VERSION 5.8 ;
BUSBITCHARS "[]" ;
DIVIDERCHAR "/" ;
UNITS
    DATABASE MICRONS 1000 ;
END UNITS

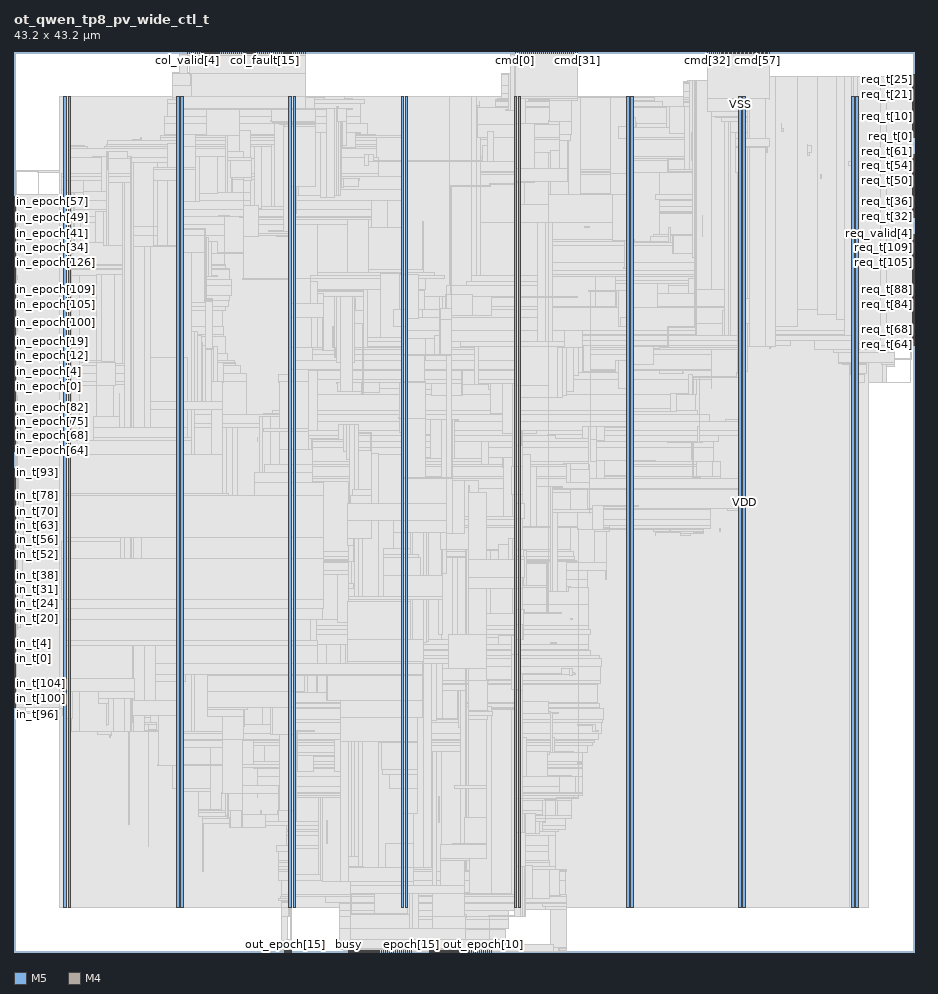
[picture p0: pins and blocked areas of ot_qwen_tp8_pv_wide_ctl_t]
MACRO ot_qwen_tp8_pv_wide_ctl_t
  FOREIGN ot_qwen_tp8_pv_wide_ctl_t 0 0 ;
  CLASS BLOCK ;
  SIZE 43.2 BY 43.2 ;
  PIN busy
    DIRECTION OUTPUT ;
    USE SIGNAL ;
    PORT
      LAYER M5 ;
        RECT  16.08 0 16.104 0.084 ;
    END
  END busy
  PIN clk
    DIRECTION INPUT ;
    USE SIGNAL ;
    PORT
      LAYER M5 ;
        RECT  16.176 0 16.2 0.084 ;
    END
  END clk
  PIN cmd[0]
    DIRECTION OUTPUT ;
    USE SIGNAL ;
    PORT
      LAYER M5 ;
        RECT  24.048 43.116 24.072 43.2 ;
    END
  END cmd[0]
  PIN cmd[10]
    DIRECTION OUTPUT ;
    USE SIGNAL ;
    PORT
      LAYER M5 ;
        RECT  25.008 43.116 25.032 43.2 ;
    END
  END cmd[10]
  PIN cmd[11]
    DIRECTION OUTPUT ;
    USE SIGNAL ;
    PORT
      LAYER M5 ;
        RECT  25.104 43.116 25.128 43.2 ;
    END
  END cmd[11]
  PIN cmd[12]
    DIRECTION OUTPUT ;
    USE SIGNAL ;
    PORT
      LAYER M5 ;
        RECT  25.2 43.116 25.224 43.2 ;
    END
  END cmd[12]
  PIN cmd[13]
    DIRECTION OUTPUT ;
    USE SIGNAL ;
    PORT
      LAYER M5 ;
        RECT  25.296 43.116 25.32 43.2 ;
    END
  END cmd[13]
  PIN cmd[14]
    DIRECTION OUTPUT ;
    USE SIGNAL ;
    PORT
      LAYER M5 ;
        RECT  25.392 43.116 25.416 43.2 ;
    END
  END cmd[14]
  PIN cmd[15]
    DIRECTION OUTPUT ;
    USE SIGNAL ;
    PORT
      LAYER M5 ;
        RECT  25.488 43.116 25.512 43.2 ;
    END
  END cmd[15]
  PIN cmd[16]
    DIRECTION OUTPUT ;
    USE SIGNAL ;
    PORT
      LAYER M5 ;
        RECT  25.584 43.116 25.608 43.2 ;
    END
  END cmd[16]
  PIN cmd[17]
    DIRECTION OUTPUT ;
    USE SIGNAL ;
    PORT
      LAYER M5 ;
        RECT  25.68 43.116 25.704 43.2 ;
    END
  END cmd[17]
  PIN cmd[18]
    DIRECTION OUTPUT ;
    USE SIGNAL ;
    PORT
      LAYER M5 ;
        RECT  25.776 43.116 25.8 43.2 ;
    END
  END cmd[18]
  PIN cmd[19]
    DIRECTION OUTPUT ;
    USE SIGNAL ;
    PORT
      LAYER M5 ;
        RECT  25.872 43.116 25.896 43.2 ;
    END
  END cmd[19]
  PIN cmd[1]
    DIRECTION OUTPUT ;
    USE SIGNAL ;
    PORT
      LAYER M5 ;
        RECT  24.144 43.116 24.168 43.2 ;
    END
  END cmd[1]
  PIN cmd[20]
    DIRECTION OUTPUT ;
    USE SIGNAL ;
    PORT
      LAYER M5 ;
        RECT  25.968 43.116 25.992 43.2 ;
    END
  END cmd[20]
  PIN cmd[21]
    DIRECTION OUTPUT ;
    USE SIGNAL ;
    PORT
      LAYER M5 ;
        RECT  26.064 43.116 26.088 43.2 ;
    END
  END cmd[21]
  PIN cmd[22]
    DIRECTION OUTPUT ;
    USE SIGNAL ;
    PORT
      LAYER M5 ;
        RECT  26.16 43.116 26.184 43.2 ;
    END
  END cmd[22]
  PIN cmd[23]
    DIRECTION OUTPUT ;
    USE SIGNAL ;
    PORT
      LAYER M5 ;
        RECT  26.256 43.116 26.28 43.2 ;
    END
  END cmd[23]
  PIN cmd[24]
    DIRECTION OUTPUT ;
    USE SIGNAL ;
    PORT
      LAYER M5 ;
        RECT  26.352 43.116 26.376 43.2 ;
    END
  END cmd[24]
  PIN cmd[25]
    DIRECTION OUTPUT ;
    USE SIGNAL ;
    PORT
      LAYER M5 ;
        RECT  26.448 43.116 26.472 43.2 ;
    END
  END cmd[25]
  PIN cmd[26]
    DIRECTION OUTPUT ;
    USE SIGNAL ;
    PORT
      LAYER M5 ;
        RECT  26.544 43.116 26.568 43.2 ;
    END
  END cmd[26]
  PIN cmd[27]
    DIRECTION OUTPUT ;
    USE SIGNAL ;
    PORT
      LAYER M5 ;
        RECT  26.64 43.116 26.664 43.2 ;
    END
  END cmd[27]
  PIN cmd[28]
    DIRECTION OUTPUT ;
    USE SIGNAL ;
    PORT
      LAYER M5 ;
        RECT  26.736 43.116 26.76 43.2 ;
    END
  END cmd[28]
  PIN cmd[29]
    DIRECTION OUTPUT ;
    USE SIGNAL ;
    PORT
      LAYER M5 ;
        RECT  26.832 43.116 26.856 43.2 ;
    END
  END cmd[29]
  PIN cmd[2]
    DIRECTION OUTPUT ;
    USE SIGNAL ;
    PORT
      LAYER M5 ;
        RECT  24.24 43.116 24.264 43.2 ;
    END
  END cmd[2]
  PIN cmd[30]
    DIRECTION OUTPUT ;
    USE SIGNAL ;
    PORT
      LAYER M5 ;
        RECT  26.928 43.116 26.952 43.2 ;
    END
  END cmd[30]
  PIN cmd[31]
    DIRECTION OUTPUT ;
    USE SIGNAL ;
    PORT
      LAYER M5 ;
        RECT  27.024 43.116 27.048 43.2 ;
    END
  END cmd[31]
  PIN cmd[32]
    DIRECTION OUTPUT ;
    USE SIGNAL ;
    PORT
      LAYER M5 ;
        RECT  33.264 43.116 33.288 43.2 ;
    END
  END cmd[32]
  PIN cmd[33]
    DIRECTION OUTPUT ;
    USE SIGNAL ;
    PORT
      LAYER M5 ;
        RECT  33.36 43.116 33.384 43.2 ;
    END
  END cmd[33]
  PIN cmd[34]
    DIRECTION OUTPUT ;
    USE SIGNAL ;
    PORT
      LAYER M5 ;
        RECT  33.456 43.116 33.48 43.2 ;
    END
  END cmd[34]
  PIN cmd[35]
    DIRECTION OUTPUT ;
    USE SIGNAL ;
    PORT
      LAYER M5 ;
        RECT  33.552 43.116 33.576 43.2 ;
    END
  END cmd[35]
  PIN cmd[36]
    DIRECTION OUTPUT ;
    USE SIGNAL ;
    PORT
      LAYER M5 ;
        RECT  33.648 43.116 33.672 43.2 ;
    END
  END cmd[36]
  PIN cmd[37]
    DIRECTION OUTPUT ;
    USE SIGNAL ;
    PORT
      LAYER M5 ;
        RECT  33.744 43.116 33.768 43.2 ;
    END
  END cmd[37]
  PIN cmd[38]
    DIRECTION OUTPUT ;
    USE SIGNAL ;
    PORT
      LAYER M5 ;
        RECT  33.84 43.116 33.864 43.2 ;
    END
  END cmd[38]
  PIN cmd[39]
    DIRECTION OUTPUT ;
    USE SIGNAL ;
    PORT
      LAYER M5 ;
        RECT  33.936 43.116 33.96 43.2 ;
    END
  END cmd[39]
  PIN cmd[3]
    DIRECTION OUTPUT ;
    USE SIGNAL ;
    PORT
      LAYER M5 ;
        RECT  24.336 43.116 24.36 43.2 ;
    END
  END cmd[3]
  PIN cmd[40]
    DIRECTION OUTPUT ;
    USE SIGNAL ;
    PORT
      LAYER M5 ;
        RECT  34.032 43.116 34.056 43.2 ;
    END
  END cmd[40]
  PIN cmd[41]
    DIRECTION OUTPUT ;
    USE SIGNAL ;
    PORT
      LAYER M5 ;
        RECT  34.128 43.116 34.152 43.2 ;
    END
  END cmd[41]
  PIN cmd[42]
    DIRECTION OUTPUT ;
    USE SIGNAL ;
    PORT
      LAYER M5 ;
        RECT  34.224 43.116 34.248 43.2 ;
    END
  END cmd[42]
  PIN cmd[43]
    DIRECTION OUTPUT ;
    USE SIGNAL ;
    PORT
      LAYER M5 ;
        RECT  34.32 43.116 34.344 43.2 ;
    END
  END cmd[43]
  PIN cmd[44]
    DIRECTION OUTPUT ;
    USE SIGNAL ;
    PORT
      LAYER M5 ;
        RECT  34.416 43.116 34.44 43.2 ;
    END
  END cmd[44]
  PIN cmd[45]
    DIRECTION OUTPUT ;
    USE SIGNAL ;
    PORT
      LAYER M5 ;
        RECT  34.512 43.116 34.536 43.2 ;
    END
  END cmd[45]
  PIN cmd[46]
    DIRECTION OUTPUT ;
    USE SIGNAL ;
    PORT
      LAYER M5 ;
        RECT  34.608 43.116 34.632 43.2 ;
    END
  END cmd[46]
  PIN cmd[47]
    DIRECTION OUTPUT ;
    USE SIGNAL ;
    PORT
      LAYER M5 ;
        RECT  34.704 43.116 34.728 43.2 ;
    END
  END cmd[47]
  PIN cmd[48]
    DIRECTION OUTPUT ;
    USE SIGNAL ;
    PORT
      LAYER M5 ;
        RECT  34.8 43.116 34.824 43.2 ;
    END
  END cmd[48]
  PIN cmd[49]
    DIRECTION OUTPUT ;
    USE SIGNAL ;
    PORT
      LAYER M5 ;
        RECT  34.896 43.116 34.92 43.2 ;
    END
  END cmd[49]
  PIN cmd[4]
    DIRECTION OUTPUT ;
    USE SIGNAL ;
    PORT
      LAYER M5 ;
        RECT  24.432 43.116 24.456 43.2 ;
    END
  END cmd[4]
  PIN cmd[50]
    DIRECTION OUTPUT ;
    USE SIGNAL ;
    PORT
      LAYER M5 ;
        RECT  34.992 43.116 35.016 43.2 ;
    END
  END cmd[50]
  PIN cmd[51]
    DIRECTION OUTPUT ;
    USE SIGNAL ;
    PORT
      LAYER M5 ;
        RECT  35.088 43.116 35.112 43.2 ;
    END
  END cmd[51]
  PIN cmd[52]
    DIRECTION OUTPUT ;
    USE SIGNAL ;
    PORT
      LAYER M5 ;
        RECT  35.184 43.116 35.208 43.2 ;
    END
  END cmd[52]
  PIN cmd[53]
    DIRECTION OUTPUT ;
    USE SIGNAL ;
    PORT
      LAYER M5 ;
        RECT  35.28 43.116 35.304 43.2 ;
    END
  END cmd[53]
  PIN cmd[54]
    DIRECTION OUTPUT ;
    USE SIGNAL ;
    PORT
      LAYER M5 ;
        RECT  35.376 43.116 35.4 43.2 ;
    END
  END cmd[54]
  PIN cmd[55]
    DIRECTION OUTPUT ;
    USE SIGNAL ;
    PORT
      LAYER M5 ;
        RECT  35.472 43.116 35.496 43.2 ;
    END
  END cmd[55]
  PIN cmd[56]
    DIRECTION OUTPUT ;
    USE SIGNAL ;
    PORT
      LAYER M5 ;
        RECT  35.568 43.116 35.592 43.2 ;
    END
  END cmd[56]
  PIN cmd[57]
    DIRECTION OUTPUT ;
    USE SIGNAL ;
    PORT
      LAYER M5 ;
        RECT  35.664 43.116 35.688 43.2 ;
    END
  END cmd[57]
  PIN cmd[58]
    DIRECTION OUTPUT ;
    USE SIGNAL ;
    PORT
      LAYER M5 ;
        RECT  35.76 43.116 35.784 43.2 ;
    END
  END cmd[58]
  PIN cmd[59]
    DIRECTION OUTPUT ;
    USE SIGNAL ;
    PORT
      LAYER M5 ;
        RECT  35.856 43.116 35.88 43.2 ;
    END
  END cmd[59]
  PIN cmd[5]
    DIRECTION OUTPUT ;
    USE SIGNAL ;
    PORT
      LAYER M5 ;
        RECT  24.528 43.116 24.552 43.2 ;
    END
  END cmd[5]
  PIN cmd[6]
    DIRECTION OUTPUT ;
    USE SIGNAL ;
    PORT
      LAYER M5 ;
        RECT  24.624 43.116 24.648 43.2 ;
    END
  END cmd[6]
  PIN cmd[7]
    DIRECTION OUTPUT ;
    USE SIGNAL ;
    PORT
      LAYER M5 ;
        RECT  24.72 43.116 24.744 43.2 ;
    END
  END cmd[7]
  PIN cmd[8]
    DIRECTION OUTPUT ;
    USE SIGNAL ;
    PORT
      LAYER M5 ;
        RECT  24.816 43.116 24.84 43.2 ;
    END
  END cmd[8]
  PIN cmd[9]
    DIRECTION OUTPUT ;
    USE SIGNAL ;
    PORT
      LAYER M5 ;
        RECT  24.912 43.116 24.936 43.2 ;
    END
  END cmd[9]
  PIN col_fault[0]
    DIRECTION INPUT ;
    USE SIGNAL ;
    PORT
      LAYER M5 ;
        RECT  35.952 43.116 35.976 43.2 ;
    END
  END col_fault[0]
  PIN col_fault[10]
    DIRECTION INPUT ;
    USE SIGNAL ;
    PORT
      LAYER M5 ;
        RECT  11.568 43.116 11.592 43.2 ;
    END
  END col_fault[10]
  PIN col_fault[11]
    DIRECTION INPUT ;
    USE SIGNAL ;
    PORT
      LAYER M5 ;
        RECT  11.664 43.116 11.688 43.2 ;
    END
  END col_fault[11]
  PIN col_fault[12]
    DIRECTION INPUT ;
    USE SIGNAL ;
    PORT
      LAYER M5 ;
        RECT  11.76 43.116 11.784 43.2 ;
    END
  END col_fault[12]
  PIN col_fault[13]
    DIRECTION INPUT ;
    USE SIGNAL ;
    PORT
      LAYER M5 ;
        RECT  11.856 43.116 11.88 43.2 ;
    END
  END col_fault[13]
  PIN col_fault[14]
    DIRECTION INPUT ;
    USE SIGNAL ;
    PORT
      LAYER M5 ;
        RECT  11.952 43.116 11.976 43.2 ;
    END
  END col_fault[14]
  PIN col_fault[15]
    DIRECTION INPUT ;
    USE SIGNAL ;
    PORT
      LAYER M5 ;
        RECT  12.048 43.116 12.072 43.2 ;
    END
  END col_fault[15]
  PIN col_fault[16]
    DIRECTION INPUT ;
    USE SIGNAL ;
    PORT
      LAYER M5 ;
        RECT  12.144 43.116 12.168 43.2 ;
    END
  END col_fault[16]
  PIN col_fault[17]
    DIRECTION INPUT ;
    USE SIGNAL ;
    PORT
      LAYER M5 ;
        RECT  12.24 43.116 12.264 43.2 ;
    END
  END col_fault[17]
  PIN col_fault[18]
    DIRECTION INPUT ;
    USE SIGNAL ;
    PORT
      LAYER M5 ;
        RECT  12.336 43.116 12.36 43.2 ;
    END
  END col_fault[18]
  PIN col_fault[19]
    DIRECTION INPUT ;
    USE SIGNAL ;
    PORT
      LAYER M5 ;
        RECT  12.432 43.116 12.456 43.2 ;
    END
  END col_fault[19]
  PIN col_fault[1]
    DIRECTION INPUT ;
    USE SIGNAL ;
    PORT
      LAYER M5 ;
        RECT  36.048 43.116 36.072 43.2 ;
    END
  END col_fault[1]
  PIN col_fault[20]
    DIRECTION INPUT ;
    USE SIGNAL ;
    PORT
      LAYER M5 ;
        RECT  12.528 43.116 12.552 43.2 ;
    END
  END col_fault[20]
  PIN col_fault[21]
    DIRECTION INPUT ;
    USE SIGNAL ;
    PORT
      LAYER M5 ;
        RECT  12.624 43.116 12.648 43.2 ;
    END
  END col_fault[21]
  PIN col_fault[22]
    DIRECTION INPUT ;
    USE SIGNAL ;
    PORT
      LAYER M5 ;
        RECT  12.72 43.116 12.744 43.2 ;
    END
  END col_fault[22]
  PIN col_fault[23]
    DIRECTION INPUT ;
    USE SIGNAL ;
    PORT
      LAYER M5 ;
        RECT  12.816 43.116 12.84 43.2 ;
    END
  END col_fault[23]
  PIN col_fault[24]
    DIRECTION INPUT ;
    USE SIGNAL ;
    PORT
      LAYER M5 ;
        RECT  12.912 43.116 12.936 43.2 ;
    END
  END col_fault[24]
  PIN col_fault[25]
    DIRECTION INPUT ;
    USE SIGNAL ;
    PORT
      LAYER M5 ;
        RECT  13.008 43.116 13.032 43.2 ;
    END
  END col_fault[25]
  PIN col_fault[26]
    DIRECTION INPUT ;
    USE SIGNAL ;
    PORT
      LAYER M5 ;
        RECT  13.104 43.116 13.128 43.2 ;
    END
  END col_fault[26]
  PIN col_fault[27]
    DIRECTION INPUT ;
    USE SIGNAL ;
    PORT
      LAYER M5 ;
        RECT  13.2 43.116 13.224 43.2 ;
    END
  END col_fault[27]
  PIN col_fault[28]
    DIRECTION INPUT ;
    USE SIGNAL ;
    PORT
      LAYER M5 ;
        RECT  13.296 43.116 13.32 43.2 ;
    END
  END col_fault[28]
  PIN col_fault[29]
    DIRECTION INPUT ;
    USE SIGNAL ;
    PORT
      LAYER M5 ;
        RECT  13.392 43.116 13.416 43.2 ;
    END
  END col_fault[29]
  PIN col_fault[2]
    DIRECTION INPUT ;
    USE SIGNAL ;
    PORT
      LAYER M5 ;
        RECT  36.144 43.116 36.168 43.2 ;
    END
  END col_fault[2]
  PIN col_fault[30]
    DIRECTION INPUT ;
    USE SIGNAL ;
    PORT
      LAYER M5 ;
        RECT  13.488 43.116 13.512 43.2 ;
    END
  END col_fault[30]
  PIN col_fault[31]
    DIRECTION INPUT ;
    USE SIGNAL ;
    PORT
      LAYER M5 ;
        RECT  13.584 43.116 13.608 43.2 ;
    END
  END col_fault[31]
  PIN col_fault[3]
    DIRECTION INPUT ;
    USE SIGNAL ;
    PORT
      LAYER M5 ;
        RECT  36.24 43.116 36.264 43.2 ;
    END
  END col_fault[3]
  PIN col_fault[4]
    DIRECTION INPUT ;
    USE SIGNAL ;
    PORT
      LAYER M5 ;
        RECT  10.992 43.116 11.016 43.2 ;
    END
  END col_fault[4]
  PIN col_fault[5]
    DIRECTION INPUT ;
    USE SIGNAL ;
    PORT
      LAYER M5 ;
        RECT  11.088 43.116 11.112 43.2 ;
    END
  END col_fault[5]
  PIN col_fault[6]
    DIRECTION INPUT ;
    USE SIGNAL ;
    PORT
      LAYER M5 ;
        RECT  11.184 43.116 11.208 43.2 ;
    END
  END col_fault[6]
  PIN col_fault[7]
    DIRECTION INPUT ;
    USE SIGNAL ;
    PORT
      LAYER M5 ;
        RECT  11.28 43.116 11.304 43.2 ;
    END
  END col_fault[7]
  PIN col_fault[8]
    DIRECTION INPUT ;
    USE SIGNAL ;
    PORT
      LAYER M5 ;
        RECT  11.376 43.116 11.4 43.2 ;
    END
  END col_fault[8]
  PIN col_fault[9]
    DIRECTION INPUT ;
    USE SIGNAL ;
    PORT
      LAYER M5 ;
        RECT  11.472 43.116 11.496 43.2 ;
    END
  END col_fault[9]
  PIN col_valid[0]
    DIRECTION INPUT ;
    USE SIGNAL ;
    PORT
      LAYER M5 ;
        RECT  13.68 43.116 13.704 43.2 ;
    END
  END col_valid[0]
  PIN col_valid[10]
    DIRECTION INPUT ;
    USE SIGNAL ;
    PORT
      LAYER M5 ;
        RECT  8.88 43.116 8.904 43.2 ;
    END
  END col_valid[10]
  PIN col_valid[11]
    DIRECTION INPUT ;
    USE SIGNAL ;
    PORT
      LAYER M5 ;
        RECT  8.976 43.116 9 43.2 ;
    END
  END col_valid[11]
  PIN col_valid[12]
    DIRECTION INPUT ;
    USE SIGNAL ;
    PORT
      LAYER M5 ;
        RECT  9.072 43.116 9.096 43.2 ;
    END
  END col_valid[12]
  PIN col_valid[13]
    DIRECTION INPUT ;
    USE SIGNAL ;
    PORT
      LAYER M5 ;
        RECT  9.168 43.116 9.192 43.2 ;
    END
  END col_valid[13]
  PIN col_valid[14]
    DIRECTION INPUT ;
    USE SIGNAL ;
    PORT
      LAYER M5 ;
        RECT  9.264 43.116 9.288 43.2 ;
    END
  END col_valid[14]
  PIN col_valid[15]
    DIRECTION INPUT ;
    USE SIGNAL ;
    PORT
      LAYER M5 ;
        RECT  9.36 43.116 9.384 43.2 ;
    END
  END col_valid[15]
  PIN col_valid[16]
    DIRECTION INPUT ;
    USE SIGNAL ;
    PORT
      LAYER M5 ;
        RECT  9.456 43.116 9.48 43.2 ;
    END
  END col_valid[16]
  PIN col_valid[17]
    DIRECTION INPUT ;
    USE SIGNAL ;
    PORT
      LAYER M5 ;
        RECT  9.552 43.116 9.576 43.2 ;
    END
  END col_valid[17]
  PIN col_valid[18]
    DIRECTION INPUT ;
    USE SIGNAL ;
    PORT
      LAYER M5 ;
        RECT  9.648 43.116 9.672 43.2 ;
    END
  END col_valid[18]
  PIN col_valid[19]
    DIRECTION INPUT ;
    USE SIGNAL ;
    PORT
      LAYER M5 ;
        RECT  9.744 43.116 9.768 43.2 ;
    END
  END col_valid[19]
  PIN col_valid[1]
    DIRECTION INPUT ;
    USE SIGNAL ;
    PORT
      LAYER M5 ;
        RECT  13.776 43.116 13.8 43.2 ;
    END
  END col_valid[1]
  PIN col_valid[20]
    DIRECTION INPUT ;
    USE SIGNAL ;
    PORT
      LAYER M5 ;
        RECT  9.84 43.116 9.864 43.2 ;
    END
  END col_valid[20]
  PIN col_valid[21]
    DIRECTION INPUT ;
    USE SIGNAL ;
    PORT
      LAYER M5 ;
        RECT  9.936 43.116 9.96 43.2 ;
    END
  END col_valid[21]
  PIN col_valid[22]
    DIRECTION INPUT ;
    USE SIGNAL ;
    PORT
      LAYER M5 ;
        RECT  10.032 43.116 10.056 43.2 ;
    END
  END col_valid[22]
  PIN col_valid[23]
    DIRECTION INPUT ;
    USE SIGNAL ;
    PORT
      LAYER M5 ;
        RECT  10.128 43.116 10.152 43.2 ;
    END
  END col_valid[23]
  PIN col_valid[24]
    DIRECTION INPUT ;
    USE SIGNAL ;
    PORT
      LAYER M5 ;
        RECT  10.224 43.116 10.248 43.2 ;
    END
  END col_valid[24]
  PIN col_valid[25]
    DIRECTION INPUT ;
    USE SIGNAL ;
    PORT
      LAYER M5 ;
        RECT  10.32 43.116 10.344 43.2 ;
    END
  END col_valid[25]
  PIN col_valid[26]
    DIRECTION INPUT ;
    USE SIGNAL ;
    PORT
      LAYER M5 ;
        RECT  10.416 43.116 10.44 43.2 ;
    END
  END col_valid[26]
  PIN col_valid[27]
    DIRECTION INPUT ;
    USE SIGNAL ;
    PORT
      LAYER M5 ;
        RECT  10.512 43.116 10.536 43.2 ;
    END
  END col_valid[27]
  PIN col_valid[28]
    DIRECTION INPUT ;
    USE SIGNAL ;
    PORT
      LAYER M5 ;
        RECT  10.608 43.116 10.632 43.2 ;
    END
  END col_valid[28]
  PIN col_valid[29]
    DIRECTION INPUT ;
    USE SIGNAL ;
    PORT
      LAYER M5 ;
        RECT  10.704 43.116 10.728 43.2 ;
    END
  END col_valid[29]
  PIN col_valid[2]
    DIRECTION INPUT ;
    USE SIGNAL ;
    PORT
      LAYER M5 ;
        RECT  13.872 43.116 13.896 43.2 ;
    END
  END col_valid[2]
  PIN col_valid[30]
    DIRECTION INPUT ;
    USE SIGNAL ;
    PORT
      LAYER M5 ;
        RECT  10.8 43.116 10.824 43.2 ;
    END
  END col_valid[30]
  PIN col_valid[31]
    DIRECTION INPUT ;
    USE SIGNAL ;
    PORT
      LAYER M5 ;
        RECT  10.896 43.116 10.92 43.2 ;
    END
  END col_valid[31]
  PIN col_valid[3]
    DIRECTION INPUT ;
    USE SIGNAL ;
    PORT
      LAYER M5 ;
        RECT  13.968 43.116 13.992 43.2 ;
    END
  END col_valid[3]
  PIN col_valid[4]
    DIRECTION INPUT ;
    USE SIGNAL ;
    PORT
      LAYER M5 ;
        RECT  8.304 43.116 8.328 43.2 ;
    END
  END col_valid[4]
  PIN col_valid[5]
    DIRECTION INPUT ;
    USE SIGNAL ;
    PORT
      LAYER M5 ;
        RECT  8.4 43.116 8.424 43.2 ;
    END
  END col_valid[5]
  PIN col_valid[6]
    DIRECTION INPUT ;
    USE SIGNAL ;
    PORT
      LAYER M5 ;
        RECT  8.496 43.116 8.52 43.2 ;
    END
  END col_valid[6]
  PIN col_valid[7]
    DIRECTION INPUT ;
    USE SIGNAL ;
    PORT
      LAYER M5 ;
        RECT  8.592 43.116 8.616 43.2 ;
    END
  END col_valid[7]
  PIN col_valid[8]
    DIRECTION INPUT ;
    USE SIGNAL ;
    PORT
      LAYER M5 ;
        RECT  8.688 43.116 8.712 43.2 ;
    END
  END col_valid[8]
  PIN col_valid[9]
    DIRECTION INPUT ;
    USE SIGNAL ;
    PORT
      LAYER M5 ;
        RECT  8.784 43.116 8.808 43.2 ;
    END
  END col_valid[9]
  PIN context_len[0]
    DIRECTION INPUT ;
    USE SIGNAL ;
    PORT
      LAYER M5 ;
        RECT  16.272 0 16.296 0.084 ;
    END
  END context_len[0]
  PIN context_len[10]
    DIRECTION INPUT ;
    USE SIGNAL ;
    PORT
      LAYER M5 ;
        RECT  17.232 0 17.256 0.084 ;
    END
  END context_len[10]
  PIN context_len[11]
    DIRECTION INPUT ;
    USE SIGNAL ;
    PORT
      LAYER M5 ;
        RECT  17.328 0 17.352 0.084 ;
    END
  END context_len[11]
  PIN context_len[12]
    DIRECTION INPUT ;
    USE SIGNAL ;
    PORT
      LAYER M5 ;
        RECT  17.424 0 17.448 0.084 ;
    END
  END context_len[12]
  PIN context_len[13]
    DIRECTION INPUT ;
    USE SIGNAL ;
    PORT
      LAYER M5 ;
        RECT  17.52 0 17.544 0.084 ;
    END
  END context_len[13]
  PIN context_len[1]
    DIRECTION INPUT ;
    USE SIGNAL ;
    PORT
      LAYER M5 ;
        RECT  16.368 0 16.392 0.084 ;
    END
  END context_len[1]
  PIN context_len[2]
    DIRECTION INPUT ;
    USE SIGNAL ;
    PORT
      LAYER M5 ;
        RECT  16.464 0 16.488 0.084 ;
    END
  END context_len[2]
  PIN context_len[3]
    DIRECTION INPUT ;
    USE SIGNAL ;
    PORT
      LAYER M5 ;
        RECT  16.56 0 16.584 0.084 ;
    END
  END context_len[3]
  PIN context_len[4]
    DIRECTION INPUT ;
    USE SIGNAL ;
    PORT
      LAYER M5 ;
        RECT  16.656 0 16.68 0.084 ;
    END
  END context_len[4]
  PIN context_len[5]
    DIRECTION INPUT ;
    USE SIGNAL ;
    PORT
      LAYER M5 ;
        RECT  16.752 0 16.776 0.084 ;
    END
  END context_len[5]
  PIN context_len[6]
    DIRECTION INPUT ;
    USE SIGNAL ;
    PORT
      LAYER M5 ;
        RECT  16.848 0 16.872 0.084 ;
    END
  END context_len[6]
  PIN context_len[7]
    DIRECTION INPUT ;
    USE SIGNAL ;
    PORT
      LAYER M5 ;
        RECT  16.944 0 16.968 0.084 ;
    END
  END context_len[7]
  PIN context_len[8]
    DIRECTION INPUT ;
    USE SIGNAL ;
    PORT
      LAYER M5 ;
        RECT  17.04 0 17.064 0.084 ;
    END
  END context_len[8]
  PIN context_len[9]
    DIRECTION INPUT ;
    USE SIGNAL ;
    PORT
      LAYER M5 ;
        RECT  17.136 0 17.16 0.084 ;
    END
  END context_len[9]
  PIN epoch[0]
    DIRECTION INPUT ;
    USE SIGNAL ;
    PORT
      LAYER M5 ;
        RECT  17.616 0 17.64 0.084 ;
    END
  END epoch[0]
  PIN epoch[10]
    DIRECTION INPUT ;
    USE SIGNAL ;
    PORT
      LAYER M5 ;
        RECT  18.576 0 18.6 0.084 ;
    END
  END epoch[10]
  PIN epoch[11]
    DIRECTION INPUT ;
    USE SIGNAL ;
    PORT
      LAYER M5 ;
        RECT  18.672 0 18.696 0.084 ;
    END
  END epoch[11]
  PIN epoch[12]
    DIRECTION INPUT ;
    USE SIGNAL ;
    PORT
      LAYER M5 ;
        RECT  18.768 0 18.792 0.084 ;
    END
  END epoch[12]
  PIN epoch[13]
    DIRECTION INPUT ;
    USE SIGNAL ;
    PORT
      LAYER M5 ;
        RECT  18.864 0 18.888 0.084 ;
    END
  END epoch[13]
  PIN epoch[14]
    DIRECTION INPUT ;
    USE SIGNAL ;
    PORT
      LAYER M5 ;
        RECT  18.96 0 18.984 0.084 ;
    END
  END epoch[14]
  PIN epoch[15]
    DIRECTION INPUT ;
    USE SIGNAL ;
    PORT
      LAYER M5 ;
        RECT  19.056 0 19.08 0.084 ;
    END
  END epoch[15]
  PIN epoch[1]
    DIRECTION INPUT ;
    USE SIGNAL ;
    PORT
      LAYER M5 ;
        RECT  17.712 0 17.736 0.084 ;
    END
  END epoch[1]
  PIN epoch[2]
    DIRECTION INPUT ;
    USE SIGNAL ;
    PORT
      LAYER M5 ;
        RECT  17.808 0 17.832 0.084 ;
    END
  END epoch[2]
  PIN epoch[3]
    DIRECTION INPUT ;
    USE SIGNAL ;
    PORT
      LAYER M5 ;
        RECT  17.904 0 17.928 0.084 ;
    END
  END epoch[3]
  PIN epoch[4]
    DIRECTION INPUT ;
    USE SIGNAL ;
    PORT
      LAYER M5 ;
        RECT  18 0 18.024 0.084 ;
    END
  END epoch[4]
  PIN epoch[5]
    DIRECTION INPUT ;
    USE SIGNAL ;
    PORT
      LAYER M5 ;
        RECT  18.096 0 18.12 0.084 ;
    END
  END epoch[5]
  PIN epoch[6]
    DIRECTION INPUT ;
    USE SIGNAL ;
    PORT
      LAYER M5 ;
        RECT  18.192 0 18.216 0.084 ;
    END
  END epoch[6]
  PIN epoch[7]
    DIRECTION INPUT ;
    USE SIGNAL ;
    PORT
      LAYER M5 ;
        RECT  18.288 0 18.312 0.084 ;
    END
  END epoch[7]
  PIN epoch[8]
    DIRECTION INPUT ;
    USE SIGNAL ;
    PORT
      LAYER M5 ;
        RECT  18.384 0 18.408 0.084 ;
    END
  END epoch[8]
  PIN epoch[9]
    DIRECTION INPUT ;
    USE SIGNAL ;
    PORT
      LAYER M5 ;
        RECT  18.48 0 18.504 0.084 ;
    END
  END epoch[9]
  PIN fault
    DIRECTION OUTPUT ;
    USE SIGNAL ;
    PORT
      LAYER M5 ;
        RECT  19.92 0 19.944 0.084 ;
    END
  END fault
  PIN in_epoch[0]
    DIRECTION INPUT ;
    USE SIGNAL ;
    PORT
      LAYER M4 ;
        RECT  0 27.12 0.084 27.144 ;
    END
  END in_epoch[0]
  PIN in_epoch[100]
    DIRECTION INPUT ;
    USE SIGNAL ;
    PORT
      LAYER M4 ;
        RECT  0 30.576 0.084 30.6 ;
    END
  END in_epoch[100]
  PIN in_epoch[101]
    DIRECTION INPUT ;
    USE SIGNAL ;
    PORT
      LAYER M4 ;
        RECT  0 30.672 0.084 30.696 ;
    END
  END in_epoch[101]
  PIN in_epoch[102]
    DIRECTION INPUT ;
    USE SIGNAL ;
    PORT
      LAYER M4 ;
        RECT  0 30.768 0.084 30.792 ;
    END
  END in_epoch[102]
  PIN in_epoch[103]
    DIRECTION INPUT ;
    USE SIGNAL ;
    PORT
      LAYER M4 ;
        RECT  0 30.864 0.084 30.888 ;
    END
  END in_epoch[103]
  PIN in_epoch[104]
    DIRECTION INPUT ;
    USE SIGNAL ;
    PORT
      LAYER M4 ;
        RECT  0 30.96 0.084 30.984 ;
    END
  END in_epoch[104]
  PIN in_epoch[105]
    DIRECTION INPUT ;
    USE SIGNAL ;
    PORT
      LAYER M4 ;
        RECT  0 31.056 0.084 31.08 ;
    END
  END in_epoch[105]
  PIN in_epoch[106]
    DIRECTION INPUT ;
    USE SIGNAL ;
    PORT
      LAYER M4 ;
        RECT  0 31.152 0.084 31.176 ;
    END
  END in_epoch[106]
  PIN in_epoch[107]
    DIRECTION INPUT ;
    USE SIGNAL ;
    PORT
      LAYER M4 ;
        RECT  0 31.248 0.084 31.272 ;
    END
  END in_epoch[107]
  PIN in_epoch[108]
    DIRECTION INPUT ;
    USE SIGNAL ;
    PORT
      LAYER M4 ;
        RECT  0 31.344 0.084 31.368 ;
    END
  END in_epoch[108]
  PIN in_epoch[109]
    DIRECTION INPUT ;
    USE SIGNAL ;
    PORT
      LAYER M4 ;
        RECT  0 31.44 0.084 31.464 ;
    END
  END in_epoch[109]
  PIN in_epoch[10]
    DIRECTION INPUT ;
    USE SIGNAL ;
    PORT
      LAYER M4 ;
        RECT  0 28.08 0.084 28.104 ;
    END
  END in_epoch[10]
  PIN in_epoch[110]
    DIRECTION INPUT ;
    USE SIGNAL ;
    PORT
      LAYER M4 ;
        RECT  0 31.536 0.084 31.56 ;
    END
  END in_epoch[110]
  PIN in_epoch[111]
    DIRECTION INPUT ;
    USE SIGNAL ;
    PORT
      LAYER M4 ;
        RECT  0 31.632 0.084 31.656 ;
    END
  END in_epoch[111]
  PIN in_epoch[112]
    DIRECTION INPUT ;
    USE SIGNAL ;
    PORT
      LAYER M4 ;
        RECT  0 31.728 0.084 31.752 ;
    END
  END in_epoch[112]
  PIN in_epoch[113]
    DIRECTION INPUT ;
    USE SIGNAL ;
    PORT
      LAYER M4 ;
        RECT  0 31.824 0.084 31.848 ;
    END
  END in_epoch[113]
  PIN in_epoch[114]
    DIRECTION INPUT ;
    USE SIGNAL ;
    PORT
      LAYER M4 ;
        RECT  0 31.92 0.084 31.944 ;
    END
  END in_epoch[114]
  PIN in_epoch[115]
    DIRECTION INPUT ;
    USE SIGNAL ;
    PORT
      LAYER M4 ;
        RECT  0 32.016 0.084 32.04 ;
    END
  END in_epoch[115]
  PIN in_epoch[116]
    DIRECTION INPUT ;
    USE SIGNAL ;
    PORT
      LAYER M4 ;
        RECT  0 32.112 0.084 32.136 ;
    END
  END in_epoch[116]
  PIN in_epoch[117]
    DIRECTION INPUT ;
    USE SIGNAL ;
    PORT
      LAYER M4 ;
        RECT  0 32.208 0.084 32.232 ;
    END
  END in_epoch[117]
  PIN in_epoch[118]
    DIRECTION INPUT ;
    USE SIGNAL ;
    PORT
      LAYER M4 ;
        RECT  0 32.304 0.084 32.328 ;
    END
  END in_epoch[118]
  PIN in_epoch[119]
    DIRECTION INPUT ;
    USE SIGNAL ;
    PORT
      LAYER M4 ;
        RECT  0 32.4 0.084 32.424 ;
    END
  END in_epoch[119]
  PIN in_epoch[11]
    DIRECTION INPUT ;
    USE SIGNAL ;
    PORT
      LAYER M4 ;
        RECT  0 28.176 0.084 28.2 ;
    END
  END in_epoch[11]
  PIN in_epoch[120]
    DIRECTION INPUT ;
    USE SIGNAL ;
    PORT
      LAYER M4 ;
        RECT  0 32.496 0.084 32.52 ;
    END
  END in_epoch[120]
  PIN in_epoch[121]
    DIRECTION INPUT ;
    USE SIGNAL ;
    PORT
      LAYER M4 ;
        RECT  0 32.592 0.084 32.616 ;
    END
  END in_epoch[121]
  PIN in_epoch[122]
    DIRECTION INPUT ;
    USE SIGNAL ;
    PORT
      LAYER M4 ;
        RECT  0 32.688 0.084 32.712 ;
    END
  END in_epoch[122]
  PIN in_epoch[123]
    DIRECTION INPUT ;
    USE SIGNAL ;
    PORT
      LAYER M4 ;
        RECT  0 32.784 0.084 32.808 ;
    END
  END in_epoch[123]
  PIN in_epoch[124]
    DIRECTION INPUT ;
    USE SIGNAL ;
    PORT
      LAYER M4 ;
        RECT  0 32.88 0.084 32.904 ;
    END
  END in_epoch[124]
  PIN in_epoch[125]
    DIRECTION INPUT ;
    USE SIGNAL ;
    PORT
      LAYER M4 ;
        RECT  0 32.976 0.084 33 ;
    END
  END in_epoch[125]
  PIN in_epoch[126]
    DIRECTION INPUT ;
    USE SIGNAL ;
    PORT
      LAYER M4 ;
        RECT  0 33.072 0.084 33.096 ;
    END
  END in_epoch[126]
  PIN in_epoch[127]
    DIRECTION INPUT ;
    USE SIGNAL ;
    PORT
      LAYER M4 ;
        RECT  0 33.168 0.084 33.192 ;
    END
  END in_epoch[127]
  PIN in_epoch[12]
    DIRECTION INPUT ;
    USE SIGNAL ;
    PORT
      LAYER M4 ;
        RECT  0 28.272 0.084 28.296 ;
    END
  END in_epoch[12]
  PIN in_epoch[13]
    DIRECTION INPUT ;
    USE SIGNAL ;
    PORT
      LAYER M4 ;
        RECT  0 28.368 0.084 28.392 ;
    END
  END in_epoch[13]
  PIN in_epoch[14]
    DIRECTION INPUT ;
    USE SIGNAL ;
    PORT
      LAYER M4 ;
        RECT  0 28.464 0.084 28.488 ;
    END
  END in_epoch[14]
  PIN in_epoch[15]
    DIRECTION INPUT ;
    USE SIGNAL ;
    PORT
      LAYER M4 ;
        RECT  0 28.56 0.084 28.584 ;
    END
  END in_epoch[15]
  PIN in_epoch[16]
    DIRECTION INPUT ;
    USE SIGNAL ;
    PORT
      LAYER M4 ;
        RECT  0 28.656 0.084 28.68 ;
    END
  END in_epoch[16]
  PIN in_epoch[17]
    DIRECTION INPUT ;
    USE SIGNAL ;
    PORT
      LAYER M4 ;
        RECT  0 28.752 0.084 28.776 ;
    END
  END in_epoch[17]
  PIN in_epoch[18]
    DIRECTION INPUT ;
    USE SIGNAL ;
    PORT
      LAYER M4 ;
        RECT  0 28.848 0.084 28.872 ;
    END
  END in_epoch[18]
  PIN in_epoch[19]
    DIRECTION INPUT ;
    USE SIGNAL ;
    PORT
      LAYER M4 ;
        RECT  0 28.944 0.084 28.968 ;
    END
  END in_epoch[19]
  PIN in_epoch[1]
    DIRECTION INPUT ;
    USE SIGNAL ;
    PORT
      LAYER M4 ;
        RECT  0 27.216 0.084 27.24 ;
    END
  END in_epoch[1]
  PIN in_epoch[20]
    DIRECTION INPUT ;
    USE SIGNAL ;
    PORT
      LAYER M4 ;
        RECT  0 29.04 0.084 29.064 ;
    END
  END in_epoch[20]
  PIN in_epoch[21]
    DIRECTION INPUT ;
    USE SIGNAL ;
    PORT
      LAYER M4 ;
        RECT  0 29.136 0.084 29.16 ;
    END
  END in_epoch[21]
  PIN in_epoch[22]
    DIRECTION INPUT ;
    USE SIGNAL ;
    PORT
      LAYER M4 ;
        RECT  0 29.232 0.084 29.256 ;
    END
  END in_epoch[22]
  PIN in_epoch[23]
    DIRECTION INPUT ;
    USE SIGNAL ;
    PORT
      LAYER M4 ;
        RECT  0 29.328 0.084 29.352 ;
    END
  END in_epoch[23]
  PIN in_epoch[24]
    DIRECTION INPUT ;
    USE SIGNAL ;
    PORT
      LAYER M4 ;
        RECT  0 29.424 0.084 29.448 ;
    END
  END in_epoch[24]
  PIN in_epoch[25]
    DIRECTION INPUT ;
    USE SIGNAL ;
    PORT
      LAYER M4 ;
        RECT  0 29.52 0.084 29.544 ;
    END
  END in_epoch[25]
  PIN in_epoch[26]
    DIRECTION INPUT ;
    USE SIGNAL ;
    PORT
      LAYER M4 ;
        RECT  0 29.616 0.084 29.64 ;
    END
  END in_epoch[26]
  PIN in_epoch[27]
    DIRECTION INPUT ;
    USE SIGNAL ;
    PORT
      LAYER M4 ;
        RECT  0 29.712 0.084 29.736 ;
    END
  END in_epoch[27]
  PIN in_epoch[28]
    DIRECTION INPUT ;
    USE SIGNAL ;
    PORT
      LAYER M4 ;
        RECT  0 29.808 0.084 29.832 ;
    END
  END in_epoch[28]
  PIN in_epoch[29]
    DIRECTION INPUT ;
    USE SIGNAL ;
    PORT
      LAYER M4 ;
        RECT  0 29.904 0.084 29.928 ;
    END
  END in_epoch[29]
  PIN in_epoch[2]
    DIRECTION INPUT ;
    USE SIGNAL ;
    PORT
      LAYER M4 ;
        RECT  0 27.312 0.084 27.336 ;
    END
  END in_epoch[2]
  PIN in_epoch[30]
    DIRECTION INPUT ;
    USE SIGNAL ;
    PORT
      LAYER M4 ;
        RECT  0 30 0.084 30.024 ;
    END
  END in_epoch[30]
  PIN in_epoch[31]
    DIRECTION INPUT ;
    USE SIGNAL ;
    PORT
      LAYER M4 ;
        RECT  0 30.096 0.084 30.12 ;
    END
  END in_epoch[31]
  PIN in_epoch[32]
    DIRECTION INPUT ;
    USE SIGNAL ;
    PORT
      LAYER M4 ;
        RECT  0 33.264 0.084 33.288 ;
    END
  END in_epoch[32]
  PIN in_epoch[33]
    DIRECTION INPUT ;
    USE SIGNAL ;
    PORT
      LAYER M4 ;
        RECT  0 33.36 0.084 33.384 ;
    END
  END in_epoch[33]
  PIN in_epoch[34]
    DIRECTION INPUT ;
    USE SIGNAL ;
    PORT
      LAYER M4 ;
        RECT  0 33.456 0.084 33.48 ;
    END
  END in_epoch[34]
  PIN in_epoch[35]
    DIRECTION INPUT ;
    USE SIGNAL ;
    PORT
      LAYER M4 ;
        RECT  0 33.552 0.084 33.576 ;
    END
  END in_epoch[35]
  PIN in_epoch[36]
    DIRECTION INPUT ;
    USE SIGNAL ;
    PORT
      LAYER M4 ;
        RECT  0 33.648 0.084 33.672 ;
    END
  END in_epoch[36]
  PIN in_epoch[37]
    DIRECTION INPUT ;
    USE SIGNAL ;
    PORT
      LAYER M4 ;
        RECT  0 33.744 0.084 33.768 ;
    END
  END in_epoch[37]
  PIN in_epoch[38]
    DIRECTION INPUT ;
    USE SIGNAL ;
    PORT
      LAYER M4 ;
        RECT  0 33.84 0.084 33.864 ;
    END
  END in_epoch[38]
  PIN in_epoch[39]
    DIRECTION INPUT ;
    USE SIGNAL ;
    PORT
      LAYER M4 ;
        RECT  0 33.936 0.084 33.96 ;
    END
  END in_epoch[39]
  PIN in_epoch[3]
    DIRECTION INPUT ;
    USE SIGNAL ;
    PORT
      LAYER M4 ;
        RECT  0 27.408 0.084 27.432 ;
    END
  END in_epoch[3]
  PIN in_epoch[40]
    DIRECTION INPUT ;
    USE SIGNAL ;
    PORT
      LAYER M4 ;
        RECT  0 34.032 0.084 34.056 ;
    END
  END in_epoch[40]
  PIN in_epoch[41]
    DIRECTION INPUT ;
    USE SIGNAL ;
    PORT
      LAYER M4 ;
        RECT  0 34.128 0.084 34.152 ;
    END
  END in_epoch[41]
  PIN in_epoch[42]
    DIRECTION INPUT ;
    USE SIGNAL ;
    PORT
      LAYER M4 ;
        RECT  0 34.224 0.084 34.248 ;
    END
  END in_epoch[42]
  PIN in_epoch[43]
    DIRECTION INPUT ;
    USE SIGNAL ;
    PORT
      LAYER M4 ;
        RECT  0 34.32 0.084 34.344 ;
    END
  END in_epoch[43]
  PIN in_epoch[44]
    DIRECTION INPUT ;
    USE SIGNAL ;
    PORT
      LAYER M4 ;
        RECT  0 34.416 0.084 34.44 ;
    END
  END in_epoch[44]
  PIN in_epoch[45]
    DIRECTION INPUT ;
    USE SIGNAL ;
    PORT
      LAYER M4 ;
        RECT  0 34.512 0.084 34.536 ;
    END
  END in_epoch[45]
  PIN in_epoch[46]
    DIRECTION INPUT ;
    USE SIGNAL ;
    PORT
      LAYER M4 ;
        RECT  0 34.608 0.084 34.632 ;
    END
  END in_epoch[46]
  PIN in_epoch[47]
    DIRECTION INPUT ;
    USE SIGNAL ;
    PORT
      LAYER M4 ;
        RECT  0 34.704 0.084 34.728 ;
    END
  END in_epoch[47]
  PIN in_epoch[48]
    DIRECTION INPUT ;
    USE SIGNAL ;
    PORT
      LAYER M4 ;
        RECT  0 34.8 0.084 34.824 ;
    END
  END in_epoch[48]
  PIN in_epoch[49]
    DIRECTION INPUT ;
    USE SIGNAL ;
    PORT
      LAYER M4 ;
        RECT  0 34.896 0.084 34.92 ;
    END
  END in_epoch[49]
  PIN in_epoch[4]
    DIRECTION INPUT ;
    USE SIGNAL ;
    PORT
      LAYER M4 ;
        RECT  0 27.504 0.084 27.528 ;
    END
  END in_epoch[4]
  PIN in_epoch[50]
    DIRECTION INPUT ;
    USE SIGNAL ;
    PORT
      LAYER M4 ;
        RECT  0 34.992 0.084 35.016 ;
    END
  END in_epoch[50]
  PIN in_epoch[51]
    DIRECTION INPUT ;
    USE SIGNAL ;
    PORT
      LAYER M4 ;
        RECT  0 35.088 0.084 35.112 ;
    END
  END in_epoch[51]
  PIN in_epoch[52]
    DIRECTION INPUT ;
    USE SIGNAL ;
    PORT
      LAYER M4 ;
        RECT  0 35.184 0.084 35.208 ;
    END
  END in_epoch[52]
  PIN in_epoch[53]
    DIRECTION INPUT ;
    USE SIGNAL ;
    PORT
      LAYER M4 ;
        RECT  0 35.28 0.084 35.304 ;
    END
  END in_epoch[53]
  PIN in_epoch[54]
    DIRECTION INPUT ;
    USE SIGNAL ;
    PORT
      LAYER M4 ;
        RECT  0 35.376 0.084 35.4 ;
    END
  END in_epoch[54]
  PIN in_epoch[55]
    DIRECTION INPUT ;
    USE SIGNAL ;
    PORT
      LAYER M4 ;
        RECT  0 35.472 0.084 35.496 ;
    END
  END in_epoch[55]
  PIN in_epoch[56]
    DIRECTION INPUT ;
    USE SIGNAL ;
    PORT
      LAYER M4 ;
        RECT  0 35.568 0.084 35.592 ;
    END
  END in_epoch[56]
  PIN in_epoch[57]
    DIRECTION INPUT ;
    USE SIGNAL ;
    PORT
      LAYER M4 ;
        RECT  0 35.664 0.084 35.688 ;
    END
  END in_epoch[57]
  PIN in_epoch[58]
    DIRECTION INPUT ;
    USE SIGNAL ;
    PORT
      LAYER M4 ;
        RECT  0 35.76 0.084 35.784 ;
    END
  END in_epoch[58]
  PIN in_epoch[59]
    DIRECTION INPUT ;
    USE SIGNAL ;
    PORT
      LAYER M4 ;
        RECT  0 35.856 0.084 35.88 ;
    END
  END in_epoch[59]
  PIN in_epoch[5]
    DIRECTION INPUT ;
    USE SIGNAL ;
    PORT
      LAYER M4 ;
        RECT  0 27.6 0.084 27.624 ;
    END
  END in_epoch[5]
  PIN in_epoch[60]
    DIRECTION INPUT ;
    USE SIGNAL ;
    PORT
      LAYER M4 ;
        RECT  0 35.952 0.084 35.976 ;
    END
  END in_epoch[60]
  PIN in_epoch[61]
    DIRECTION INPUT ;
    USE SIGNAL ;
    PORT
      LAYER M4 ;
        RECT  0 36.048 0.084 36.072 ;
    END
  END in_epoch[61]
  PIN in_epoch[62]
    DIRECTION INPUT ;
    USE SIGNAL ;
    PORT
      LAYER M4 ;
        RECT  0 36.144 0.084 36.168 ;
    END
  END in_epoch[62]
  PIN in_epoch[63]
    DIRECTION INPUT ;
    USE SIGNAL ;
    PORT
      LAYER M4 ;
        RECT  0 36.24 0.084 36.264 ;
    END
  END in_epoch[63]
  PIN in_epoch[64]
    DIRECTION INPUT ;
    USE SIGNAL ;
    PORT
      LAYER M4 ;
        RECT  0 24.048 0.084 24.072 ;
    END
  END in_epoch[64]
  PIN in_epoch[65]
    DIRECTION INPUT ;
    USE SIGNAL ;
    PORT
      LAYER M4 ;
        RECT  0 24.144 0.084 24.168 ;
    END
  END in_epoch[65]
  PIN in_epoch[66]
    DIRECTION INPUT ;
    USE SIGNAL ;
    PORT
      LAYER M4 ;
        RECT  0 24.24 0.084 24.264 ;
    END
  END in_epoch[66]
  PIN in_epoch[67]
    DIRECTION INPUT ;
    USE SIGNAL ;
    PORT
      LAYER M4 ;
        RECT  0 24.336 0.084 24.36 ;
    END
  END in_epoch[67]
  PIN in_epoch[68]
    DIRECTION INPUT ;
    USE SIGNAL ;
    PORT
      LAYER M4 ;
        RECT  0 24.432 0.084 24.456 ;
    END
  END in_epoch[68]
  PIN in_epoch[69]
    DIRECTION INPUT ;
    USE SIGNAL ;
    PORT
      LAYER M4 ;
        RECT  0 24.528 0.084 24.552 ;
    END
  END in_epoch[69]
  PIN in_epoch[6]
    DIRECTION INPUT ;
    USE SIGNAL ;
    PORT
      LAYER M4 ;
        RECT  0 27.696 0.084 27.72 ;
    END
  END in_epoch[6]
  PIN in_epoch[70]
    DIRECTION INPUT ;
    USE SIGNAL ;
    PORT
      LAYER M4 ;
        RECT  0 24.624 0.084 24.648 ;
    END
  END in_epoch[70]
  PIN in_epoch[71]
    DIRECTION INPUT ;
    USE SIGNAL ;
    PORT
      LAYER M4 ;
        RECT  0 24.72 0.084 24.744 ;
    END
  END in_epoch[71]
  PIN in_epoch[72]
    DIRECTION INPUT ;
    USE SIGNAL ;
    PORT
      LAYER M4 ;
        RECT  0 24.816 0.084 24.84 ;
    END
  END in_epoch[72]
  PIN in_epoch[73]
    DIRECTION INPUT ;
    USE SIGNAL ;
    PORT
      LAYER M4 ;
        RECT  0 24.912 0.084 24.936 ;
    END
  END in_epoch[73]
  PIN in_epoch[74]
    DIRECTION INPUT ;
    USE SIGNAL ;
    PORT
      LAYER M4 ;
        RECT  0 25.008 0.084 25.032 ;
    END
  END in_epoch[74]
  PIN in_epoch[75]
    DIRECTION INPUT ;
    USE SIGNAL ;
    PORT
      LAYER M4 ;
        RECT  0 25.104 0.084 25.128 ;
    END
  END in_epoch[75]
  PIN in_epoch[76]
    DIRECTION INPUT ;
    USE SIGNAL ;
    PORT
      LAYER M4 ;
        RECT  0 25.2 0.084 25.224 ;
    END
  END in_epoch[76]
  PIN in_epoch[77]
    DIRECTION INPUT ;
    USE SIGNAL ;
    PORT
      LAYER M4 ;
        RECT  0 25.296 0.084 25.32 ;
    END
  END in_epoch[77]
  PIN in_epoch[78]
    DIRECTION INPUT ;
    USE SIGNAL ;
    PORT
      LAYER M4 ;
        RECT  0 25.392 0.084 25.416 ;
    END
  END in_epoch[78]
  PIN in_epoch[79]
    DIRECTION INPUT ;
    USE SIGNAL ;
    PORT
      LAYER M4 ;
        RECT  0 25.488 0.084 25.512 ;
    END
  END in_epoch[79]
  PIN in_epoch[7]
    DIRECTION INPUT ;
    USE SIGNAL ;
    PORT
      LAYER M4 ;
        RECT  0 27.792 0.084 27.816 ;
    END
  END in_epoch[7]
  PIN in_epoch[80]
    DIRECTION INPUT ;
    USE SIGNAL ;
    PORT
      LAYER M4 ;
        RECT  0 25.584 0.084 25.608 ;
    END
  END in_epoch[80]
  PIN in_epoch[81]
    DIRECTION INPUT ;
    USE SIGNAL ;
    PORT
      LAYER M4 ;
        RECT  0 25.68 0.084 25.704 ;
    END
  END in_epoch[81]
  PIN in_epoch[82]
    DIRECTION INPUT ;
    USE SIGNAL ;
    PORT
      LAYER M4 ;
        RECT  0 25.776 0.084 25.8 ;
    END
  END in_epoch[82]
  PIN in_epoch[83]
    DIRECTION INPUT ;
    USE SIGNAL ;
    PORT
      LAYER M4 ;
        RECT  0 25.872 0.084 25.896 ;
    END
  END in_epoch[83]
  PIN in_epoch[84]
    DIRECTION INPUT ;
    USE SIGNAL ;
    PORT
      LAYER M4 ;
        RECT  0 25.968 0.084 25.992 ;
    END
  END in_epoch[84]
  PIN in_epoch[85]
    DIRECTION INPUT ;
    USE SIGNAL ;
    PORT
      LAYER M4 ;
        RECT  0 26.064 0.084 26.088 ;
    END
  END in_epoch[85]
  PIN in_epoch[86]
    DIRECTION INPUT ;
    USE SIGNAL ;
    PORT
      LAYER M4 ;
        RECT  0 26.16 0.084 26.184 ;
    END
  END in_epoch[86]
  PIN in_epoch[87]
    DIRECTION INPUT ;
    USE SIGNAL ;
    PORT
      LAYER M4 ;
        RECT  0 26.256 0.084 26.28 ;
    END
  END in_epoch[87]
  PIN in_epoch[88]
    DIRECTION INPUT ;
    USE SIGNAL ;
    PORT
      LAYER M4 ;
        RECT  0 26.352 0.084 26.376 ;
    END
  END in_epoch[88]
  PIN in_epoch[89]
    DIRECTION INPUT ;
    USE SIGNAL ;
    PORT
      LAYER M4 ;
        RECT  0 26.448 0.084 26.472 ;
    END
  END in_epoch[89]
  PIN in_epoch[8]
    DIRECTION INPUT ;
    USE SIGNAL ;
    PORT
      LAYER M4 ;
        RECT  0 27.888 0.084 27.912 ;
    END
  END in_epoch[8]
  PIN in_epoch[90]
    DIRECTION INPUT ;
    USE SIGNAL ;
    PORT
      LAYER M4 ;
        RECT  0 26.544 0.084 26.568 ;
    END
  END in_epoch[90]
  PIN in_epoch[91]
    DIRECTION INPUT ;
    USE SIGNAL ;
    PORT
      LAYER M4 ;
        RECT  0 26.64 0.084 26.664 ;
    END
  END in_epoch[91]
  PIN in_epoch[92]
    DIRECTION INPUT ;
    USE SIGNAL ;
    PORT
      LAYER M4 ;
        RECT  0 26.736 0.084 26.76 ;
    END
  END in_epoch[92]
  PIN in_epoch[93]
    DIRECTION INPUT ;
    USE SIGNAL ;
    PORT
      LAYER M4 ;
        RECT  0 26.832 0.084 26.856 ;
    END
  END in_epoch[93]
  PIN in_epoch[94]
    DIRECTION INPUT ;
    USE SIGNAL ;
    PORT
      LAYER M4 ;
        RECT  0 26.928 0.084 26.952 ;
    END
  END in_epoch[94]
  PIN in_epoch[95]
    DIRECTION INPUT ;
    USE SIGNAL ;
    PORT
      LAYER M4 ;
        RECT  0 27.024 0.084 27.048 ;
    END
  END in_epoch[95]
  PIN in_epoch[96]
    DIRECTION INPUT ;
    USE SIGNAL ;
    PORT
      LAYER M4 ;
        RECT  0 30.192 0.084 30.216 ;
    END
  END in_epoch[96]
  PIN in_epoch[97]
    DIRECTION INPUT ;
    USE SIGNAL ;
    PORT
      LAYER M4 ;
        RECT  0 30.288 0.084 30.312 ;
    END
  END in_epoch[97]
  PIN in_epoch[98]
    DIRECTION INPUT ;
    USE SIGNAL ;
    PORT
      LAYER M4 ;
        RECT  0 30.384 0.084 30.408 ;
    END
  END in_epoch[98]
  PIN in_epoch[99]
    DIRECTION INPUT ;
    USE SIGNAL ;
    PORT
      LAYER M4 ;
        RECT  0 30.48 0.084 30.504 ;
    END
  END in_epoch[99]
  PIN in_epoch[9]
    DIRECTION INPUT ;
    USE SIGNAL ;
    PORT
      LAYER M4 ;
        RECT  0 27.984 0.084 28.008 ;
    END
  END in_epoch[9]
  PIN in_t[0]
    DIRECTION INPUT ;
    USE SIGNAL ;
    PORT
      LAYER M4 ;
        RECT  0 14.064 0.084 14.088 ;
    END
  END in_t[0]
  PIN in_t[100]
    DIRECTION INPUT ;
    USE SIGNAL ;
    PORT
      LAYER M4 ;
        RECT  0 12.144 0.084 12.168 ;
    END
  END in_t[100]
  PIN in_t[101]
    DIRECTION INPUT ;
    USE SIGNAL ;
    PORT
      LAYER M4 ;
        RECT  0 12.24 0.084 12.264 ;
    END
  END in_t[101]
  PIN in_t[102]
    DIRECTION INPUT ;
    USE SIGNAL ;
    PORT
      LAYER M4 ;
        RECT  0 12.336 0.084 12.36 ;
    END
  END in_t[102]
  PIN in_t[103]
    DIRECTION INPUT ;
    USE SIGNAL ;
    PORT
      LAYER M4 ;
        RECT  0 12.432 0.084 12.456 ;
    END
  END in_t[103]
  PIN in_t[104]
    DIRECTION INPUT ;
    USE SIGNAL ;
    PORT
      LAYER M4 ;
        RECT  0 12.528 0.084 12.552 ;
    END
  END in_t[104]
  PIN in_t[105]
    DIRECTION INPUT ;
    USE SIGNAL ;
    PORT
      LAYER M4 ;
        RECT  0 12.624 0.084 12.648 ;
    END
  END in_t[105]
  PIN in_t[106]
    DIRECTION INPUT ;
    USE SIGNAL ;
    PORT
      LAYER M4 ;
        RECT  0 12.72 0.084 12.744 ;
    END
  END in_t[106]
  PIN in_t[107]
    DIRECTION INPUT ;
    USE SIGNAL ;
    PORT
      LAYER M4 ;
        RECT  0 12.816 0.084 12.84 ;
    END
  END in_t[107]
  PIN in_t[108]
    DIRECTION INPUT ;
    USE SIGNAL ;
    PORT
      LAYER M4 ;
        RECT  0 12.912 0.084 12.936 ;
    END
  END in_t[108]
  PIN in_t[109]
    DIRECTION INPUT ;
    USE SIGNAL ;
    PORT
      LAYER M4 ;
        RECT  0 13.008 0.084 13.032 ;
    END
  END in_t[109]
  PIN in_t[10]
    DIRECTION INPUT ;
    USE SIGNAL ;
    PORT
      LAYER M4 ;
        RECT  0 15.024 0.084 15.048 ;
    END
  END in_t[10]
  PIN in_t[110]
    DIRECTION INPUT ;
    USE SIGNAL ;
    PORT
      LAYER M4 ;
        RECT  0 13.104 0.084 13.128 ;
    END
  END in_t[110]
  PIN in_t[111]
    DIRECTION INPUT ;
    USE SIGNAL ;
    PORT
      LAYER M4 ;
        RECT  0 13.2 0.084 13.224 ;
    END
  END in_t[111]
  PIN in_t[11]
    DIRECTION INPUT ;
    USE SIGNAL ;
    PORT
      LAYER M4 ;
        RECT  0 15.12 0.084 15.144 ;
    END
  END in_t[11]
  PIN in_t[12]
    DIRECTION INPUT ;
    USE SIGNAL ;
    PORT
      LAYER M4 ;
        RECT  0 15.216 0.084 15.24 ;
    END
  END in_t[12]
  PIN in_t[13]
    DIRECTION INPUT ;
    USE SIGNAL ;
    PORT
      LAYER M4 ;
        RECT  0 15.312 0.084 15.336 ;
    END
  END in_t[13]
  PIN in_t[14]
    DIRECTION INPUT ;
    USE SIGNAL ;
    PORT
      LAYER M4 ;
        RECT  0 15.408 0.084 15.432 ;
    END
  END in_t[14]
  PIN in_t[15]
    DIRECTION INPUT ;
    USE SIGNAL ;
    PORT
      LAYER M4 ;
        RECT  0 15.504 0.084 15.528 ;
    END
  END in_t[15]
  PIN in_t[16]
    DIRECTION INPUT ;
    USE SIGNAL ;
    PORT
      LAYER M4 ;
        RECT  0 15.6 0.084 15.624 ;
    END
  END in_t[16]
  PIN in_t[17]
    DIRECTION INPUT ;
    USE SIGNAL ;
    PORT
      LAYER M4 ;
        RECT  0 15.696 0.084 15.72 ;
    END
  END in_t[17]
  PIN in_t[18]
    DIRECTION INPUT ;
    USE SIGNAL ;
    PORT
      LAYER M4 ;
        RECT  0 15.792 0.084 15.816 ;
    END
  END in_t[18]
  PIN in_t[19]
    DIRECTION INPUT ;
    USE SIGNAL ;
    PORT
      LAYER M4 ;
        RECT  0 15.888 0.084 15.912 ;
    END
  END in_t[19]
  PIN in_t[1]
    DIRECTION INPUT ;
    USE SIGNAL ;
    PORT
      LAYER M4 ;
        RECT  0 14.16 0.084 14.184 ;
    END
  END in_t[1]
  PIN in_t[20]
    DIRECTION INPUT ;
    USE SIGNAL ;
    PORT
      LAYER M4 ;
        RECT  0 15.984 0.084 16.008 ;
    END
  END in_t[20]
  PIN in_t[21]
    DIRECTION INPUT ;
    USE SIGNAL ;
    PORT
      LAYER M4 ;
        RECT  0 16.08 0.084 16.104 ;
    END
  END in_t[21]
  PIN in_t[22]
    DIRECTION INPUT ;
    USE SIGNAL ;
    PORT
      LAYER M4 ;
        RECT  0 16.176 0.084 16.2 ;
    END
  END in_t[22]
  PIN in_t[23]
    DIRECTION INPUT ;
    USE SIGNAL ;
    PORT
      LAYER M4 ;
        RECT  0 16.272 0.084 16.296 ;
    END
  END in_t[23]
  PIN in_t[24]
    DIRECTION INPUT ;
    USE SIGNAL ;
    PORT
      LAYER M4 ;
        RECT  0 16.368 0.084 16.392 ;
    END
  END in_t[24]
  PIN in_t[25]
    DIRECTION INPUT ;
    USE SIGNAL ;
    PORT
      LAYER M4 ;
        RECT  0 16.464 0.084 16.488 ;
    END
  END in_t[25]
  PIN in_t[26]
    DIRECTION INPUT ;
    USE SIGNAL ;
    PORT
      LAYER M4 ;
        RECT  0 16.56 0.084 16.584 ;
    END
  END in_t[26]
  PIN in_t[27]
    DIRECTION INPUT ;
    USE SIGNAL ;
    PORT
      LAYER M4 ;
        RECT  0 16.656 0.084 16.68 ;
    END
  END in_t[27]
  PIN in_t[28]
    DIRECTION INPUT ;
    USE SIGNAL ;
    PORT
      LAYER M4 ;
        RECT  0 16.752 0.084 16.776 ;
    END
  END in_t[28]
  PIN in_t[29]
    DIRECTION INPUT ;
    USE SIGNAL ;
    PORT
      LAYER M4 ;
        RECT  0 16.848 0.084 16.872 ;
    END
  END in_t[29]
  PIN in_t[2]
    DIRECTION INPUT ;
    USE SIGNAL ;
    PORT
      LAYER M4 ;
        RECT  0 14.256 0.084 14.28 ;
    END
  END in_t[2]
  PIN in_t[30]
    DIRECTION INPUT ;
    USE SIGNAL ;
    PORT
      LAYER M4 ;
        RECT  0 16.944 0.084 16.968 ;
    END
  END in_t[30]
  PIN in_t[31]
    DIRECTION INPUT ;
    USE SIGNAL ;
    PORT
      LAYER M4 ;
        RECT  0 17.04 0.084 17.064 ;
    END
  END in_t[31]
  PIN in_t[32]
    DIRECTION INPUT ;
    USE SIGNAL ;
    PORT
      LAYER M4 ;
        RECT  0 17.136 0.084 17.16 ;
    END
  END in_t[32]
  PIN in_t[33]
    DIRECTION INPUT ;
    USE SIGNAL ;
    PORT
      LAYER M4 ;
        RECT  0 17.232 0.084 17.256 ;
    END
  END in_t[33]
  PIN in_t[34]
    DIRECTION INPUT ;
    USE SIGNAL ;
    PORT
      LAYER M4 ;
        RECT  0 17.328 0.084 17.352 ;
    END
  END in_t[34]
  PIN in_t[35]
    DIRECTION INPUT ;
    USE SIGNAL ;
    PORT
      LAYER M4 ;
        RECT  0 17.424 0.084 17.448 ;
    END
  END in_t[35]
  PIN in_t[36]
    DIRECTION INPUT ;
    USE SIGNAL ;
    PORT
      LAYER M4 ;
        RECT  0 17.52 0.084 17.544 ;
    END
  END in_t[36]
  PIN in_t[37]
    DIRECTION INPUT ;
    USE SIGNAL ;
    PORT
      LAYER M4 ;
        RECT  0 17.616 0.084 17.64 ;
    END
  END in_t[37]
  PIN in_t[38]
    DIRECTION INPUT ;
    USE SIGNAL ;
    PORT
      LAYER M4 ;
        RECT  0 17.712 0.084 17.736 ;
    END
  END in_t[38]
  PIN in_t[39]
    DIRECTION INPUT ;
    USE SIGNAL ;
    PORT
      LAYER M4 ;
        RECT  0 17.808 0.084 17.832 ;
    END
  END in_t[39]
  PIN in_t[3]
    DIRECTION INPUT ;
    USE SIGNAL ;
    PORT
      LAYER M4 ;
        RECT  0 14.352 0.084 14.376 ;
    END
  END in_t[3]
  PIN in_t[40]
    DIRECTION INPUT ;
    USE SIGNAL ;
    PORT
      LAYER M4 ;
        RECT  0 17.904 0.084 17.928 ;
    END
  END in_t[40]
  PIN in_t[41]
    DIRECTION INPUT ;
    USE SIGNAL ;
    PORT
      LAYER M4 ;
        RECT  0 18 0.084 18.024 ;
    END
  END in_t[41]
  PIN in_t[42]
    DIRECTION INPUT ;
    USE SIGNAL ;
    PORT
      LAYER M4 ;
        RECT  0 18.096 0.084 18.12 ;
    END
  END in_t[42]
  PIN in_t[43]
    DIRECTION INPUT ;
    USE SIGNAL ;
    PORT
      LAYER M4 ;
        RECT  0 18.192 0.084 18.216 ;
    END
  END in_t[43]
  PIN in_t[44]
    DIRECTION INPUT ;
    USE SIGNAL ;
    PORT
      LAYER M4 ;
        RECT  0 18.288 0.084 18.312 ;
    END
  END in_t[44]
  PIN in_t[45]
    DIRECTION INPUT ;
    USE SIGNAL ;
    PORT
      LAYER M4 ;
        RECT  0 18.384 0.084 18.408 ;
    END
  END in_t[45]
  PIN in_t[46]
    DIRECTION INPUT ;
    USE SIGNAL ;
    PORT
      LAYER M4 ;
        RECT  0 18.48 0.084 18.504 ;
    END
  END in_t[46]
  PIN in_t[47]
    DIRECTION INPUT ;
    USE SIGNAL ;
    PORT
      LAYER M4 ;
        RECT  0 18.576 0.084 18.6 ;
    END
  END in_t[47]
  PIN in_t[48]
    DIRECTION INPUT ;
    USE SIGNAL ;
    PORT
      LAYER M4 ;
        RECT  0 18.672 0.084 18.696 ;
    END
  END in_t[48]
  PIN in_t[49]
    DIRECTION INPUT ;
    USE SIGNAL ;
    PORT
      LAYER M4 ;
        RECT  0 18.768 0.084 18.792 ;
    END
  END in_t[49]
  PIN in_t[4]
    DIRECTION INPUT ;
    USE SIGNAL ;
    PORT
      LAYER M4 ;
        RECT  0 14.448 0.084 14.472 ;
    END
  END in_t[4]
  PIN in_t[50]
    DIRECTION INPUT ;
    USE SIGNAL ;
    PORT
      LAYER M4 ;
        RECT  0 18.864 0.084 18.888 ;
    END
  END in_t[50]
  PIN in_t[51]
    DIRECTION INPUT ;
    USE SIGNAL ;
    PORT
      LAYER M4 ;
        RECT  0 18.96 0.084 18.984 ;
    END
  END in_t[51]
  PIN in_t[52]
    DIRECTION INPUT ;
    USE SIGNAL ;
    PORT
      LAYER M4 ;
        RECT  0 19.056 0.084 19.08 ;
    END
  END in_t[52]
  PIN in_t[53]
    DIRECTION INPUT ;
    USE SIGNAL ;
    PORT
      LAYER M4 ;
        RECT  0 19.152 0.084 19.176 ;
    END
  END in_t[53]
  PIN in_t[54]
    DIRECTION INPUT ;
    USE SIGNAL ;
    PORT
      LAYER M4 ;
        RECT  0 19.248 0.084 19.272 ;
    END
  END in_t[54]
  PIN in_t[55]
    DIRECTION INPUT ;
    USE SIGNAL ;
    PORT
      LAYER M4 ;
        RECT  0 19.344 0.084 19.368 ;
    END
  END in_t[55]
  PIN in_t[56]
    DIRECTION INPUT ;
    USE SIGNAL ;
    PORT
      LAYER M4 ;
        RECT  0 19.44 0.084 19.464 ;
    END
  END in_t[56]
  PIN in_t[57]
    DIRECTION INPUT ;
    USE SIGNAL ;
    PORT
      LAYER M4 ;
        RECT  0 19.536 0.084 19.56 ;
    END
  END in_t[57]
  PIN in_t[58]
    DIRECTION INPUT ;
    USE SIGNAL ;
    PORT
      LAYER M4 ;
        RECT  0 19.632 0.084 19.656 ;
    END
  END in_t[58]
  PIN in_t[59]
    DIRECTION INPUT ;
    USE SIGNAL ;
    PORT
      LAYER M4 ;
        RECT  0 19.728 0.084 19.752 ;
    END
  END in_t[59]
  PIN in_t[5]
    DIRECTION INPUT ;
    USE SIGNAL ;
    PORT
      LAYER M4 ;
        RECT  0 14.544 0.084 14.568 ;
    END
  END in_t[5]
  PIN in_t[60]
    DIRECTION INPUT ;
    USE SIGNAL ;
    PORT
      LAYER M4 ;
        RECT  0 19.824 0.084 19.848 ;
    END
  END in_t[60]
  PIN in_t[61]
    DIRECTION INPUT ;
    USE SIGNAL ;
    PORT
      LAYER M4 ;
        RECT  0 19.92 0.084 19.944 ;
    END
  END in_t[61]
  PIN in_t[62]
    DIRECTION INPUT ;
    USE SIGNAL ;
    PORT
      LAYER M4 ;
        RECT  0 20.016 0.084 20.04 ;
    END
  END in_t[62]
  PIN in_t[63]
    DIRECTION INPUT ;
    USE SIGNAL ;
    PORT
      LAYER M4 ;
        RECT  0 20.112 0.084 20.136 ;
    END
  END in_t[63]
  PIN in_t[64]
    DIRECTION INPUT ;
    USE SIGNAL ;
    PORT
      LAYER M4 ;
        RECT  0 20.208 0.084 20.232 ;
    END
  END in_t[64]
  PIN in_t[65]
    DIRECTION INPUT ;
    USE SIGNAL ;
    PORT
      LAYER M4 ;
        RECT  0 20.304 0.084 20.328 ;
    END
  END in_t[65]
  PIN in_t[66]
    DIRECTION INPUT ;
    USE SIGNAL ;
    PORT
      LAYER M4 ;
        RECT  0 20.4 0.084 20.424 ;
    END
  END in_t[66]
  PIN in_t[67]
    DIRECTION INPUT ;
    USE SIGNAL ;
    PORT
      LAYER M4 ;
        RECT  0 20.496 0.084 20.52 ;
    END
  END in_t[67]
  PIN in_t[68]
    DIRECTION INPUT ;
    USE SIGNAL ;
    PORT
      LAYER M4 ;
        RECT  0 20.592 0.084 20.616 ;
    END
  END in_t[68]
  PIN in_t[69]
    DIRECTION INPUT ;
    USE SIGNAL ;
    PORT
      LAYER M4 ;
        RECT  0 20.688 0.084 20.712 ;
    END
  END in_t[69]
  PIN in_t[6]
    DIRECTION INPUT ;
    USE SIGNAL ;
    PORT
      LAYER M4 ;
        RECT  0 14.64 0.084 14.664 ;
    END
  END in_t[6]
  PIN in_t[70]
    DIRECTION INPUT ;
    USE SIGNAL ;
    PORT
      LAYER M4 ;
        RECT  0 20.784 0.084 20.808 ;
    END
  END in_t[70]
  PIN in_t[71]
    DIRECTION INPUT ;
    USE SIGNAL ;
    PORT
      LAYER M4 ;
        RECT  0 20.88 0.084 20.904 ;
    END
  END in_t[71]
  PIN in_t[72]
    DIRECTION INPUT ;
    USE SIGNAL ;
    PORT
      LAYER M4 ;
        RECT  0 20.976 0.084 21 ;
    END
  END in_t[72]
  PIN in_t[73]
    DIRECTION INPUT ;
    USE SIGNAL ;
    PORT
      LAYER M4 ;
        RECT  0 21.072 0.084 21.096 ;
    END
  END in_t[73]
  PIN in_t[74]
    DIRECTION INPUT ;
    USE SIGNAL ;
    PORT
      LAYER M4 ;
        RECT  0 21.168 0.084 21.192 ;
    END
  END in_t[74]
  PIN in_t[75]
    DIRECTION INPUT ;
    USE SIGNAL ;
    PORT
      LAYER M4 ;
        RECT  0 21.264 0.084 21.288 ;
    END
  END in_t[75]
  PIN in_t[76]
    DIRECTION INPUT ;
    USE SIGNAL ;
    PORT
      LAYER M4 ;
        RECT  0 21.36 0.084 21.384 ;
    END
  END in_t[76]
  PIN in_t[77]
    DIRECTION INPUT ;
    USE SIGNAL ;
    PORT
      LAYER M4 ;
        RECT  0 21.456 0.084 21.48 ;
    END
  END in_t[77]
  PIN in_t[78]
    DIRECTION INPUT ;
    USE SIGNAL ;
    PORT
      LAYER M4 ;
        RECT  0 21.552 0.084 21.576 ;
    END
  END in_t[78]
  PIN in_t[79]
    DIRECTION INPUT ;
    USE SIGNAL ;
    PORT
      LAYER M4 ;
        RECT  0 21.648 0.084 21.672 ;
    END
  END in_t[79]
  PIN in_t[7]
    DIRECTION INPUT ;
    USE SIGNAL ;
    PORT
      LAYER M4 ;
        RECT  0 14.736 0.084 14.76 ;
    END
  END in_t[7]
  PIN in_t[80]
    DIRECTION INPUT ;
    USE SIGNAL ;
    PORT
      LAYER M4 ;
        RECT  0 21.744 0.084 21.768 ;
    END
  END in_t[80]
  PIN in_t[81]
    DIRECTION INPUT ;
    USE SIGNAL ;
    PORT
      LAYER M4 ;
        RECT  0 21.84 0.084 21.864 ;
    END
  END in_t[81]
  PIN in_t[82]
    DIRECTION INPUT ;
    USE SIGNAL ;
    PORT
      LAYER M4 ;
        RECT  0 21.936 0.084 21.96 ;
    END
  END in_t[82]
  PIN in_t[83]
    DIRECTION INPUT ;
    USE SIGNAL ;
    PORT
      LAYER M4 ;
        RECT  0 22.032 0.084 22.056 ;
    END
  END in_t[83]
  PIN in_t[84]
    DIRECTION INPUT ;
    USE SIGNAL ;
    PORT
      LAYER M4 ;
        RECT  0 22.128 0.084 22.152 ;
    END
  END in_t[84]
  PIN in_t[85]
    DIRECTION INPUT ;
    USE SIGNAL ;
    PORT
      LAYER M4 ;
        RECT  0 22.224 0.084 22.248 ;
    END
  END in_t[85]
  PIN in_t[86]
    DIRECTION INPUT ;
    USE SIGNAL ;
    PORT
      LAYER M4 ;
        RECT  0 22.32 0.084 22.344 ;
    END
  END in_t[86]
  PIN in_t[87]
    DIRECTION INPUT ;
    USE SIGNAL ;
    PORT
      LAYER M4 ;
        RECT  0 22.416 0.084 22.44 ;
    END
  END in_t[87]
  PIN in_t[88]
    DIRECTION INPUT ;
    USE SIGNAL ;
    PORT
      LAYER M4 ;
        RECT  0 22.512 0.084 22.536 ;
    END
  END in_t[88]
  PIN in_t[89]
    DIRECTION INPUT ;
    USE SIGNAL ;
    PORT
      LAYER M4 ;
        RECT  0 22.608 0.084 22.632 ;
    END
  END in_t[89]
  PIN in_t[8]
    DIRECTION INPUT ;
    USE SIGNAL ;
    PORT
      LAYER M4 ;
        RECT  0 14.832 0.084 14.856 ;
    END
  END in_t[8]
  PIN in_t[90]
    DIRECTION INPUT ;
    USE SIGNAL ;
    PORT
      LAYER M4 ;
        RECT  0 22.704 0.084 22.728 ;
    END
  END in_t[90]
  PIN in_t[91]
    DIRECTION INPUT ;
    USE SIGNAL ;
    PORT
      LAYER M4 ;
        RECT  0 22.8 0.084 22.824 ;
    END
  END in_t[91]
  PIN in_t[92]
    DIRECTION INPUT ;
    USE SIGNAL ;
    PORT
      LAYER M4 ;
        RECT  0 22.896 0.084 22.92 ;
    END
  END in_t[92]
  PIN in_t[93]
    DIRECTION INPUT ;
    USE SIGNAL ;
    PORT
      LAYER M4 ;
        RECT  0 22.992 0.084 23.016 ;
    END
  END in_t[93]
  PIN in_t[94]
    DIRECTION INPUT ;
    USE SIGNAL ;
    PORT
      LAYER M4 ;
        RECT  0 23.088 0.084 23.112 ;
    END
  END in_t[94]
  PIN in_t[95]
    DIRECTION INPUT ;
    USE SIGNAL ;
    PORT
      LAYER M4 ;
        RECT  0 23.184 0.084 23.208 ;
    END
  END in_t[95]
  PIN in_t[96]
    DIRECTION INPUT ;
    USE SIGNAL ;
    PORT
      LAYER M4 ;
        RECT  0 11.76 0.084 11.784 ;
    END
  END in_t[96]
  PIN in_t[97]
    DIRECTION INPUT ;
    USE SIGNAL ;
    PORT
      LAYER M4 ;
        RECT  0 11.856 0.084 11.88 ;
    END
  END in_t[97]
  PIN in_t[98]
    DIRECTION INPUT ;
    USE SIGNAL ;
    PORT
      LAYER M4 ;
        RECT  0 11.952 0.084 11.976 ;
    END
  END in_t[98]
  PIN in_t[99]
    DIRECTION INPUT ;
    USE SIGNAL ;
    PORT
      LAYER M4 ;
        RECT  0 12.048 0.084 12.072 ;
    END
  END in_t[99]
  PIN in_t[9]
    DIRECTION INPUT ;
    USE SIGNAL ;
    PORT
      LAYER M4 ;
        RECT  0 14.928 0.084 14.952 ;
    END
  END in_t[9]
  PIN in_valid[0]
    DIRECTION INPUT ;
    USE SIGNAL ;
    PORT
      LAYER M4 ;
        RECT  0 13.296 0.084 13.32 ;
    END
  END in_valid[0]
  PIN in_valid[1]
    DIRECTION INPUT ;
    USE SIGNAL ;
    PORT
      LAYER M4 ;
        RECT  0 13.392 0.084 13.416 ;
    END
  END in_valid[1]
  PIN in_valid[2]
    DIRECTION INPUT ;
    USE SIGNAL ;
    PORT
      LAYER M4 ;
        RECT  0 13.488 0.084 13.512 ;
    END
  END in_valid[2]
  PIN in_valid[3]
    DIRECTION INPUT ;
    USE SIGNAL ;
    PORT
      LAYER M4 ;
        RECT  0 13.584 0.084 13.608 ;
    END
  END in_valid[3]
  PIN in_valid[4]
    DIRECTION INPUT ;
    USE SIGNAL ;
    PORT
      LAYER M4 ;
        RECT  0 13.68 0.084 13.704 ;
    END
  END in_valid[4]
  PIN in_valid[5]
    DIRECTION INPUT ;
    USE SIGNAL ;
    PORT
      LAYER M4 ;
        RECT  0 13.776 0.084 13.8 ;
    END
  END in_valid[5]
  PIN in_valid[6]
    DIRECTION INPUT ;
    USE SIGNAL ;
    PORT
      LAYER M4 ;
        RECT  0 13.872 0.084 13.896 ;
    END
  END in_valid[6]
  PIN in_valid[7]
    DIRECTION INPUT ;
    USE SIGNAL ;
    PORT
      LAYER M4 ;
        RECT  0 13.968 0.084 13.992 ;
    END
  END in_valid[7]
  PIN out_age[0]
    DIRECTION OUTPUT ;
    USE SIGNAL ;
    PORT
      LAYER M5 ;
        RECT  20.016 0 20.04 0.084 ;
    END
  END out_age[0]
  PIN out_age[10]
    DIRECTION OUTPUT ;
    USE SIGNAL ;
    PORT
      LAYER M5 ;
        RECT  20.976 0 21 0.084 ;
    END
  END out_age[10]
  PIN out_age[11]
    DIRECTION OUTPUT ;
    USE SIGNAL ;
    PORT
      LAYER M5 ;
        RECT  21.072 0 21.096 0.084 ;
    END
  END out_age[11]
  PIN out_age[12]
    DIRECTION OUTPUT ;
    USE SIGNAL ;
    PORT
      LAYER M5 ;
        RECT  21.168 0 21.192 0.084 ;
    END
  END out_age[12]
  PIN out_age[13]
    DIRECTION OUTPUT ;
    USE SIGNAL ;
    PORT
      LAYER M5 ;
        RECT  21.264 0 21.288 0.084 ;
    END
  END out_age[13]
  PIN out_age[14]
    DIRECTION OUTPUT ;
    USE SIGNAL ;
    PORT
      LAYER M5 ;
        RECT  21.36 0 21.384 0.084 ;
    END
  END out_age[14]
  PIN out_age[15]
    DIRECTION OUTPUT ;
    USE SIGNAL ;
    PORT
      LAYER M5 ;
        RECT  21.456 0 21.48 0.084 ;
    END
  END out_age[15]
  PIN out_age[1]
    DIRECTION OUTPUT ;
    USE SIGNAL ;
    PORT
      LAYER M5 ;
        RECT  20.112 0 20.136 0.084 ;
    END
  END out_age[1]
  PIN out_age[2]
    DIRECTION OUTPUT ;
    USE SIGNAL ;
    PORT
      LAYER M5 ;
        RECT  20.208 0 20.232 0.084 ;
    END
  END out_age[2]
  PIN out_age[3]
    DIRECTION OUTPUT ;
    USE SIGNAL ;
    PORT
      LAYER M5 ;
        RECT  20.304 0 20.328 0.084 ;
    END
  END out_age[3]
  PIN out_age[4]
    DIRECTION OUTPUT ;
    USE SIGNAL ;
    PORT
      LAYER M5 ;
        RECT  20.4 0 20.424 0.084 ;
    END
  END out_age[4]
  PIN out_age[5]
    DIRECTION OUTPUT ;
    USE SIGNAL ;
    PORT
      LAYER M5 ;
        RECT  20.496 0 20.52 0.084 ;
    END
  END out_age[5]
  PIN out_age[6]
    DIRECTION OUTPUT ;
    USE SIGNAL ;
    PORT
      LAYER M5 ;
        RECT  20.592 0 20.616 0.084 ;
    END
  END out_age[6]
  PIN out_age[7]
    DIRECTION OUTPUT ;
    USE SIGNAL ;
    PORT
      LAYER M5 ;
        RECT  20.688 0 20.712 0.084 ;
    END
  END out_age[7]
  PIN out_age[8]
    DIRECTION OUTPUT ;
    USE SIGNAL ;
    PORT
      LAYER M5 ;
        RECT  20.784 0 20.808 0.084 ;
    END
  END out_age[8]
  PIN out_age[9]
    DIRECTION OUTPUT ;
    USE SIGNAL ;
    PORT
      LAYER M5 ;
        RECT  20.88 0 20.904 0.084 ;
    END
  END out_age[9]
  PIN out_epoch[0]
    DIRECTION OUTPUT ;
    USE SIGNAL ;
    PORT
      LAYER M5 ;
        RECT  21.552 0 21.576 0.084 ;
    END
  END out_epoch[0]
  PIN out_epoch[10]
    DIRECTION OUTPUT ;
    USE SIGNAL ;
    PORT
      LAYER M5 ;
        RECT  22.512 0 22.536 0.084 ;
    END
  END out_epoch[10]
  PIN out_epoch[11]
    DIRECTION OUTPUT ;
    USE SIGNAL ;
    PORT
      LAYER M5 ;
        RECT  22.608 0 22.632 0.084 ;
    END
  END out_epoch[11]
  PIN out_epoch[12]
    DIRECTION OUTPUT ;
    USE SIGNAL ;
    PORT
      LAYER M5 ;
        RECT  22.704 0 22.728 0.084 ;
    END
  END out_epoch[12]
  PIN out_epoch[13]
    DIRECTION OUTPUT ;
    USE SIGNAL ;
    PORT
      LAYER M5 ;
        RECT  22.8 0 22.824 0.084 ;
    END
  END out_epoch[13]
  PIN out_epoch[14]
    DIRECTION OUTPUT ;
    USE SIGNAL ;
    PORT
      LAYER M5 ;
        RECT  22.896 0 22.92 0.084 ;
    END
  END out_epoch[14]
  PIN out_epoch[15]
    DIRECTION OUTPUT ;
    USE SIGNAL ;
    PORT
      LAYER M5 ;
        RECT  13.008 0 13.032 0.084 ;
    END
  END out_epoch[15]
  PIN out_epoch[1]
    DIRECTION OUTPUT ;
    USE SIGNAL ;
    PORT
      LAYER M5 ;
        RECT  21.648 0 21.672 0.084 ;
    END
  END out_epoch[1]
  PIN out_epoch[2]
    DIRECTION OUTPUT ;
    USE SIGNAL ;
    PORT
      LAYER M5 ;
        RECT  21.744 0 21.768 0.084 ;
    END
  END out_epoch[2]
  PIN out_epoch[3]
    DIRECTION OUTPUT ;
    USE SIGNAL ;
    PORT
      LAYER M5 ;
        RECT  21.84 0 21.864 0.084 ;
    END
  END out_epoch[3]
  PIN out_epoch[4]
    DIRECTION OUTPUT ;
    USE SIGNAL ;
    PORT
      LAYER M5 ;
        RECT  21.936 0 21.96 0.084 ;
    END
  END out_epoch[4]
  PIN out_epoch[5]
    DIRECTION OUTPUT ;
    USE SIGNAL ;
    PORT
      LAYER M5 ;
        RECT  22.032 0 22.056 0.084 ;
    END
  END out_epoch[5]
  PIN out_epoch[6]
    DIRECTION OUTPUT ;
    USE SIGNAL ;
    PORT
      LAYER M5 ;
        RECT  22.128 0 22.152 0.084 ;
    END
  END out_epoch[6]
  PIN out_epoch[7]
    DIRECTION OUTPUT ;
    USE SIGNAL ;
    PORT
      LAYER M5 ;
        RECT  22.224 0 22.248 0.084 ;
    END
  END out_epoch[7]
  PIN out_epoch[8]
    DIRECTION OUTPUT ;
    USE SIGNAL ;
    PORT
      LAYER M5 ;
        RECT  22.32 0 22.344 0.084 ;
    END
  END out_epoch[8]
  PIN out_epoch[9]
    DIRECTION OUTPUT ;
    USE SIGNAL ;
    PORT
      LAYER M5 ;
        RECT  22.416 0 22.44 0.084 ;
    END
  END out_epoch[9]
  PIN pair_id
    DIRECTION INPUT ;
    USE SIGNAL ;
    PORT
      LAYER M5 ;
        RECT  13.104 0 13.128 0.084 ;
    END
  END pair_id
  PIN req_t[0]
    DIRECTION OUTPUT ;
    USE SIGNAL ;
    PORT
      LAYER M4 ;
        RECT  43.116 39.12 43.2 39.144 ;
    END
  END req_t[0]
  PIN req_t[100]
    DIRECTION OUTPUT ;
    USE SIGNAL ;
    PORT
      LAYER M4 ;
        RECT  43.116 32.592 43.2 32.616 ;
    END
  END req_t[100]
  PIN req_t[101]
    DIRECTION OUTPUT ;
    USE SIGNAL ;
    PORT
      LAYER M4 ;
        RECT  43.116 32.688 43.2 32.712 ;
    END
  END req_t[101]
  PIN req_t[102]
    DIRECTION OUTPUT ;
    USE SIGNAL ;
    PORT
      LAYER M4 ;
        RECT  43.116 32.784 43.2 32.808 ;
    END
  END req_t[102]
  PIN req_t[103]
    DIRECTION OUTPUT ;
    USE SIGNAL ;
    PORT
      LAYER M4 ;
        RECT  43.116 32.88 43.2 32.904 ;
    END
  END req_t[103]
  PIN req_t[104]
    DIRECTION OUTPUT ;
    USE SIGNAL ;
    PORT
      LAYER M4 ;
        RECT  43.116 32.976 43.2 33 ;
    END
  END req_t[104]
  PIN req_t[105]
    DIRECTION OUTPUT ;
    USE SIGNAL ;
    PORT
      LAYER M4 ;
        RECT  43.116 33.072 43.2 33.096 ;
    END
  END req_t[105]
  PIN req_t[106]
    DIRECTION OUTPUT ;
    USE SIGNAL ;
    PORT
      LAYER M4 ;
        RECT  43.116 33.168 43.2 33.192 ;
    END
  END req_t[106]
  PIN req_t[107]
    DIRECTION OUTPUT ;
    USE SIGNAL ;
    PORT
      LAYER M4 ;
        RECT  43.116 33.264 43.2 33.288 ;
    END
  END req_t[107]
  PIN req_t[108]
    DIRECTION OUTPUT ;
    USE SIGNAL ;
    PORT
      LAYER M4 ;
        RECT  43.116 33.36 43.2 33.384 ;
    END
  END req_t[108]
  PIN req_t[109]
    DIRECTION OUTPUT ;
    USE SIGNAL ;
    PORT
      LAYER M4 ;
        RECT  43.116 33.456 43.2 33.48 ;
    END
  END req_t[109]
  PIN req_t[10]
    DIRECTION OUTPUT ;
    USE SIGNAL ;
    PORT
      LAYER M4 ;
        RECT  43.116 40.08 43.2 40.104 ;
    END
  END req_t[10]
  PIN req_t[110]
    DIRECTION OUTPUT ;
    USE SIGNAL ;
    PORT
      LAYER M4 ;
        RECT  43.116 33.552 43.2 33.576 ;
    END
  END req_t[110]
  PIN req_t[111]
    DIRECTION OUTPUT ;
    USE SIGNAL ;
    PORT
      LAYER M4 ;
        RECT  43.116 33.648 43.2 33.672 ;
    END
  END req_t[111]
  PIN req_t[11]
    DIRECTION OUTPUT ;
    USE SIGNAL ;
    PORT
      LAYER M4 ;
        RECT  43.116 40.176 43.2 40.2 ;
    END
  END req_t[11]
  PIN req_t[12]
    DIRECTION OUTPUT ;
    USE SIGNAL ;
    PORT
      LAYER M4 ;
        RECT  43.116 40.272 43.2 40.296 ;
    END
  END req_t[12]
  PIN req_t[13]
    DIRECTION OUTPUT ;
    USE SIGNAL ;
    PORT
      LAYER M4 ;
        RECT  43.116 40.368 43.2 40.392 ;
    END
  END req_t[13]
  PIN req_t[14]
    DIRECTION OUTPUT ;
    USE SIGNAL ;
    PORT
      LAYER M4 ;
        RECT  43.116 40.464 43.2 40.488 ;
    END
  END req_t[14]
  PIN req_t[15]
    DIRECTION OUTPUT ;
    USE SIGNAL ;
    PORT
      LAYER M4 ;
        RECT  43.116 40.56 43.2 40.584 ;
    END
  END req_t[15]
  PIN req_t[16]
    DIRECTION OUTPUT ;
    USE SIGNAL ;
    PORT
      LAYER M4 ;
        RECT  43.116 40.656 43.2 40.68 ;
    END
  END req_t[16]
  PIN req_t[17]
    DIRECTION OUTPUT ;
    USE SIGNAL ;
    PORT
      LAYER M4 ;
        RECT  43.116 40.752 43.2 40.776 ;
    END
  END req_t[17]
  PIN req_t[18]
    DIRECTION OUTPUT ;
    USE SIGNAL ;
    PORT
      LAYER M4 ;
        RECT  43.116 40.848 43.2 40.872 ;
    END
  END req_t[18]
  PIN req_t[19]
    DIRECTION OUTPUT ;
    USE SIGNAL ;
    PORT
      LAYER M4 ;
        RECT  43.116 40.944 43.2 40.968 ;
    END
  END req_t[19]
  PIN req_t[1]
    DIRECTION OUTPUT ;
    USE SIGNAL ;
    PORT
      LAYER M4 ;
        RECT  43.116 39.216 43.2 39.24 ;
    END
  END req_t[1]
  PIN req_t[20]
    DIRECTION OUTPUT ;
    USE SIGNAL ;
    PORT
      LAYER M4 ;
        RECT  43.116 41.04 43.2 41.064 ;
    END
  END req_t[20]
  PIN req_t[21]
    DIRECTION OUTPUT ;
    USE SIGNAL ;
    PORT
      LAYER M4 ;
        RECT  43.116 41.136 43.2 41.16 ;
    END
  END req_t[21]
  PIN req_t[22]
    DIRECTION OUTPUT ;
    USE SIGNAL ;
    PORT
      LAYER M4 ;
        RECT  43.116 41.232 43.2 41.256 ;
    END
  END req_t[22]
  PIN req_t[23]
    DIRECTION OUTPUT ;
    USE SIGNAL ;
    PORT
      LAYER M4 ;
        RECT  43.116 41.328 43.2 41.352 ;
    END
  END req_t[23]
  PIN req_t[24]
    DIRECTION OUTPUT ;
    USE SIGNAL ;
    PORT
      LAYER M4 ;
        RECT  43.116 41.424 43.2 41.448 ;
    END
  END req_t[24]
  PIN req_t[25]
    DIRECTION OUTPUT ;
    USE SIGNAL ;
    PORT
      LAYER M4 ;
        RECT  43.116 41.52 43.2 41.544 ;
    END
  END req_t[25]
  PIN req_t[26]
    DIRECTION OUTPUT ;
    USE SIGNAL ;
    PORT
      LAYER M4 ;
        RECT  43.116 41.616 43.2 41.64 ;
    END
  END req_t[26]
  PIN req_t[27]
    DIRECTION OUTPUT ;
    USE SIGNAL ;
    PORT
      LAYER M4 ;
        RECT  43.116 41.712 43.2 41.736 ;
    END
  END req_t[27]
  PIN req_t[28]
    DIRECTION OUTPUT ;
    USE SIGNAL ;
    PORT
      LAYER M4 ;
        RECT  43.116 41.808 43.2 41.832 ;
    END
  END req_t[28]
  PIN req_t[29]
    DIRECTION OUTPUT ;
    USE SIGNAL ;
    PORT
      LAYER M4 ;
        RECT  43.116 41.904 43.2 41.928 ;
    END
  END req_t[29]
  PIN req_t[2]
    DIRECTION OUTPUT ;
    USE SIGNAL ;
    PORT
      LAYER M4 ;
        RECT  43.116 39.312 43.2 39.336 ;
    END
  END req_t[2]
  PIN req_t[30]
    DIRECTION OUTPUT ;
    USE SIGNAL ;
    PORT
      LAYER M4 ;
        RECT  43.116 42 43.2 42.024 ;
    END
  END req_t[30]
  PIN req_t[31]
    DIRECTION OUTPUT ;
    USE SIGNAL ;
    PORT
      LAYER M4 ;
        RECT  43.116 42.096 43.2 42.12 ;
    END
  END req_t[31]
  PIN req_t[32]
    DIRECTION OUTPUT ;
    USE SIGNAL ;
    PORT
      LAYER M4 ;
        RECT  43.116 35.28 43.2 35.304 ;
    END
  END req_t[32]
  PIN req_t[33]
    DIRECTION OUTPUT ;
    USE SIGNAL ;
    PORT
      LAYER M4 ;
        RECT  43.116 35.376 43.2 35.4 ;
    END
  END req_t[33]
  PIN req_t[34]
    DIRECTION OUTPUT ;
    USE SIGNAL ;
    PORT
      LAYER M4 ;
        RECT  43.116 35.472 43.2 35.496 ;
    END
  END req_t[34]
  PIN req_t[35]
    DIRECTION OUTPUT ;
    USE SIGNAL ;
    PORT
      LAYER M4 ;
        RECT  43.116 35.568 43.2 35.592 ;
    END
  END req_t[35]
  PIN req_t[36]
    DIRECTION OUTPUT ;
    USE SIGNAL ;
    PORT
      LAYER M4 ;
        RECT  43.116 35.664 43.2 35.688 ;
    END
  END req_t[36]
  PIN req_t[37]
    DIRECTION OUTPUT ;
    USE SIGNAL ;
    PORT
      LAYER M4 ;
        RECT  43.116 35.76 43.2 35.784 ;
    END
  END req_t[37]
  PIN req_t[38]
    DIRECTION OUTPUT ;
    USE SIGNAL ;
    PORT
      LAYER M4 ;
        RECT  43.116 35.856 43.2 35.88 ;
    END
  END req_t[38]
  PIN req_t[39]
    DIRECTION OUTPUT ;
    USE SIGNAL ;
    PORT
      LAYER M4 ;
        RECT  43.116 35.952 43.2 35.976 ;
    END
  END req_t[39]
  PIN req_t[3]
    DIRECTION OUTPUT ;
    USE SIGNAL ;
    PORT
      LAYER M4 ;
        RECT  43.116 39.408 43.2 39.432 ;
    END
  END req_t[3]
  PIN req_t[40]
    DIRECTION OUTPUT ;
    USE SIGNAL ;
    PORT
      LAYER M4 ;
        RECT  43.116 36.048 43.2 36.072 ;
    END
  END req_t[40]
  PIN req_t[41]
    DIRECTION OUTPUT ;
    USE SIGNAL ;
    PORT
      LAYER M4 ;
        RECT  43.116 36.144 43.2 36.168 ;
    END
  END req_t[41]
  PIN req_t[42]
    DIRECTION OUTPUT ;
    USE SIGNAL ;
    PORT
      LAYER M4 ;
        RECT  43.116 36.24 43.2 36.264 ;
    END
  END req_t[42]
  PIN req_t[43]
    DIRECTION OUTPUT ;
    USE SIGNAL ;
    PORT
      LAYER M4 ;
        RECT  43.116 36.336 43.2 36.36 ;
    END
  END req_t[43]
  PIN req_t[44]
    DIRECTION OUTPUT ;
    USE SIGNAL ;
    PORT
      LAYER M4 ;
        RECT  43.116 36.432 43.2 36.456 ;
    END
  END req_t[44]
  PIN req_t[45]
    DIRECTION OUTPUT ;
    USE SIGNAL ;
    PORT
      LAYER M4 ;
        RECT  43.116 36.528 43.2 36.552 ;
    END
  END req_t[45]
  PIN req_t[46]
    DIRECTION OUTPUT ;
    USE SIGNAL ;
    PORT
      LAYER M4 ;
        RECT  43.116 36.624 43.2 36.648 ;
    END
  END req_t[46]
  PIN req_t[47]
    DIRECTION OUTPUT ;
    USE SIGNAL ;
    PORT
      LAYER M4 ;
        RECT  43.116 36.72 43.2 36.744 ;
    END
  END req_t[47]
  PIN req_t[48]
    DIRECTION OUTPUT ;
    USE SIGNAL ;
    PORT
      LAYER M4 ;
        RECT  43.116 36.816 43.2 36.84 ;
    END
  END req_t[48]
  PIN req_t[49]
    DIRECTION OUTPUT ;
    USE SIGNAL ;
    PORT
      LAYER M4 ;
        RECT  43.116 36.912 43.2 36.936 ;
    END
  END req_t[49]
  PIN req_t[4]
    DIRECTION OUTPUT ;
    USE SIGNAL ;
    PORT
      LAYER M4 ;
        RECT  43.116 39.504 43.2 39.528 ;
    END
  END req_t[4]
  PIN req_t[50]
    DIRECTION OUTPUT ;
    USE SIGNAL ;
    PORT
      LAYER M4 ;
        RECT  43.116 37.008 43.2 37.032 ;
    END
  END req_t[50]
  PIN req_t[51]
    DIRECTION OUTPUT ;
    USE SIGNAL ;
    PORT
      LAYER M4 ;
        RECT  43.116 37.104 43.2 37.128 ;
    END
  END req_t[51]
  PIN req_t[52]
    DIRECTION OUTPUT ;
    USE SIGNAL ;
    PORT
      LAYER M4 ;
        RECT  43.116 37.2 43.2 37.224 ;
    END
  END req_t[52]
  PIN req_t[53]
    DIRECTION OUTPUT ;
    USE SIGNAL ;
    PORT
      LAYER M4 ;
        RECT  43.116 37.296 43.2 37.32 ;
    END
  END req_t[53]
  PIN req_t[54]
    DIRECTION OUTPUT ;
    USE SIGNAL ;
    PORT
      LAYER M4 ;
        RECT  43.116 37.392 43.2 37.416 ;
    END
  END req_t[54]
  PIN req_t[55]
    DIRECTION OUTPUT ;
    USE SIGNAL ;
    PORT
      LAYER M4 ;
        RECT  43.116 37.488 43.2 37.512 ;
    END
  END req_t[55]
  PIN req_t[56]
    DIRECTION OUTPUT ;
    USE SIGNAL ;
    PORT
      LAYER M4 ;
        RECT  43.116 37.584 43.2 37.608 ;
    END
  END req_t[56]
  PIN req_t[57]
    DIRECTION OUTPUT ;
    USE SIGNAL ;
    PORT
      LAYER M4 ;
        RECT  43.116 37.68 43.2 37.704 ;
    END
  END req_t[57]
  PIN req_t[58]
    DIRECTION OUTPUT ;
    USE SIGNAL ;
    PORT
      LAYER M4 ;
        RECT  43.116 37.776 43.2 37.8 ;
    END
  END req_t[58]
  PIN req_t[59]
    DIRECTION OUTPUT ;
    USE SIGNAL ;
    PORT
      LAYER M4 ;
        RECT  43.116 37.872 43.2 37.896 ;
    END
  END req_t[59]
  PIN req_t[5]
    DIRECTION OUTPUT ;
    USE SIGNAL ;
    PORT
      LAYER M4 ;
        RECT  43.116 39.6 43.2 39.624 ;
    END
  END req_t[5]
  PIN req_t[60]
    DIRECTION OUTPUT ;
    USE SIGNAL ;
    PORT
      LAYER M4 ;
        RECT  43.116 37.968 43.2 37.992 ;
    END
  END req_t[60]
  PIN req_t[61]
    DIRECTION OUTPUT ;
    USE SIGNAL ;
    PORT
      LAYER M4 ;
        RECT  43.116 38.064 43.2 38.088 ;
    END
  END req_t[61]
  PIN req_t[62]
    DIRECTION OUTPUT ;
    USE SIGNAL ;
    PORT
      LAYER M4 ;
        RECT  43.116 38.16 43.2 38.184 ;
    END
  END req_t[62]
  PIN req_t[63]
    DIRECTION OUTPUT ;
    USE SIGNAL ;
    PORT
      LAYER M4 ;
        RECT  43.116 38.256 43.2 38.28 ;
    END
  END req_t[63]
  PIN req_t[64]
    DIRECTION OUTPUT ;
    USE SIGNAL ;
    PORT
      LAYER M4 ;
        RECT  43.116 29.136 43.2 29.16 ;
    END
  END req_t[64]
  PIN req_t[65]
    DIRECTION OUTPUT ;
    USE SIGNAL ;
    PORT
      LAYER M4 ;
        RECT  43.116 29.232 43.2 29.256 ;
    END
  END req_t[65]
  PIN req_t[66]
    DIRECTION OUTPUT ;
    USE SIGNAL ;
    PORT
      LAYER M4 ;
        RECT  43.116 29.328 43.2 29.352 ;
    END
  END req_t[66]
  PIN req_t[67]
    DIRECTION OUTPUT ;
    USE SIGNAL ;
    PORT
      LAYER M4 ;
        RECT  43.116 29.424 43.2 29.448 ;
    END
  END req_t[67]
  PIN req_t[68]
    DIRECTION OUTPUT ;
    USE SIGNAL ;
    PORT
      LAYER M4 ;
        RECT  43.116 29.52 43.2 29.544 ;
    END
  END req_t[68]
  PIN req_t[69]
    DIRECTION OUTPUT ;
    USE SIGNAL ;
    PORT
      LAYER M4 ;
        RECT  43.116 29.616 43.2 29.64 ;
    END
  END req_t[69]
  PIN req_t[6]
    DIRECTION OUTPUT ;
    USE SIGNAL ;
    PORT
      LAYER M4 ;
        RECT  43.116 39.696 43.2 39.72 ;
    END
  END req_t[6]
  PIN req_t[70]
    DIRECTION OUTPUT ;
    USE SIGNAL ;
    PORT
      LAYER M4 ;
        RECT  43.116 29.712 43.2 29.736 ;
    END
  END req_t[70]
  PIN req_t[71]
    DIRECTION OUTPUT ;
    USE SIGNAL ;
    PORT
      LAYER M4 ;
        RECT  43.116 29.808 43.2 29.832 ;
    END
  END req_t[71]
  PIN req_t[72]
    DIRECTION OUTPUT ;
    USE SIGNAL ;
    PORT
      LAYER M4 ;
        RECT  43.116 29.904 43.2 29.928 ;
    END
  END req_t[72]
  PIN req_t[73]
    DIRECTION OUTPUT ;
    USE SIGNAL ;
    PORT
      LAYER M4 ;
        RECT  43.116 30 43.2 30.024 ;
    END
  END req_t[73]
  PIN req_t[74]
    DIRECTION OUTPUT ;
    USE SIGNAL ;
    PORT
      LAYER M4 ;
        RECT  43.116 30.096 43.2 30.12 ;
    END
  END req_t[74]
  PIN req_t[75]
    DIRECTION OUTPUT ;
    USE SIGNAL ;
    PORT
      LAYER M4 ;
        RECT  43.116 30.192 43.2 30.216 ;
    END
  END req_t[75]
  PIN req_t[76]
    DIRECTION OUTPUT ;
    USE SIGNAL ;
    PORT
      LAYER M4 ;
        RECT  43.116 30.288 43.2 30.312 ;
    END
  END req_t[76]
  PIN req_t[77]
    DIRECTION OUTPUT ;
    USE SIGNAL ;
    PORT
      LAYER M4 ;
        RECT  43.116 30.384 43.2 30.408 ;
    END
  END req_t[77]
  PIN req_t[78]
    DIRECTION OUTPUT ;
    USE SIGNAL ;
    PORT
      LAYER M4 ;
        RECT  43.116 30.48 43.2 30.504 ;
    END
  END req_t[78]
  PIN req_t[79]
    DIRECTION OUTPUT ;
    USE SIGNAL ;
    PORT
      LAYER M4 ;
        RECT  43.116 30.576 43.2 30.6 ;
    END
  END req_t[79]
  PIN req_t[7]
    DIRECTION OUTPUT ;
    USE SIGNAL ;
    PORT
      LAYER M4 ;
        RECT  43.116 39.792 43.2 39.816 ;
    END
  END req_t[7]
  PIN req_t[80]
    DIRECTION OUTPUT ;
    USE SIGNAL ;
    PORT
      LAYER M4 ;
        RECT  43.116 30.672 43.2 30.696 ;
    END
  END req_t[80]
  PIN req_t[81]
    DIRECTION OUTPUT ;
    USE SIGNAL ;
    PORT
      LAYER M4 ;
        RECT  43.116 30.768 43.2 30.792 ;
    END
  END req_t[81]
  PIN req_t[82]
    DIRECTION OUTPUT ;
    USE SIGNAL ;
    PORT
      LAYER M4 ;
        RECT  43.116 30.864 43.2 30.888 ;
    END
  END req_t[82]
  PIN req_t[83]
    DIRECTION OUTPUT ;
    USE SIGNAL ;
    PORT
      LAYER M4 ;
        RECT  43.116 30.96 43.2 30.984 ;
    END
  END req_t[83]
  PIN req_t[84]
    DIRECTION OUTPUT ;
    USE SIGNAL ;
    PORT
      LAYER M4 ;
        RECT  43.116 31.056 43.2 31.08 ;
    END
  END req_t[84]
  PIN req_t[85]
    DIRECTION OUTPUT ;
    USE SIGNAL ;
    PORT
      LAYER M4 ;
        RECT  43.116 31.152 43.2 31.176 ;
    END
  END req_t[85]
  PIN req_t[86]
    DIRECTION OUTPUT ;
    USE SIGNAL ;
    PORT
      LAYER M4 ;
        RECT  43.116 31.248 43.2 31.272 ;
    END
  END req_t[86]
  PIN req_t[87]
    DIRECTION OUTPUT ;
    USE SIGNAL ;
    PORT
      LAYER M4 ;
        RECT  43.116 31.344 43.2 31.368 ;
    END
  END req_t[87]
  PIN req_t[88]
    DIRECTION OUTPUT ;
    USE SIGNAL ;
    PORT
      LAYER M4 ;
        RECT  43.116 31.44 43.2 31.464 ;
    END
  END req_t[88]
  PIN req_t[89]
    DIRECTION OUTPUT ;
    USE SIGNAL ;
    PORT
      LAYER M4 ;
        RECT  43.116 31.536 43.2 31.56 ;
    END
  END req_t[89]
  PIN req_t[8]
    DIRECTION OUTPUT ;
    USE SIGNAL ;
    PORT
      LAYER M4 ;
        RECT  43.116 39.888 43.2 39.912 ;
    END
  END req_t[8]
  PIN req_t[90]
    DIRECTION OUTPUT ;
    USE SIGNAL ;
    PORT
      LAYER M4 ;
        RECT  43.116 31.632 43.2 31.656 ;
    END
  END req_t[90]
  PIN req_t[91]
    DIRECTION OUTPUT ;
    USE SIGNAL ;
    PORT
      LAYER M4 ;
        RECT  43.116 31.728 43.2 31.752 ;
    END
  END req_t[91]
  PIN req_t[92]
    DIRECTION OUTPUT ;
    USE SIGNAL ;
    PORT
      LAYER M4 ;
        RECT  43.116 31.824 43.2 31.848 ;
    END
  END req_t[92]
  PIN req_t[93]
    DIRECTION OUTPUT ;
    USE SIGNAL ;
    PORT
      LAYER M4 ;
        RECT  43.116 31.92 43.2 31.944 ;
    END
  END req_t[93]
  PIN req_t[94]
    DIRECTION OUTPUT ;
    USE SIGNAL ;
    PORT
      LAYER M4 ;
        RECT  43.116 32.016 43.2 32.04 ;
    END
  END req_t[94]
  PIN req_t[95]
    DIRECTION OUTPUT ;
    USE SIGNAL ;
    PORT
      LAYER M4 ;
        RECT  43.116 32.112 43.2 32.136 ;
    END
  END req_t[95]
  PIN req_t[96]
    DIRECTION OUTPUT ;
    USE SIGNAL ;
    PORT
      LAYER M4 ;
        RECT  43.116 32.208 43.2 32.232 ;
    END
  END req_t[96]
  PIN req_t[97]
    DIRECTION OUTPUT ;
    USE SIGNAL ;
    PORT
      LAYER M4 ;
        RECT  43.116 32.304 43.2 32.328 ;
    END
  END req_t[97]
  PIN req_t[98]
    DIRECTION OUTPUT ;
    USE SIGNAL ;
    PORT
      LAYER M4 ;
        RECT  43.116 32.4 43.2 32.424 ;
    END
  END req_t[98]
  PIN req_t[99]
    DIRECTION OUTPUT ;
    USE SIGNAL ;
    PORT
      LAYER M4 ;
        RECT  43.116 32.496 43.2 32.52 ;
    END
  END req_t[99]
  PIN req_t[9]
    DIRECTION OUTPUT ;
    USE SIGNAL ;
    PORT
      LAYER M4 ;
        RECT  43.116 39.984 43.2 40.008 ;
    END
  END req_t[9]
  PIN req_valid[0]
    DIRECTION OUTPUT ;
    USE SIGNAL ;
    PORT
      LAYER M4 ;
        RECT  43.116 33.744 43.2 33.768 ;
    END
  END req_valid[0]
  PIN req_valid[1]
    DIRECTION OUTPUT ;
    USE SIGNAL ;
    PORT
      LAYER M4 ;
        RECT  43.116 33.84 43.2 33.864 ;
    END
  END req_valid[1]
  PIN req_valid[2]
    DIRECTION OUTPUT ;
    USE SIGNAL ;
    PORT
      LAYER M4 ;
        RECT  43.116 33.936 43.2 33.96 ;
    END
  END req_valid[2]
  PIN req_valid[3]
    DIRECTION OUTPUT ;
    USE SIGNAL ;
    PORT
      LAYER M4 ;
        RECT  43.116 34.032 43.2 34.056 ;
    END
  END req_valid[3]
  PIN req_valid[4]
    DIRECTION OUTPUT ;
    USE SIGNAL ;
    PORT
      LAYER M4 ;
        RECT  43.116 34.128 43.2 34.152 ;
    END
  END req_valid[4]
  PIN req_valid[5]
    DIRECTION OUTPUT ;
    USE SIGNAL ;
    PORT
      LAYER M4 ;
        RECT  43.116 34.224 43.2 34.248 ;
    END
  END req_valid[5]
  PIN req_valid[6]
    DIRECTION OUTPUT ;
    USE SIGNAL ;
    PORT
      LAYER M4 ;
        RECT  43.116 34.32 43.2 34.344 ;
    END
  END req_valid[6]
  PIN req_valid[7]
    DIRECTION OUTPUT ;
    USE SIGNAL ;
    PORT
      LAYER M4 ;
        RECT  43.116 34.416 43.2 34.44 ;
    END
  END req_valid[7]
  PIN rst_n
    DIRECTION INPUT ;
    USE SIGNAL ;
    PORT
      LAYER M5 ;
        RECT  13.2 0 13.224 0.084 ;
    END
  END rst_n
  PIN start
    DIRECTION INPUT ;
    USE SIGNAL ;
    PORT
      LAYER M5 ;
        RECT  13.296 0 13.32 0.084 ;
    END
  END start
  PIN VDD
    DIRECTION INOUT ;
    USE POWER ;
    PORT
      LAYER M5 ;
        RECT  40.392 2.151 40.512 41.049 ;
        RECT  34.992 2.151 35.112 41.049 ;
        RECT  29.592 2.151 29.712 41.049 ;
        RECT  24.192 2.151 24.312 41.049 ;
        RECT  18.792 2.151 18.912 41.049 ;
        RECT  13.392 2.151 13.512 41.049 ;
        RECT  7.992 2.151 8.112 41.049 ;
        RECT  2.592 2.151 2.712 41.049 ;
    END
  END VDD
  PIN VSS
    DIRECTION INOUT ;
    USE GROUND ;
    PORT
      LAYER M5 ;
        RECT  40.2 2.137 40.32 41.063 ;
        RECT  34.8 2.137 34.92 41.063 ;
        RECT  29.4 2.137 29.52 41.063 ;
        RECT  24 2.137 24.12 41.063 ;
        RECT  18.6 2.137 18.72 41.063 ;
        RECT  13.2 2.137 13.32 41.063 ;
        RECT  7.8 2.137 7.92 41.063 ;
        RECT  2.4 2.137 2.52 41.063 ;
    END
  END VSS
  OBS
    LAYER RVTN ;
     RECT  2.16 2.16 41.04 2.295 ;
     RECT  2.16 2.565 41.04 2.835 ;
     RECT  2.16 3.105 41.04 3.375 ;
     RECT  2.16 3.645 41.04 3.915 ;
     RECT  2.16 4.185 41.04 4.455 ;
     RECT  2.16 4.725 41.04 4.995 ;
     RECT  2.16 5.265 41.04 5.535 ;
     RECT  2.16 5.805 41.04 6.075 ;
     RECT  2.16 6.345 41.04 6.615 ;
     RECT  2.16 6.885 41.04 7.155 ;
     RECT  2.16 7.425 41.04 7.695 ;
     RECT  2.16 7.965 41.04 8.235 ;
     RECT  2.16 8.505 41.04 8.775 ;
     RECT  2.16 9.045 41.04 9.315 ;
     RECT  2.16 9.585 41.04 9.855 ;
     RECT  2.16 10.125 41.04 10.395 ;
     RECT  2.16 10.665 41.04 10.935 ;
     RECT  2.16 11.205 41.04 11.475 ;
     RECT  2.16 11.745 41.04 12.015 ;
     RECT  2.16 12.285 41.04 12.555 ;
     RECT  2.16 12.825 41.04 13.095 ;
     RECT  2.16 13.365 41.04 13.635 ;
     RECT  2.16 13.905 41.04 14.175 ;
     RECT  2.16 14.445 41.04 14.715 ;
     RECT  2.16 14.985 41.04 15.255 ;
     RECT  2.16 15.525 41.04 15.795 ;
     RECT  2.16 16.065 41.04 16.335 ;
     RECT  2.16 16.605 41.04 16.875 ;
     RECT  2.16 17.145 41.04 17.415 ;
     RECT  2.16 17.685 41.04 17.955 ;
     RECT  2.16 18.225 41.04 18.495 ;
     RECT  2.16 18.765 41.04 19.035 ;
     RECT  2.16 19.305 41.04 19.575 ;
     RECT  2.16 19.845 41.04 20.115 ;
     RECT  2.16 20.385 41.04 20.655 ;
     RECT  2.16 20.925 41.04 21.195 ;
     RECT  2.16 21.465 41.04 21.735 ;
     RECT  2.16 22.005 41.04 22.275 ;
     RECT  2.16 22.545 41.04 22.815 ;
     RECT  2.16 23.085 41.04 23.355 ;
     RECT  2.16 23.625 41.04 23.895 ;
     RECT  2.16 24.165 41.04 24.435 ;
     RECT  2.16 24.705 41.04 24.975 ;
     RECT  2.16 25.245 41.04 25.515 ;
     RECT  2.16 25.785 41.04 26.055 ;
     RECT  2.16 26.325 41.04 26.595 ;
     RECT  2.16 26.865 41.04 27.135 ;
     RECT  2.16 27.405 41.04 27.675 ;
     RECT  2.16 27.945 41.04 28.215 ;
     RECT  2.16 28.485 41.04 28.755 ;
     RECT  2.16 29.025 41.04 29.295 ;
     RECT  2.16 29.565 41.04 29.835 ;
     RECT  2.16 30.105 41.04 30.375 ;
     RECT  2.16 30.645 41.04 30.915 ;
     RECT  2.16 31.185 41.04 31.455 ;
     RECT  2.16 31.725 41.04 31.995 ;
     RECT  2.16 32.265 41.04 32.535 ;
     RECT  2.16 32.805 41.04 33.075 ;
     RECT  2.16 33.345 41.04 33.615 ;
     RECT  2.16 33.885 41.04 34.155 ;
     RECT  2.16 34.425 41.04 34.695 ;
     RECT  2.16 34.965 41.04 35.235 ;
     RECT  2.16 35.505 41.04 35.775 ;
     RECT  2.16 36.045 41.04 36.315 ;
     RECT  2.16 36.585 41.04 36.855 ;
     RECT  2.16 37.125 41.04 37.395 ;
     RECT  2.16 37.665 41.04 37.935 ;
     RECT  2.16 38.205 41.04 38.475 ;
     RECT  2.16 38.745 41.04 39.015 ;
     RECT  2.16 39.285 41.04 39.555 ;
     RECT  2.16 39.825 41.04 40.095 ;
     RECT  2.16 40.365 41.04 40.635 ;
     RECT  2.16 40.905 41.04 41.04 ;
    LAYER RVTP ;
     RECT  2.16 2.295 41.04 2.565 ;
     RECT  2.16 2.835 41.04 3.105 ;
     RECT  2.16 3.375 41.04 3.645 ;
     RECT  2.16 3.915 41.04 4.185 ;
     RECT  2.16 4.455 41.04 4.725 ;
     RECT  2.16 4.995 41.04 5.265 ;
     RECT  2.16 5.535 41.04 5.805 ;
     RECT  2.16 6.075 41.04 6.345 ;
     RECT  2.16 6.615 41.04 6.885 ;
     RECT  2.16 7.155 41.04 7.425 ;
     RECT  2.16 7.695 41.04 7.965 ;
     RECT  2.16 8.235 41.04 8.505 ;
     RECT  2.16 8.775 41.04 9.045 ;
     RECT  2.16 9.315 41.04 9.585 ;
     RECT  2.16 9.855 41.04 10.125 ;
     RECT  2.16 10.395 41.04 10.665 ;
     RECT  2.16 10.935 41.04 11.205 ;
     RECT  2.16 11.475 41.04 11.745 ;
     RECT  2.16 12.015 41.04 12.285 ;
     RECT  2.16 12.555 41.04 12.825 ;
     RECT  2.16 13.095 41.04 13.365 ;
     RECT  2.16 13.635 41.04 13.905 ;
     RECT  2.16 14.175 41.04 14.445 ;
     RECT  2.16 14.715 41.04 14.985 ;
     RECT  2.16 15.255 41.04 15.525 ;
     RECT  2.16 15.795 41.04 16.065 ;
     RECT  2.16 16.335 41.04 16.605 ;
     RECT  2.16 16.875 41.04 17.145 ;
     RECT  2.16 17.415 41.04 17.685 ;
     RECT  2.16 17.955 41.04 18.225 ;
     RECT  2.16 18.495 41.04 18.765 ;
     RECT  2.16 19.035 41.04 19.305 ;
     RECT  2.16 19.575 41.04 19.845 ;
     RECT  2.16 20.115 41.04 20.385 ;
     RECT  2.16 20.655 41.04 20.925 ;
     RECT  2.16 21.195 41.04 21.465 ;
     RECT  2.16 21.735 41.04 22.005 ;
     RECT  2.16 22.275 41.04 22.545 ;
     RECT  2.16 22.815 41.04 23.085 ;
     RECT  2.16 23.355 41.04 23.625 ;
     RECT  2.16 23.895 41.04 24.165 ;
     RECT  2.16 24.435 41.04 24.705 ;
     RECT  2.16 24.975 41.04 25.245 ;
     RECT  2.16 25.515 41.04 25.785 ;
     RECT  2.16 26.055 41.04 26.325 ;
     RECT  2.16 26.595 41.04 26.865 ;
     RECT  2.16 27.135 41.04 27.405 ;
     RECT  2.16 27.675 41.04 27.945 ;
     RECT  2.16 28.215 41.04 28.485 ;
     RECT  2.16 28.755 41.04 29.025 ;
     RECT  2.16 29.295 41.04 29.565 ;
     RECT  2.16 29.835 41.04 30.105 ;
     RECT  2.16 30.375 41.04 30.645 ;
     RECT  2.16 30.915 41.04 31.185 ;
     RECT  2.16 31.455 41.04 31.725 ;
     RECT  2.16 31.995 41.04 32.265 ;
     RECT  2.16 32.535 41.04 32.805 ;
     RECT  2.16 33.075 41.04 33.345 ;
     RECT  2.16 33.615 41.04 33.885 ;
     RECT  2.16 34.155 41.04 34.425 ;
     RECT  2.16 34.695 41.04 34.965 ;
     RECT  2.16 35.235 41.04 35.505 ;
     RECT  2.16 35.775 41.04 36.045 ;
     RECT  2.16 36.315 41.04 36.585 ;
     RECT  2.16 36.855 41.04 37.125 ;
     RECT  2.16 37.395 41.04 37.665 ;
     RECT  2.16 37.935 41.04 38.205 ;
     RECT  2.16 38.475 41.04 38.745 ;
     RECT  2.16 39.015 41.04 39.285 ;
     RECT  2.16 39.555 41.04 39.825 ;
     RECT  2.16 40.095 41.04 40.365 ;
     RECT  2.16 40.635 41.04 40.905 ;
    LAYER M1 ;
     RECT  2.16 2.151 41.04 41.049 ;
    LAYER M2 ;
     RECT  0.103 18 0.175 18.72 ;
     RECT  0.103 19.512 0.175 19.53 ;
     RECT  0.175 18 0.239 19.53 ;
     RECT  0.139 16.92 0.283 16.938 ;
     RECT  0.239 18 0.283 19.368 ;
     RECT  0.175 28.962 0.383 28.98 ;
     RECT  0.103 13.068 0.463 13.086 ;
     RECT  0.175 12.294 0.499 12.312 ;
     RECT  0.463 13.068 0.499 13.464 ;
     RECT  0.103 11.52 0.535 11.538 ;
     RECT  0.499 12.294 0.535 13.464 ;
     RECT  0.103 27.342 0.535 27.36 ;
     RECT  0.103 37.476 1.147 37.494 ;
     RECT  0.103 33.048 1.183 33.066 ;
     RECT  0.103 21.78 1.723 21.798 ;
     RECT  0.535 11.448 2.16 11.538 ;
     RECT  0.535 12.294 2.16 13.662 ;
     RECT  0.103 14.49 2.16 14.508 ;
     RECT  0.103 15.84 2.16 15.858 ;
     RECT  0.283 16.92 2.16 19.368 ;
     RECT  0.103 20.97 2.16 20.988 ;
     RECT  1.723 21.78 2.16 22.032 ;
     RECT  0.103 23.832 2.16 23.85 ;
     RECT  0.535 27.342 2.16 27.738 ;
     RECT  0.535 28.8 2.16 28.818 ;
     RECT  1.723 29.61 2.16 29.628 ;
     RECT  0.535 31.158 2.16 31.176 ;
     RECT  1.183 33.048 2.16 33.678 ;
     RECT  1.147 37.44 2.16 37.494 ;
     RECT  2.16 2.151 20.911 41.049 ;
     RECT  20.911 2.106 21.955 41.049 ;
     RECT  21.991 1.152 22.099 1.17 ;
     RECT  22.099 1.152 22.199 1.242 ;
     RECT  21.955 2.07 22.207 41.049 ;
     RECT  22.199 1.152 23.747 1.17 ;
     RECT  22.207 1.998 24.179 41.049 ;
     RECT  24.179 2.034 25.511 41.049 ;
     RECT  25.511 2.07 25.979 41.049 ;
     RECT  25.979 2.106 26.015 41.049 ;
     RECT  26.015 2.151 40.099 41.049 ;
     RECT  40.099 2.151 40.415 41.094 ;
     RECT  40.415 2.151 41.04 41.049 ;
     RECT  41.04 40.176 41.639 40.554 ;
     RECT  41.04 27.342 41.675 39.006 ;
     RECT  41.675 27.342 41.891 34.416 ;
     RECT  41.891 28.116 42.179 34.416 ;
     RECT  41.639 40.536 42.179 40.554 ;
     RECT  42.179 29.232 42.215 34.416 ;
     RECT  41.675 35.28 42.215 39.006 ;
     RECT  42.179 28.116 42.251 28.476 ;
     RECT  42.215 31.122 42.251 33.102 ;
     RECT  42.215 38.988 42.251 39.006 ;
     RECT  42.215 35.28 42.287 36.954 ;
     RECT  42.287 35.28 42.323 36.378 ;
     RECT  42.215 29.232 42.979 29.592 ;
     RECT  42.251 31.122 43.007 32.598 ;
     RECT  42.215 38.016 43.015 38.232 ;
     RECT  41.891 27.342 43.043 27.36 ;
     RECT  42.251 28.458 43.079 28.476 ;
     RECT  42.979 29.232 43.079 29.628 ;
     RECT  43.015 37.476 43.079 38.232 ;
     RECT  43.079 29.232 43.115 29.25 ;
     RECT  43.007 31.158 43.115 32.598 ;
     RECT  42.215 34.398 43.115 34.416 ;
     RECT  42.323 35.784 43.115 36.378 ;
     RECT  43.079 37.476 43.115 38.034 ;
    LAYER M3 ;
     RECT  22.104 0.043 22.122 0.091 ;
     RECT  26.496 0.043 26.514 0.091 ;
     RECT  12.816 0.091 12.834 0.139 ;
     RECT  15.84 0.091 15.858 0.139 ;
     RECT  22.032 0.091 22.122 0.139 ;
     RECT  26.136 0.091 26.514 0.187 ;
     RECT  26.1 0.187 26.514 0.235 ;
     RECT  22.032 0.139 22.374 0.283 ;
     RECT  23.364 0.139 23.382 0.283 ;
     RECT  20.016 0.091 20.97 0.475 ;
     RECT  22.032 0.283 23.382 0.475 ;
     RECT  12.816 0.139 13.014 0.571 ;
     RECT  15.624 0.139 15.858 0.571 ;
     RECT  19.656 0.475 23.382 0.571 ;
     RECT  18.288 0.571 18.306 1.099 ;
     RECT  19.044 0.571 23.598 1.099 ;
     RECT  15.624 0.571 16.578 1.147 ;
     RECT  18.288 1.099 23.598 1.147 ;
     RECT  17.388 1.147 17.406 1.579 ;
     RECT  18.288 1.147 23.742 1.579 ;
     RECT  12.816 0.571 13.122 1.723 ;
     RECT  15.624 1.147 16.65 1.723 ;
     RECT  17.388 1.579 23.742 1.723 ;
     RECT  15.624 1.723 23.742 1.993 ;
     RECT  24.516 1.723 24.534 1.993 ;
     RECT  25.74 0.235 26.514 2.029 ;
     RECT  12.816 1.723 13.194 2.143 ;
     RECT  25.488 2.029 26.514 2.191 ;
     RECT  15.624 1.993 24.534 2.335 ;
     RECT  25.344 2.191 26.514 2.335 ;
     RECT  12.816 2.143 13.305 2.371 ;
     RECT  15.624 2.335 26.514 2.371 ;
     RECT  2.415 2.143 2.505 2.413 ;
     RECT  7.815 2.143 7.905 2.413 ;
     RECT  12.816 2.371 13.374 2.413 ;
     RECT  29.415 2.143 29.505 2.413 ;
     RECT  34.815 2.143 34.905 2.413 ;
     RECT  40.215 2.143 40.305 2.413 ;
     RECT  12.816 2.413 13.497 2.461 ;
     RECT  12.708 2.461 13.497 2.561 ;
     RECT  12.78 2.561 13.497 2.641 ;
     RECT  14.94 2.371 26.514 2.641 ;
     RECT  12.78 2.641 26.514 2.669 ;
     RECT  12.816 2.669 26.514 2.759 ;
     RECT  12.816 2.759 26.478 3.415 ;
     RECT  12.672 3.415 26.478 3.847 ;
     RECT  12.672 3.847 26.514 3.965 ;
     RECT  12.672 3.965 26.01 4.109 ;
     RECT  12.672 4.109 25.722 4.289 ;
     RECT  12.672 4.289 25.686 4.415 ;
     RECT  12.672 4.415 25.65 4.801 ;
     RECT  12.6 4.801 25.65 5.099 ;
     RECT  13.104 5.099 25.65 5.611 ;
     RECT  13.104 5.611 26.01 5.773 ;
     RECT  13.104 5.773 26.118 5.881 ;
     RECT  12.024 5.971 12.042 6.079 ;
     RECT  13.104 5.881 26.478 6.079 ;
     RECT  9.072 3.883 9.09 6.151 ;
     RECT  10.44 6.079 10.458 6.151 ;
     RECT  9.072 6.151 10.458 6.421 ;
     RECT  12.024 6.079 26.478 6.421 ;
     RECT  9.072 6.421 10.638 6.511 ;
     RECT  11.952 6.421 26.766 6.539 ;
     RECT  11.952 6.539 25.362 6.611 ;
     RECT  8.856 6.511 10.638 6.691 ;
     RECT  8.856 6.691 10.926 6.809 ;
     RECT  11.844 6.655 11.862 6.809 ;
     RECT  12.636 6.611 25.362 6.809 ;
     RECT  8.856 6.809 10.854 6.845 ;
     RECT  12.672 6.809 25.362 7.291 ;
     RECT  26.1 6.539 26.766 7.291 ;
     RECT  12.672 7.291 26.766 7.357 ;
     RECT  12.672 7.357 26.838 7.501 ;
     RECT  12.672 7.501 27.306 7.591 ;
     RECT  12.42 7.591 27.306 7.655 ;
     RECT  7.815 2.413 8.097 7.699 ;
     RECT  8.856 6.845 9.414 7.699 ;
     RECT  7.815 7.699 9.414 7.861 ;
     RECT  10.152 6.845 10.854 7.889 ;
     RECT  11.664 7.393 11.682 7.963 ;
     RECT  12.42 7.655 26.19 7.963 ;
     RECT  11.664 7.963 26.19 8.437 ;
     RECT  26.964 7.655 27.306 8.437 ;
     RECT  11.664 8.437 27.306 8.815 ;
     RECT  10.152 7.889 10.71 8.851 ;
     RECT  11.484 8.815 27.306 8.851 ;
     RECT  10.152 8.851 27.306 9.005 ;
     RECT  11.484 9.005 27.306 9.149 ;
     RECT  12.852 9.149 27.306 9.553 ;
     RECT  7.632 7.861 9.414 9.823 ;
     RECT  10.152 9.005 10.71 9.823 ;
     RECT  11.484 9.149 12.006 9.931 ;
     RECT  12.852 9.553 27.522 9.931 ;
     RECT  11.484 9.931 27.774 10.057 ;
     RECT  7.632 9.823 10.71 10.129 ;
     RECT  11.484 10.057 27.882 10.129 ;
     RECT  7.632 10.129 27.882 10.201 ;
     RECT  4.608 10.291 4.626 10.399 ;
     RECT  4.608 10.399 4.698 10.435 ;
     RECT  7.632 10.201 28.062 10.471 ;
     RECT  3.996 10.435 4.698 10.561 ;
     RECT  2.415 2.413 2.697 10.597 ;
     RECT  6.444 5.071 6.462 10.669 ;
     RECT  3.996 10.561 4.77 10.705 ;
     RECT  5.508 6.115 5.526 10.705 ;
     RECT  2.415 10.597 2.97 10.741 ;
     RECT  3.996 10.705 5.526 10.741 ;
     RECT  2.415 10.741 5.526 10.867 ;
     RECT  2.415 10.867 5.562 10.933 ;
     RECT  6.444 10.669 6.858 10.933 ;
     RECT  2.415 10.933 6.858 11.003 ;
     RECT  7.632 10.471 28.206 11.011 ;
     RECT  7.632 11.011 28.242 11.173 ;
     RECT  2.415 11.003 6.57 11.245 ;
     RECT  2.376 11.245 6.57 11.371 ;
     RECT  0.54 11.443 0.558 11.515 ;
     RECT  7.308 11.173 28.314 11.669 ;
     RECT  2.34 11.371 6.57 11.707 ;
     RECT  2.196 11.707 6.57 11.749 ;
     RECT  7.308 11.669 28.098 11.749 ;
     RECT  2.196 11.749 28.098 11.939 ;
     RECT  2.196 11.939 27.99 11.981 ;
     RECT  0.108 11.515 0.558 12.173 ;
     RECT  0.18 12.173 0.558 12.749 ;
     RECT  2.304 11.981 27.99 12.859 ;
     RECT  2.232 12.859 27.99 12.901 ;
     RECT  2.232 12.901 28.17 13.037 ;
     RECT  0.18 12.749 0.522 13.063 ;
     RECT  0.108 13.063 0.522 13.639 ;
     RECT  2.304 13.037 28.17 13.711 ;
     RECT  0.108 13.639 0.558 14.093 ;
     RECT  2.304 13.711 28.206 14.099 ;
     RECT  2.304 14.099 28.098 14.243 ;
     RECT  2.304 14.243 27.666 14.477 ;
     RECT  2.304 14.477 27.558 14.539 ;
     RECT  2.268 14.539 27.558 14.783 ;
     RECT  2.304 14.783 27.558 15.259 ;
     RECT  0.108 14.093 0.126 15.403 ;
     RECT  2.304 15.259 27.666 15.485 ;
     RECT  0.108 15.403 0.342 15.533 ;
     RECT  2.304 15.485 27.558 15.691 ;
     RECT  0.108 15.533 0.126 16.493 ;
     RECT  2.232 15.691 27.558 16.681 ;
     RECT  1.188 16.951 1.206 17.117 ;
     RECT  0.144 16.915 0.162 17.323 ;
     RECT  2.196 16.681 27.558 17.519 ;
     RECT  0.144 17.323 0.342 17.645 ;
     RECT  2.196 17.519 27.522 17.879 ;
     RECT  1.152 17.803 1.17 17.933 ;
     RECT  0.144 17.645 0.306 17.995 ;
     RECT  2.304 17.879 27.522 18.301 ;
     RECT  28.404 17.887 28.422 18.301 ;
     RECT  0.108 17.995 0.306 18.667 ;
     RECT  2.304 18.301 28.422 18.689 ;
     RECT  2.304 18.689 27.054 18.749 ;
     RECT  2.304 18.749 26.982 18.797 ;
     RECT  2.304 18.797 26.91 18.841 ;
     RECT  0.108 18.667 0.342 18.989 ;
     RECT  2.268 18.841 26.91 18.995 ;
     RECT  2.268 18.995 26.838 19.229 ;
     RECT  2.268 19.229 26.73 19.337 ;
     RECT  0.108 18.989 0.234 19.535 ;
     RECT  0.144 19.535 0.234 19.565 ;
     RECT  0.144 19.565 0.198 19.613 ;
     RECT  32.004 20.011 32.454 20.107 ;
     RECT  30.78 20.011 30.798 20.149 ;
     RECT  32.004 20.107 33.102 20.149 ;
     RECT  27.864 18.689 28.422 20.191 ;
     RECT  30.78 20.149 33.102 20.191 ;
     RECT  29.415 2.413 29.697 20.299 ;
     RECT  30.708 20.191 33.102 20.299 ;
     RECT  33.876 20.191 33.894 20.309 ;
     RECT  29.415 20.299 33.102 20.317 ;
     RECT  0.18 19.613 0.198 20.347 ;
     RECT  2.304 19.337 26.73 20.389 ;
     RECT  27.864 20.191 28.602 20.389 ;
     RECT  0.144 20.347 0.198 20.395 ;
     RECT  2.304 20.389 28.602 20.461 ;
     RECT  29.415 20.317 33.426 20.461 ;
     RECT  0.144 20.395 0.342 20.525 ;
     RECT  0.144 20.525 0.162 20.621 ;
     RECT  2.304 20.461 33.426 20.779 ;
     RECT  34.815 2.413 35.097 21.199 ;
     RECT  1.728 20.779 33.426 21.227 ;
     RECT  27.504 21.227 33.426 21.271 ;
     RECT  34.236 21.199 35.097 21.271 ;
     RECT  0.108 20.965 0.126 21.931 ;
     RECT  1.728 21.227 26.694 22.037 ;
     RECT  2.196 22.037 26.694 22.207 ;
     RECT  27.504 21.271 35.097 22.207 ;
     RECT  2.196 22.207 35.097 22.235 ;
     RECT  0.108 21.931 0.162 22.445 ;
     RECT  2.232 22.235 35.097 22.739 ;
     RECT  0.144 22.445 0.162 22.781 ;
     RECT  2.232 22.739 33.894 22.811 ;
     RECT  2.232 22.811 32.742 23.315 ;
     RECT  2.268 23.315 32.742 23.387 ;
     RECT  33.516 22.811 33.894 23.549 ;
     RECT  2.34 23.387 32.742 23.557 ;
     RECT  33.516 23.549 33.57 23.557 ;
     RECT  0.108 23.827 0.126 24.077 ;
     RECT  2.34 23.557 33.57 24.205 ;
     RECT  0.144 24.235 0.162 24.413 ;
     RECT  2.304 24.205 33.57 24.511 ;
     RECT  2.304 24.511 33.822 24.781 ;
     RECT  34.815 22.739 35.097 24.781 ;
     RECT  2.304 24.781 35.097 25.037 ;
     RECT  2.304 25.037 13.698 25.079 ;
     RECT  2.304 25.079 13.497 25.387 ;
     RECT  14.544 25.037 35.097 25.475 ;
     RECT  34.128 25.475 35.097 25.547 ;
     RECT  2.268 25.387 13.497 25.817 ;
     RECT  14.544 25.475 33.39 25.817 ;
     RECT  11.952 25.817 13.497 25.819 ;
     RECT  11.952 25.819 13.806 25.853 ;
     RECT  12.384 25.853 13.806 25.859 ;
     RECT  14.544 25.817 32.814 25.979 ;
     RECT  12.384 25.859 13.497 26.015 ;
     RECT  0.324 26.443 0.342 26.573 ;
     RECT  14.544 25.979 32.706 26.761 ;
     RECT  0.18 26.587 0.198 26.765 ;
     RECT  1.152 26.923 1.17 27.101 ;
     RECT  40.215 2.413 40.497 27.337 ;
     RECT  12.852 26.015 13.497 27.355 ;
     RECT  2.268 25.817 11.178 27.403 ;
     RECT  14.544 26.761 32.742 27.481 ;
     RECT  33.48 27.031 33.498 27.481 ;
     RECT  0.108 27.337 0.162 27.499 ;
     RECT  34.815 25.547 35.097 27.571 ;
     RECT  12.708 27.355 13.497 27.707 ;
     RECT  0.108 27.499 0.342 27.715 ;
     RECT  40.215 27.337 40.842 27.715 ;
     RECT  34.776 27.571 35.097 27.751 ;
     RECT  40.14 27.715 40.842 27.751 ;
     RECT  1.728 27.403 11.178 27.779 ;
     RECT  34.74 27.751 35.097 27.821 ;
     RECT  34.776 27.821 35.097 27.917 ;
     RECT  13.215 27.707 13.497 27.931 ;
     RECT  14.544 27.481 33.498 27.931 ;
     RECT  13.215 27.931 33.498 27.941 ;
     RECT  41.868 27.913 41.886 28.111 ;
     RECT  1.728 27.779 10.854 28.139 ;
     RECT  0.108 27.715 0.558 28.205 ;
     RECT  40.14 27.751 40.914 28.219 ;
     RECT  41.868 28.111 42.246 28.219 ;
     RECT  39.744 28.219 40.914 28.255 ;
     RECT  39.564 28.255 40.914 28.291 ;
     RECT  41.652 28.219 42.246 28.291 ;
     RECT  1.728 28.139 10.638 28.319 ;
     RECT  1.728 28.319 10.566 28.409 ;
     RECT  13.215 27.941 26.406 28.409 ;
     RECT  43.02 27.337 43.038 28.453 ;
     RECT  14.328 28.409 26.406 28.687 ;
     RECT  27.216 27.941 33.498 28.687 ;
     RECT  1.728 28.409 10.242 28.751 ;
     RECT  39.564 28.291 42.246 28.795 ;
     RECT  14.328 28.687 33.498 28.921 ;
     RECT  34.815 27.917 35.097 28.921 ;
     RECT  39.348 28.795 42.246 28.921 ;
     RECT  14.328 28.921 35.097 29.021 ;
     RECT  36.288 28.957 36.306 29.029 ;
     RECT  0.144 28.205 0.558 29.069 ;
     RECT  14.328 29.021 26.406 29.069 ;
     RECT  36.288 29.029 36.342 29.083 ;
     RECT  27.288 29.021 35.097 29.101 ;
     RECT  36.288 29.083 36.558 29.101 ;
     RECT  43.02 28.453 43.074 29.227 ;
     RECT  43.02 29.227 43.11 29.263 ;
     RECT  14.544 29.069 26.406 29.291 ;
     RECT  27.288 29.101 35.37 29.335 ;
     RECT  36.288 29.101 37.278 29.335 ;
     RECT  42.984 29.263 43.11 29.357 ;
     RECT  27.288 29.335 37.278 29.371 ;
     RECT  38.412 28.921 42.246 29.371 ;
     RECT  1.728 28.751 10.134 29.561 ;
     RECT  27.288 29.371 42.246 29.569 ;
     RECT  42.984 29.357 43.074 29.569 ;
     RECT  1.728 29.561 10.062 29.633 ;
     RECT  27.288 29.569 43.074 29.633 ;
     RECT  13.215 28.409 13.497 29.839 ;
     RECT  14.544 29.291 25.11 29.839 ;
     RECT  25.848 29.291 26.406 29.839 ;
     RECT  27.288 29.633 42.282 29.839 ;
     RECT  0.324 29.069 0.558 29.851 ;
     RECT  0.216 29.851 0.558 29.933 ;
     RECT  2.268 29.633 10.062 30.029 ;
     RECT  43.02 29.633 43.074 30.029 ;
     RECT  0.216 29.933 0.234 30.221 ;
     RECT  13.215 29.839 25.11 30.461 ;
     RECT  43.056 30.029 43.074 30.763 ;
     RECT  2.268 30.029 10.026 30.811 ;
     RECT  19.62 30.461 25.11 30.839 ;
     RECT  0.144 30.475 0.162 30.941 ;
     RECT  25.848 29.839 42.282 30.941 ;
     RECT  20.592 30.839 25.11 30.983 ;
     RECT  25.848 30.941 42.21 30.983 ;
     RECT  2.268 30.811 10.134 30.991 ;
     RECT  43.02 30.763 43.074 31.117 ;
     RECT  42.984 31.117 43.074 31.144 ;
     RECT  2.268 30.991 10.278 31.261 ;
     RECT  13.215 30.461 18.897 31.261 ;
     RECT  19.62 30.839 19.674 31.261 ;
     RECT  2.268 31.261 10.35 31.531 ;
     RECT  42.984 31.144 43.11 31.565 ;
     RECT  13.215 31.261 19.674 31.723 ;
     RECT  13.215 31.723 19.71 31.757 ;
     RECT  14.22 31.757 19.71 31.801 ;
     RECT  2.268 31.531 10.458 31.991 ;
     RECT  20.772 30.983 25.11 31.991 ;
     RECT  0.54 31.153 0.558 32.045 ;
     RECT  43.02 31.565 43.11 32.045 ;
     RECT  28.872 30.983 42.21 32.071 ;
     RECT  21.708 31.991 25.11 32.189 ;
     RECT  28.872 32.071 42.246 32.233 ;
     RECT  0.324 32.203 0.342 32.251 ;
     RECT  2.304 31.991 10.458 32.297 ;
     RECT  14.22 31.801 19.746 32.305 ;
     RECT  0.144 32.251 0.342 32.333 ;
     RECT  0.144 32.333 0.162 32.429 ;
     RECT  25.848 30.983 27.918 32.431 ;
     RECT  28.872 32.233 42.282 32.431 ;
     RECT  14.22 32.305 20.646 32.459 ;
     RECT  21.96 32.189 25.11 32.495 ;
     RECT  25.848 32.431 42.282 32.525 ;
     RECT  14.544 32.459 20.178 32.603 ;
     RECT  43.092 32.045 43.11 32.603 ;
     RECT  25.848 32.525 42.246 32.717 ;
     RECT  17.028 32.603 19.638 32.765 ;
     RECT  2.304 32.297 10.35 32.779 ;
     RECT  2.268 32.779 10.35 32.801 ;
     RECT  2.268 32.801 10.17 32.971 ;
     RECT  2.232 32.971 10.17 32.999 ;
     RECT  41.904 32.717 42.246 33.005 ;
     RECT  25.848 32.717 41.022 33.101 ;
     RECT  1.296 33.451 1.314 33.547 ;
     RECT  1.188 33.547 1.314 33.581 ;
     RECT  42.048 33.005 42.246 33.581 ;
     RECT  1.188 33.581 1.206 33.683 ;
     RECT  0.108 33.043 0.126 33.739 ;
     RECT  42.048 33.581 42.21 33.835 ;
     RECT  25.848 33.101 40.662 33.931 ;
     RECT  0.108 33.739 0.342 34.061 ;
     RECT  41.616 33.835 42.21 34.061 ;
     RECT  25.848 33.931 40.734 34.109 ;
     RECT  25.848 34.109 29.79 34.205 ;
     RECT  30.564 34.109 40.734 34.349 ;
     RECT  13.215 31.757 13.497 34.357 ;
     RECT  2.232 32.999 10.098 34.385 ;
     RECT  11.7 34.357 11.718 34.393 ;
     RECT  12.6 34.357 13.497 34.393 ;
     RECT  30.672 34.349 40.554 34.421 ;
     RECT  43.092 34.393 43.11 34.445 ;
     RECT  41.616 34.061 42.174 34.459 ;
     RECT  11.7 34.393 13.497 34.501 ;
     RECT  17.028 32.765 18.897 34.799 ;
     RECT  0.108 34.061 0.162 34.891 ;
     RECT  2.268 34.385 10.098 34.925 ;
     RECT  11.016 34.501 13.497 34.933 ;
     RECT  14.544 32.603 16.002 34.933 ;
     RECT  22.392 32.495 25.11 35.005 ;
     RECT  25.848 34.205 29.697 35.005 ;
     RECT  19.62 32.765 19.638 35.069 ;
     RECT  11.016 34.933 16.002 35.167 ;
     RECT  17.028 34.799 17.154 35.167 ;
     RECT  0.108 34.891 0.342 35.213 ;
     RECT  11.016 35.167 17.154 35.275 ;
     RECT  41.292 34.459 42.174 35.275 ;
     RECT  2.304 34.925 10.098 35.323 ;
     RECT  10.836 35.275 17.154 35.323 ;
     RECT  30.96 34.421 40.554 35.467 ;
     RECT  41.292 35.275 42.318 35.467 ;
     RECT  30.96 35.467 42.318 35.515 ;
     RECT  30.96 35.515 42.966 35.563 ;
     RECT  2.304 35.323 17.154 35.659 ;
     RECT  30.96 35.563 43.038 35.779 ;
     RECT  0.108 35.213 0.162 35.947 ;
     RECT  0.108 35.947 0.342 36.077 ;
     RECT  30.96 35.779 43.11 36.077 ;
     RECT  2.268 35.659 17.154 36.085 ;
     RECT  17.928 34.799 18.897 36.085 ;
     RECT  30.96 36.077 42.318 36.121 ;
     RECT  30.78 36.121 42.318 36.347 ;
     RECT  43.056 36.077 43.11 36.461 ;
     RECT  2.268 36.085 18.897 36.617 ;
     RECT  2.304 36.617 18.897 37.229 ;
     RECT  22.392 35.005 29.697 37.327 ;
     RECT  2.304 37.229 17.514 37.355 ;
     RECT  22.392 37.327 29.754 37.435 ;
     RECT  30.96 36.347 42.318 37.435 ;
     RECT  43.056 36.461 43.074 37.435 ;
     RECT  1.152 35.323 1.17 37.463 ;
     RECT  22.392 37.435 43.074 37.471 ;
     RECT  0.108 36.077 0.126 37.499 ;
     RECT  22.392 37.471 43.11 38.093 ;
     RECT  2.415 37.355 17.514 38.129 ;
     RECT  22.392 38.093 42.318 38.189 ;
     RECT  43.056 38.093 43.11 38.285 ;
     RECT  2.415 38.129 17.406 38.579 ;
     RECT  2.415 38.579 3.546 38.669 ;
     RECT  4.32 38.579 17.406 38.669 ;
     RECT  2.415 38.669 3.402 38.705 ;
     RECT  4.428 38.669 17.406 38.777 ;
     RECT  4.464 38.777 17.406 38.939 ;
     RECT  22.392 38.189 42.21 38.983 ;
     RECT  5.688 38.939 6.102 39.011 ;
     RECT  6.084 39.011 6.102 39.083 ;
     RECT  7.02 38.939 17.406 39.091 ;
     RECT  18.615 37.229 18.897 39.091 ;
     RECT  22.392 38.983 42.246 39.091 ;
     RECT  7.02 39.091 18.897 39.209 ;
     RECT  7.2 39.209 17.334 39.245 ;
     RECT  43.092 38.285 43.11 39.245 ;
     RECT  22.248 39.091 42.246 39.725 ;
     RECT  7.2 39.245 16.974 39.749 ;
     RECT  7.2 39.749 16.614 40.091 ;
     RECT  22.248 39.725 42.138 40.531 ;
     RECT  22.248 40.531 42.174 40.559 ;
     RECT  23.112 40.559 31.338 40.589 ;
     RECT  32.112 40.559 42.174 40.589 ;
     RECT  22.248 40.559 22.338 40.631 ;
     RECT  7.38 40.091 16.614 40.711 ;
     RECT  32.112 40.589 42.138 40.781 ;
     RECT  2.415 38.705 2.697 40.787 ;
     RECT  18.615 39.209 18.897 40.787 ;
     RECT  22.32 40.631 22.338 40.829 ;
     RECT  23.112 40.589 31.122 40.829 ;
     RECT  32.112 40.781 40.95 40.829 ;
     RECT  23.112 40.829 30.762 40.865 ;
     RECT  41.868 40.781 42.138 40.877 ;
     RECT  7.38 40.711 16.83 40.901 ;
     RECT  43.02 40.459 43.038 40.925 ;
     RECT  7.632 40.901 16.83 40.937 ;
     RECT  23.112 40.865 28.602 40.937 ;
     RECT  32.112 40.829 38.898 40.937 ;
     RECT  15.84 40.937 16.254 40.973 ;
     RECT  23.22 40.937 28.602 40.973 ;
     RECT  40.104 40.829 40.95 40.973 ;
     RECT  7.632 40.937 14.922 41.009 ;
     RECT  15.84 40.973 15.858 41.009 ;
     RECT  27.828 40.973 28.494 41.009 ;
     RECT  29.415 40.865 30.762 41.009 ;
     RECT  32.148 40.937 38.574 41.009 ;
     RECT  7.632 41.009 13.554 41.021 ;
     RECT  14.4 41.009 14.418 41.021 ;
     RECT  28.476 41.009 28.494 41.021 ;
     RECT  2.415 40.787 2.505 41.057 ;
     RECT  18.615 40.787 18.705 41.057 ;
     RECT  29.415 41.009 29.505 41.057 ;
     RECT  40.104 40.973 40.41 41.099 ;
     RECT  10.26 41.021 10.926 41.117 ;
     RECT  40.104 41.099 40.122 41.117 ;
     RECT  12.42 41.021 13.554 41.165 ;
     RECT  23.4 40.973 26.91 41.213 ;
     RECT  12.42 41.165 13.374 41.261 ;
     RECT  32.148 41.009 36.486 41.309 ;
     RECT  35.208 41.309 36.486 41.357 ;
     RECT  35.208 41.357 35.73 41.453 ;
     RECT  41.868 40.877 41.958 41.549 ;
     RECT  7.632 41.021 8.586 41.597 ;
     RECT  23.4 41.213 23.994 41.597 ;
     RECT  24.732 41.213 26.91 41.597 ;
     RECT  10.908 41.117 10.926 41.645 ;
     RECT  12.42 41.261 12.978 41.645 ;
     RECT  35.208 41.453 35.658 41.645 ;
     RECT  32.148 41.309 34.47 41.693 ;
     RECT  32.148 41.693 32.598 41.741 ;
     RECT  37.332 41.009 37.35 41.741 ;
     RECT  32.148 41.741 32.346 41.789 ;
     RECT  32.328 41.789 32.346 41.837 ;
     RECT  36.468 41.357 36.486 41.837 ;
     RECT  38.556 41.009 38.574 41.933 ;
     RECT  35.208 41.645 35.406 42.029 ;
     RECT  41.868 41.549 41.886 42.125 ;
     RECT  7.632 41.597 8.478 42.173 ;
     RECT  23.4 41.597 23.922 42.173 ;
     RECT  35.208 42.029 35.37 42.173 ;
     RECT  7.632 42.173 7.974 42.221 ;
     RECT  23.832 42.173 23.922 42.221 ;
     RECT  24.732 41.597 24.894 42.221 ;
     RECT  33.48 41.693 34.47 42.221 ;
     RECT  35.208 42.173 35.226 42.221 ;
     RECT  33.48 42.221 34.362 42.317 ;
     RECT  33.48 42.317 33.498 42.989 ;
     RECT  7.956 42.221 7.974 43.085 ;
     RECT  12.42 41.645 12.438 43.085 ;
     RECT  23.832 42.221 23.85 43.085 ;
     RECT  24.732 42.221 24.75 43.085 ;
     RECT  25.704 41.597 26.91 43.085 ;
     RECT  34.344 42.317 34.362 43.085 ;
    LAYER M4 ;
     RECT  0.06 11.76 0.133 36.264 ;
     RECT  0.133 11.76 2.185 36.36 ;
     RECT  2.185 11.712 2.408 36.36 ;
     RECT  2.408 2.148 2.512 41.052 ;
     RECT  2.512 2.418 2.704 40.782 ;
     RECT  2.704 10.608 2.765 37.032 ;
     RECT  2.765 33.552 2.873 37.032 ;
     RECT  2.873 33.84 2.909 37.032 ;
     RECT  2.765 10.608 3.125 32.472 ;
     RECT  2.909 33.84 3.197 35.016 ;
     RECT  2.909 36.048 3.347 37.032 ;
     RECT  3.197 34.08 3.913 35.016 ;
     RECT  3.125 28.416 3.949 32.472 ;
     RECT  3.949 28.416 4.201 32.52 ;
     RECT  3.347 36.528 4.201 37.032 ;
     RECT  3.769 38.16 4.201 38.184 ;
     RECT  3.913 34.08 4.273 35.544 ;
     RECT  4.273 33.936 4.417 35.544 ;
     RECT  4.201 36.528 4.417 38.184 ;
     RECT  4.417 33.936 4.44 38.184 ;
     RECT  4.44 33.936 4.547 38.424 ;
     RECT  3.125 10.608 4.796 27.192 ;
     RECT  4.201 28.368 4.837 32.52 ;
     RECT  4.837 28.272 5.209 32.52 ;
     RECT  4.547 33.936 5.209 36.936 ;
     RECT  4.796 10.608 5.281 27.24 ;
     RECT  5.209 28.272 5.281 36.936 ;
     RECT  4.547 38.112 5.465 38.424 ;
     RECT  5.281 10.608 5.605 36.936 ;
     RECT  5.465 38.112 5.605 38.184 ;
     RECT  5.605 10.608 5.645 38.184 ;
     RECT  5.645 10.608 5.717 37.896 ;
     RECT  5.717 10.608 6.275 33.864 ;
     RECT  6.275 11.856 6.865 33.864 ;
     RECT  5.717 34.848 6.865 37.896 ;
     RECT  6.865 11.856 7.369 37.896 ;
     RECT  6.901 8.976 7.808 9 ;
     RECT  6.275 10.608 7.808 10.632 ;
     RECT  7.369 11.856 7.808 38.808 ;
     RECT  7.808 2.148 7.912 41.052 ;
     RECT  7.621 42.192 7.945 42.216 ;
     RECT  7.912 2.418 8.104 41.052 ;
     RECT  7.945 42.192 8.339 43.08 ;
     RECT  8.339 42.192 8.434 42.216 ;
     RECT  8.434 42.144 8.435 42.216 ;
     RECT  8.104 10.608 8.525 33.576 ;
     RECT  8.435 42.144 8.557 42.168 ;
     RECT  8.557 41.568 8.641 42.168 ;
     RECT  8.525 10.608 8.669 29.784 ;
     RECT  8.104 36.048 8.723 39.24 ;
     RECT  8.669 26.208 8.813 29.784 ;
     RECT  8.641 42.144 8.819 42.168 ;
     RECT  8.723 36.048 8.921 38.184 ;
     RECT  8.813 26.304 8.993 29.592 ;
     RECT  8.993 26.304 9.065 29.256 ;
     RECT  8.525 31.2 9.133 33.576 ;
     RECT  8.104 34.704 9.133 34.728 ;
     RECT  8.104 40.464 9.157 40.584 ;
     RECT  9.065 26.304 9.173 29.112 ;
     RECT  9.133 31.2 9.173 34.728 ;
     RECT  9.173 31.2 9.245 34.296 ;
     RECT  9.245 31.2 9.251 31.368 ;
     RECT  9.245 32.448 9.317 34.296 ;
     RECT  9.317 32.448 9.497 34.104 ;
     RECT  9.251 31.344 9.539 31.368 ;
     RECT  8.723 39.216 9.541 39.24 ;
     RECT  9.157 40.464 9.541 41.016 ;
     RECT  9.173 26.304 9.587 29.064 ;
     RECT  9.587 26.304 9.749 26.328 ;
     RECT  9.587 27.36 9.749 29.064 ;
     RECT  9.497 33.552 9.749 34.104 ;
     RECT  9.497 32.448 9.785 32.472 ;
     RECT  8.921 36.432 9.785 38.184 ;
     RECT  9.637 6.816 9.973 6.84 ;
     RECT  9.749 27.36 10.045 28.296 ;
     RECT  9.973 6.816 10.141 7.656 ;
     RECT  9.785 36.48 10.141 38.184 ;
     RECT  9.541 39.216 10.141 41.016 ;
     RECT  8.104 8.976 10.177 9 ;
     RECT  8.669 10.608 10.177 25.176 ;
     RECT  10.141 36.48 10.249 41.016 ;
     RECT  10.141 6.576 10.261 7.656 ;
     RECT  10.261 6.48 10.357 7.656 ;
     RECT  9.817 35.328 10.361 35.352 ;
     RECT  10.249 36.48 10.433 41.112 ;
     RECT  10.177 8.976 10.469 25.176 ;
     RECT  10.433 36.48 10.469 39.432 ;
     RECT  10.045 28.272 10.577 28.296 ;
     RECT  10.469 10.224 10.739 25.176 ;
     RECT  10.469 8.976 10.793 9 ;
     RECT  10.433 40.464 10.897 41.112 ;
     RECT  10.357 6 10.933 7.656 ;
     RECT  10.933 6 10.979 7.992 ;
     RECT  10.739 10.224 11.027 11.976 ;
     RECT  9.749 33.552 11.027 33.576 ;
     RECT  11.027 10.848 11.081 11.976 ;
     RECT  10.469 38.112 11.333 39.432 ;
     RECT  10.469 36.48 11.365 37.08 ;
     RECT  11.365 35.712 11.545 37.08 ;
     RECT  11.333 38.112 11.545 38.664 ;
     RECT  11.66 34.368 11.747 34.392 ;
     RECT  10.739 13.104 11.761 25.176 ;
     RECT  10.897 40.464 11.795 41.64 ;
     RECT  11.545 35.712 11.873 38.664 ;
     RECT  11.081 10.944 11.941 11.976 ;
     RECT  11.761 13.104 11.941 25.704 ;
     RECT  11.795 40.464 11.987 41.064 ;
     RECT  10.979 6 12.053 6.6 ;
     RECT  11.987 40.896 12.205 41.064 ;
     RECT  11.941 10.944 12.332 25.704 ;
     RECT  11.873 35.808 12.337 38.664 ;
     RECT  12.325 39.888 12.421 39.912 ;
     RECT  11.461 43.056 12.449 43.08 ;
     RECT  12.337 35.808 12.481 38.76 ;
     RECT  12.421 39.84 12.481 39.912 ;
     RECT  12.053 6.288 12.709 6.6 ;
     RECT  10.979 7.632 12.709 7.992 ;
     RECT  12.332 10.464 12.913 25.704 ;
     RECT  12.193 34.608 12.913 34.632 ;
     RECT  12.481 35.808 12.913 39.912 ;
     RECT  12.205 40.944 12.949 41.064 ;
     RECT  12.805 0.096 12.985 0.12 ;
     RECT  12.985 0.096 13.043 0.168 ;
     RECT  13.043 0.144 13.093 0.168 ;
     RECT  12.949 40.944 13.139 41.64 ;
     RECT  13.093 0.144 13.177 0.6 ;
     RECT  13.165 4.944 13.201 4.968 ;
     RECT  13.165 1.728 13.208 1.752 ;
     RECT  13.201 4.704 13.208 4.968 ;
     RECT  12.709 6.288 13.208 7.992 ;
     RECT  12.913 10.464 13.208 25.848 ;
     RECT  12.697 27.36 13.208 27.384 ;
     RECT  10.981 32.304 13.208 32.328 ;
     RECT  12.913 34.608 13.208 39.912 ;
     RECT  13.139 40.944 13.208 41.256 ;
     RECT  13.177 0.144 13.235 0.168 ;
     RECT  13.208 1.728 13.331 41.256 ;
     RECT  13.331 2.418 13.385 41.256 ;
     RECT  13.381 42.768 13.429 42.792 ;
     RECT  13.385 2.418 13.504 41.16 ;
     RECT  13.504 6.288 13.565 10.632 ;
     RECT  13.504 35.472 13.565 41.16 ;
     RECT  13.565 8.688 13.601 10.632 ;
     RECT  13.504 12.48 13.619 25.848 ;
     RECT  13.429 42.768 13.619 43.032 ;
     RECT  13.565 36.336 13.637 41.016 ;
     RECT  13.619 42.912 13.667 42.936 ;
     RECT  13.619 24.048 13.817 25.848 ;
     RECT  13.619 12.48 13.925 22.872 ;
     RECT  13.817 24.048 13.925 25.032 ;
     RECT  13.925 12.48 14.105 22.776 ;
     RECT  13.504 27.936 14.147 27.96 ;
     RECT  13.504 29.04 14.249 32.328 ;
     RECT  13.925 24.048 14.284 24.648 ;
     RECT  14.284 24.096 14.339 24.648 ;
     RECT  13.601 8.688 14.357 9.432 ;
     RECT  13.601 10.608 14.429 10.632 ;
     RECT  13.637 40.464 14.429 41.016 ;
     RECT  14.105 12.48 14.537 22.584 ;
     RECT  14.537 12.48 14.579 14.952 ;
     RECT  14.249 29.04 14.579 32.184 ;
     RECT  13.504 3.744 14.605 4.968 ;
     RECT  13.565 6.288 14.605 7.416 ;
     RECT  14.605 3.744 14.713 7.416 ;
     RECT  13.637 36.336 14.713 39.336 ;
     RECT  14.579 29.04 14.785 31.608 ;
     RECT  14.537 15.984 14.819 22.584 ;
     RECT  14.713 3.456 14.831 7.416 ;
     RECT  14.785 28.896 14.867 31.608 ;
     RECT  14.713 36.24 15.001 39.336 ;
     RECT  14.429 40.464 15.001 40.488 ;
     RECT  14.579 12.48 15.02 14.76 ;
     RECT  14.357 9.408 15.361 9.432 ;
     RECT  15.001 36.24 15.365 40.488 ;
     RECT  14.867 28.896 15.397 31.464 ;
     RECT  15.397 28.56 15.469 31.464 ;
     RECT  15.365 36.336 15.493 40.488 ;
     RECT  14.819 15.984 15.505 18.12 ;
     RECT  15.469 27.312 15.541 27.336 ;
     RECT  14.339 24.624 15.577 24.648 ;
     RECT  15.493 36.336 15.58 40.584 ;
     RECT  14.831 3.408 15.649 7.416 ;
     RECT  15.361 8.688 15.649 10.2 ;
     RECT  15.541 26.928 15.649 27.336 ;
     RECT  15.469 28.32 15.649 31.464 ;
     RECT  15.02 12.096 15.685 14.76 ;
     RECT  15.58 36.336 15.689 40.488 ;
     RECT  15.689 36.72 15.725 40.488 ;
     RECT  15.725 36.72 15.797 37.128 ;
     RECT  15.613 0.144 15.829 0.168 ;
     RECT  15.577 24.624 15.829 25.32 ;
     RECT  15.685 11.568 15.901 14.76 ;
     RECT  15.829 24.048 15.973 25.32 ;
     RECT  15.901 11.424 16.045 14.76 ;
     RECT  15.505 15.84 16.045 18.12 ;
     RECT  14.819 19.248 16.045 22.584 ;
     RECT  16.045 11.424 16.081 22.584 ;
     RECT  15.973 23.664 16.081 25.32 ;
     RECT  15.829 0.096 16.115 0.168 ;
     RECT  15.725 40.464 16.229 40.488 ;
     RECT  15.649 26.928 16.265 31.464 ;
     RECT  16.265 28.32 16.337 31.464 ;
     RECT  15.649 3.408 16.357 10.2 ;
     RECT  16.081 11.424 16.357 25.32 ;
     RECT  16.115 0.144 16.403 0.168 ;
     RECT  15.725 38.64 16.409 39.336 ;
     RECT  16.225 1.728 16.513 1.752 ;
     RECT  16.357 3.408 16.547 25.32 ;
     RECT  16.547 24.912 16.553 25.32 ;
     RECT  15.797 36.768 16.553 37.128 ;
     RECT  16.553 37.056 16.589 37.128 ;
     RECT  16.549 0.576 16.621 0.6 ;
     RECT  16.513 1.68 16.621 1.752 ;
     RECT  16.409 39.312 16.625 39.336 ;
     RECT  16.621 0.576 16.633 1.752 ;
     RECT  16.265 26.928 16.693 27.336 ;
     RECT  16.547 3.408 16.741 23.928 ;
     RECT  16.337 29.04 16.765 31.464 ;
     RECT  16.693 26.784 16.787 27.336 ;
     RECT  16.765 29.04 16.985 31.8 ;
     RECT  16.633 1.152 17.017 1.752 ;
     RECT  16.837 37.776 17.021 38.28 ;
     RECT  17.017 1.152 17.101 1.848 ;
     RECT  16.553 24.912 17.171 24.936 ;
     RECT  17.021 37.968 17.237 38.28 ;
     RECT  17.101 1.152 17.417 1.752 ;
     RECT  16.741 2.832 17.489 23.928 ;
     RECT  16.787 26.88 17.561 27.336 ;
     RECT  16.985 29.52 17.593 31.8 ;
     RECT  17.417 1.584 17.843 1.752 ;
     RECT  17.843 1.68 18.341 1.752 ;
     RECT  18.277 0.576 18.469 0.6 ;
     RECT  18.469 25.632 18.493 25.656 ;
     RECT  18.341 1.68 18.565 1.8 ;
     RECT  18.565 1.68 18.608 1.848 ;
     RECT  17.489 2.832 18.608 23.88 ;
     RECT  18.493 24.96 18.608 25.656 ;
     RECT  17.561 27.072 18.608 27.336 ;
     RECT  17.593 29.52 18.608 32.568 ;
     RECT  17.237 37.968 18.608 37.992 ;
     RECT  18.469 0.192 18.659 0.6 ;
     RECT  18.608 1.68 18.712 41.052 ;
     RECT  18.659 0.288 18.803 0.6 ;
     RECT  18.712 1.68 18.904 40.782 ;
     RECT  18.803 0.48 18.961 0.6 ;
     RECT  18.904 1.68 18.961 22.056 ;
     RECT  18.961 0.48 19.109 22.056 ;
     RECT  18.904 23.616 19.289 23.736 ;
     RECT  19.109 0.48 19.397 3.048 ;
     RECT  18.904 30.432 19.397 32.52 ;
     RECT  19.397 30.432 19.433 31.752 ;
     RECT  19.109 4.08 19.667 22.056 ;
     RECT  19.433 30.864 19.721 31.752 ;
     RECT  18.904 28.464 19.757 29.448 ;
     RECT  18.904 27.024 19.765 27.384 ;
     RECT  19.667 14.88 19.793 22.056 ;
     RECT  19.793 14.928 19.901 22.056 ;
     RECT  19.397 0.48 19.955 1.128 ;
     RECT  19.955 0.48 20.005 0.6 ;
     RECT  19.289 23.712 20.005 23.736 ;
     RECT  18.904 24.864 20.005 25.56 ;
     RECT  19.765 27.024 20.041 27.288 ;
     RECT  19.667 4.08 20.045 13.848 ;
     RECT  19.397 2.736 20.101 3.048 ;
     RECT  20.045 4.08 20.101 9.624 ;
     RECT  19.757 28.656 20.185 29.448 ;
     RECT  20.045 11.136 20.261 13.848 ;
     RECT  20.101 2.736 20.297 9.624 ;
     RECT  20.185 28.656 20.437 29.592 ;
     RECT  19.721 30.864 20.437 31.464 ;
     RECT  20.297 2.736 20.444 2.856 ;
     RECT  20.444 2.256 20.531 2.856 ;
     RECT  20.297 3.888 20.531 9.624 ;
     RECT  19.901 15.024 20.531 22.056 ;
     RECT  20.531 20.112 20.533 22.056 ;
     RECT  20.005 23.712 20.533 25.56 ;
     RECT  20.437 28.656 20.557 31.464 ;
     RECT  20.261 11.232 20.585 13.848 ;
     RECT  20.557 28.656 20.585 29.592 ;
     RECT  20.557 30.576 20.725 31.464 ;
     RECT  20.585 28.656 20.729 29.304 ;
     RECT  20.005 0.096 20.765 0.6 ;
     RECT  20.531 15.024 21.049 18.936 ;
     RECT  20.533 20.112 21.052 25.56 ;
     RECT  21.052 23.712 21.125 25.56 ;
     RECT  20.965 1.728 21.253 1.752 ;
     RECT  20.585 11.232 21.301 12.552 ;
     RECT  20.585 13.632 21.301 13.848 ;
     RECT  21.049 14.928 21.301 18.936 ;
     RECT  21.301 11.184 21.337 12.552 ;
     RECT  21.125 25.536 21.341 25.56 ;
     RECT  20.729 29.04 21.413 29.304 ;
     RECT  20.531 3.936 21.445 9.624 ;
     RECT  21.337 10.8 21.445 12.552 ;
     RECT  20.041 26.736 21.481 27.288 ;
     RECT  21.253 1.68 21.517 1.752 ;
     RECT  20.531 2.736 21.517 2.856 ;
     RECT  21.481 26.736 21.521 27.912 ;
     RECT  21.517 1.68 21.601 2.856 ;
     RECT  21.052 20.112 21.629 22.632 ;
     RECT  21.445 3.936 21.661 12.552 ;
     RECT  21.301 13.632 21.661 18.936 ;
     RECT  21.601 1.68 21.701 1.8 ;
     RECT  21.661 3.936 21.701 19.32 ;
     RECT  21.701 1.68 21.724 1.704 ;
     RECT  21.601 2.832 21.841 2.856 ;
     RECT  21.701 3.936 21.841 11.784 ;
     RECT  20.725 30.576 21.989 31.56 ;
     RECT  20.765 0.096 22.06 0.552 ;
     RECT  21.521 27.264 22.093 27.912 ;
     RECT  21.413 29.04 22.093 29.064 ;
     RECT  21.701 13.056 22.169 19.32 ;
     RECT  22.169 14.784 22.205 19.32 ;
     RECT  22.205 16.272 22.211 19.32 ;
     RECT  22.06 0.048 22.213 0.552 ;
     RECT  22.093 27.264 22.277 29.064 ;
     RECT  21.629 20.928 22.313 22.632 ;
     RECT  21.125 23.712 22.417 24.504 ;
     RECT  18.904 37.968 22.489 37.992 ;
     RECT  22.169 13.056 22.693 13.08 ;
     RECT  22.489 37.968 22.741 38.712 ;
     RECT  22.277 27.264 22.777 27.288 ;
     RECT  22.693 13.008 22.781 13.08 ;
     RECT  22.417 23.424 22.781 24.504 ;
     RECT  20.965 36.768 22.813 36.792 ;
     RECT  22.211 16.272 22.853 19.272 ;
     RECT  22.813 36.768 22.853 36.888 ;
     RECT  22.777 27.024 22.885 27.288 ;
     RECT  21.841 2.832 22.925 11.784 ;
     RECT  21.989 30.576 22.925 31.464 ;
     RECT  22.741 37.968 22.997 39.384 ;
     RECT  22.205 14.784 23.245 15.096 ;
     RECT  22.853 18.528 23.245 19.272 ;
     RECT  22.781 23.424 23.461 23.736 ;
     RECT  22.885 25.872 23.461 27.288 ;
     RECT  22.313 20.928 23.497 22.248 ;
     RECT  23.461 23.28 23.497 23.736 ;
     RECT  22.213 0.048 23.609 0.6 ;
     RECT  23.245 18.528 23.713 19.56 ;
     RECT  23.605 40.416 23.713 40.44 ;
     RECT  23.713 40.416 23.749 40.68 ;
     RECT  23.389 42.144 23.749 42.168 ;
     RECT  23.749 40.416 23.821 42.168 ;
     RECT  22.925 2.832 23.857 11.64 ;
     RECT  22.781 13.056 23.893 13.08 ;
     RECT  23.245 14.784 23.893 15.192 ;
     RECT  22.853 16.272 23.929 17.496 ;
     RECT  23.713 18.528 23.929 19.848 ;
     RECT  23.497 20.928 23.929 23.736 ;
     RECT  23.461 24.912 23.929 27.288 ;
     RECT  23.929 16.272 24.001 19.848 ;
     RECT  23.929 20.928 24.001 27.288 ;
     RECT  22.789 1.728 24.008 1.752 ;
     RECT  23.857 2.784 24.008 11.64 ;
     RECT  23.893 12.624 24.008 13.08 ;
     RECT  23.893 14.256 24.008 15.192 ;
     RECT  24.001 16.272 24.008 27.288 ;
     RECT  22.277 28.416 24.008 29.064 ;
     RECT  22.925 31.44 24.008 31.464 ;
     RECT  22.853 36.864 24.008 36.888 ;
     RECT  22.997 37.968 24.008 39.096 ;
     RECT  23.821 40.416 24.008 43.08 ;
     RECT  24.008 1.728 24.304 43.08 ;
     RECT  24.304 17.616 24.365 25.032 ;
     RECT  24.304 1.728 24.419 7.416 ;
     RECT  24.304 11.472 24.419 13.368 ;
     RECT  24.304 15.024 24.419 16.584 ;
     RECT  24.365 20.448 24.419 25.032 ;
     RECT  24.419 15.024 24.465 16.44 ;
     RECT  24.465 15.744 24.467 16.44 ;
     RECT  24.365 17.616 24.467 19.32 ;
     RECT  24.419 1.728 24.509 6.648 ;
     RECT  24.467 16.272 24.509 16.44 ;
     RECT  24.304 35.904 24.509 38.76 ;
     RECT  24.509 1.728 24.545 4.152 ;
     RECT  24.509 5.184 24.563 6.648 ;
     RECT  24.304 39.744 24.563 43.08 ;
     RECT  24.304 8.448 24.617 10.296 ;
     RECT  24.467 17.616 24.617 19.272 ;
     RECT  24.563 40.848 24.689 43.08 ;
     RECT  24.419 20.448 24.797 23.88 ;
     RECT  24.545 2.592 24.869 4.152 ;
     RECT  24.689 40.992 24.947 43.08 ;
     RECT  24.563 5.712 25.049 6.648 ;
     RECT  24.797 20.448 25.085 23.304 ;
     RECT  24.419 24.912 25.085 25.032 ;
     RECT  25.049 5.712 25.229 6.264 ;
     RECT  25.229 5.808 25.373 6.264 ;
     RECT  24.947 40.992 25.517 41.592 ;
     RECT  25.373 6.24 25.523 6.264 ;
     RECT  24.509 16.272 25.58 16.296 ;
     RECT  24.617 17.616 25.58 18.648 ;
     RECT  25.58 16.272 25.585 18.648 ;
     RECT  24.617 8.448 25.589 9.624 ;
     RECT  24.563 39.744 25.657 39.768 ;
     RECT  24.419 11.472 25.661 12.024 ;
     RECT  25.585 16.272 25.667 18.744 ;
     RECT  24.509 35.904 25.667 38.376 ;
     RECT  24.869 2.592 25.697 3.96 ;
     RECT  25.589 9.504 25.697 9.624 ;
     RECT  25.697 9.6 25.729 9.624 ;
     RECT  25.661 11.472 25.729 11.544 ;
     RECT  25.667 36.384 25.729 38.376 ;
     RECT  25.667 17.328 25.765 18.744 ;
     RECT  25.085 20.448 25.765 22.344 ;
     RECT  25.729 9.6 25.769 11.544 ;
     RECT  25.769 9.6 25.841 11.496 ;
     RECT  25.765 17.328 25.841 22.344 ;
     RECT  23.609 0.048 25.877 0.36 ;
     RECT  25.841 9.6 25.949 10.296 ;
     RECT  24.947 43.008 25.957 43.08 ;
     RECT  25.621 24.816 25.981 24.84 ;
     RECT  25.477 7.296 26.017 7.32 ;
     RECT  25.729 14.832 26.021 14.856 ;
     RECT  25.957 42.96 26.053 43.08 ;
     RECT  26.017 7.296 26.057 7.416 ;
     RECT  25.841 17.328 26.093 21.096 ;
     RECT  24.304 26.64 26.093 29.064 ;
     RECT  25.877 0.048 26.129 0.216 ;
     RECT  25.841 11.472 26.129 11.496 ;
     RECT  26.129 0.048 26.165 0.12 ;
     RECT  26.053 42.912 26.195 43.08 ;
     RECT  25.697 2.736 26.201 3.96 ;
     RECT  26.201 2.736 26.237 2.76 ;
     RECT  25.657 39.744 26.245 39.912 ;
     RECT  25.517 40.992 26.245 41.016 ;
     RECT  24.419 13.344 26.269 13.368 ;
     RECT  25.667 16.272 26.273 16.296 ;
     RECT  26.195 42.96 26.273 43.08 ;
     RECT  25.841 22.32 26.309 22.344 ;
     RECT  26.093 26.64 26.309 29.016 ;
     RECT  26.273 43.008 26.345 43.08 ;
     RECT  26.245 39.744 26.377 41.016 ;
     RECT  26.377 23.424 26.521 23.448 ;
     RECT  26.165 0.048 26.525 0.072 ;
     RECT  26.201 3.936 26.525 3.96 ;
     RECT  26.093 17.328 26.525 18.744 ;
     RECT  26.309 26.736 26.525 29.016 ;
     RECT  26.525 17.328 26.597 17.544 ;
     RECT  25.729 36.384 26.629 38.472 ;
     RECT  26.377 39.6 26.629 41.016 ;
     RECT  26.269 13.344 26.665 13.608 ;
     RECT  26.597 17.52 26.705 17.544 ;
     RECT  26.521 22.56 26.723 23.448 ;
     RECT  25.589 8.448 26.777 8.472 ;
     RECT  26.665 13.296 26.813 13.608 ;
     RECT  26.701 15.984 26.813 16.008 ;
     RECT  25.949 9.6 26.849 9.624 ;
     RECT  26.525 26.928 26.849 29.016 ;
     RECT  26.813 13.344 26.885 13.416 ;
     RECT  26.345 43.056 26.921 43.08 ;
     RECT  26.885 13.344 26.957 13.368 ;
     RECT  26.093 20.448 27.061 21.096 ;
     RECT  26.525 18.72 27.065 18.744 ;
     RECT  24.304 31.44 27.065 31.464 ;
     RECT  26.849 27.696 27.101 29.016 ;
     RECT  26.057 7.392 27.107 7.416 ;
     RECT  26.629 36.384 27.173 41.016 ;
     RECT  27.061 9.072 27.245 9.096 ;
     RECT  25.981 24.672 27.277 24.84 ;
     RECT  27.101 27.84 27.277 29.016 ;
     RECT  27.277 27.84 27.361 29.112 ;
     RECT  26.723 22.752 27.596 23.448 ;
     RECT  27.277 24.672 27.596 25.224 ;
     RECT  27.385 34.8 27.605 34.824 ;
     RECT  27.361 27.84 27.683 28.44 ;
     RECT  27.061 10.896 27.745 10.92 ;
     RECT  27.061 20.304 27.745 21.096 ;
     RECT  27.745 10.608 27.929 10.92 ;
     RECT  27.596 22.752 27.971 25.224 ;
     RECT  27.637 11.952 28.001 11.976 ;
     RECT  27.929 10.608 28.037 10.632 ;
     RECT  27.745 20.304 28.289 21.432 ;
     RECT  27.971 24.576 28.325 25.224 ;
     RECT  27.971 22.752 28.361 23.592 ;
     RECT  27.173 36.384 28.645 36.408 ;
     RECT  27.173 37.584 28.645 41.016 ;
     RECT  27.683 27.84 28.861 27.864 ;
     RECT  27.599 31.728 28.897 31.752 ;
     RECT  28.861 27.84 29.005 28.392 ;
     RECT  28.897 30.96 29.036 31.752 ;
     RECT  28.289 20.304 29.408 20.328 ;
     RECT  28.289 21.408 29.408 21.432 ;
     RECT  28.361 22.896 29.408 23.592 ;
     RECT  28.325 25.2 29.408 25.224 ;
     RECT  29.005 27.072 29.408 28.392 ;
     RECT  29.036 30.048 29.408 31.752 ;
     RECT  29.269 32.832 29.408 32.856 ;
     RECT  28.741 34.176 29.408 34.2 ;
     RECT  28.645 36.384 29.408 41.016 ;
     RECT  29.408 2.148 29.512 41.052 ;
     RECT  29.512 2.418 29.704 40.782 ;
     RECT  29.704 34.08 29.801 34.2 ;
     RECT  29.704 39.6 29.837 40.056 ;
     RECT  29.837 39.6 29.873 39.816 ;
     RECT  29.704 21.408 29.981 21.432 ;
     RECT  29.704 28.224 30.701 29.064 ;
     RECT  29.704 23.568 30.809 23.592 ;
     RECT  29.704 30.96 30.881 32.088 ;
     RECT  30.701 28.992 30.989 29.064 ;
     RECT  29.873 39.6 31.309 39.768 ;
     RECT  30.989 29.04 31.381 29.064 ;
     RECT  29.704 37.44 31.381 37.992 ;
     RECT  29.801 34.08 31.417 34.104 ;
     RECT  30.881 31.632 31.421 32.088 ;
     RECT  31.381 37.44 31.421 38.04 ;
     RECT  31.381 29.04 31.427 30.024 ;
     RECT  29.704 20.304 31.453 20.328 ;
     RECT  31.309 39.6 31.453 40.584 ;
     RECT  29.704 25.968 31.489 26.088 ;
     RECT  31.453 20.16 31.493 20.328 ;
     RECT  31.417 34.08 31.529 34.776 ;
     RECT  31.529 34.08 31.621 34.392 ;
     RECT  31.489 25.968 31.817 26.808 ;
     RECT  31.493 20.16 31.993 20.184 ;
     RECT  30.985 27.792 32.105 27.912 ;
     RECT  32.105 27.792 32.141 27.816 ;
     RECT  31.421 37.584 32.173 38.04 ;
     RECT  31.453 39.312 32.173 40.584 ;
     RECT  32.137 41.76 32.317 41.784 ;
     RECT  31.817 26.784 32.389 26.808 ;
     RECT  31.421 31.632 32.389 31.992 ;
     RECT  32.173 37.584 32.425 40.584 ;
     RECT  32.317 41.76 32.425 41.832 ;
     RECT  31.381 24.48 32.54 24.504 ;
     RECT  31.621 33.552 32.569 34.392 ;
     RECT  31.381 36.096 32.569 36.12 ;
     RECT  32.425 37.584 32.569 41.832 ;
     RECT  32.389 26.784 32.573 27.72 ;
     RECT  32.54 23.664 32.581 24.504 ;
     RECT  31.993 20.112 32.609 20.184 ;
     RECT  32.573 26.784 32.609 27.624 ;
     RECT  32.581 22.752 32.627 24.504 ;
     RECT  31.427 30 32.641 30.024 ;
     RECT  32.389 31.632 32.641 32.328 ;
     RECT  32.569 33.36 32.641 41.832 ;
     RECT  32.641 30 32.713 41.832 ;
     RECT  32.713 29.616 32.753 41.832 ;
     RECT  32.627 24.48 32.828 24.504 ;
     RECT  32.828 24.48 32.915 25.224 ;
     RECT  32.627 22.752 32.933 22.776 ;
     RECT  32.915 24.48 33.041 24.504 ;
     RECT  32.609 20.112 33.113 20.136 ;
     RECT  32.753 31.824 33.5 41.832 ;
     RECT  33.469 42.96 33.5 42.984 ;
     RECT  32.753 29.616 34.009 30.168 ;
     RECT  34.009 29.616 34.117 30.792 ;
     RECT  33.5 31.824 34.117 42.984 ;
     RECT  34.117 29.616 34.289 42.984 ;
     RECT  34.289 29.616 34.373 43.08 ;
     RECT  32.609 27.6 34.685 27.624 ;
     RECT  34.685 27.6 34.765 27.816 ;
     RECT  34.765 27.6 34.808 27.912 ;
     RECT  34.373 29.616 34.808 42.984 ;
     RECT  34.808 2.148 34.912 42.984 ;
     RECT  34.912 2.418 35.104 42.984 ;
     RECT  35.104 27.888 35.219 27.912 ;
     RECT  35.104 29.088 35.219 42.984 ;
     RECT  35.219 29.088 35.315 42.216 ;
     RECT  35.315 29.088 36.083 42.168 ;
     RECT  36.083 29.088 36.569 42.024 ;
     RECT  36.569 30.048 37.613 42.024 ;
     RECT  37.613 30.864 38.581 42.024 ;
     RECT  38.581 30.624 39.481 42.024 ;
     RECT  39.481 30.384 39.877 42.024 ;
     RECT  39.877 29.616 40.208 42.024 ;
     RECT  40.208 2.148 40.312 42.024 ;
     RECT  40.312 2.418 40.504 42.024 ;
     RECT  40.504 29.232 41.605 42.024 ;
     RECT  41.605 29.136 41.857 42.024 ;
     RECT  41.857 29.136 43.164 42.12 ;
    LAYER M5 ;
     RECT  13.008 0.016 13.32 0.131 ;
     RECT  16.08 0.016 22.92 0.131 ;
     RECT  16.176 0.131 22.92 0.179 ;
     RECT  13.104 0.131 13.32 0.611 ;
     RECT  16.176 0.179 22.824 0.611 ;
     RECT  16.176 0.611 21.672 1.139 ;
     RECT  20.112 1.139 21.672 1.715 ;
     RECT  22.8 0.611 22.824 1.763 ;
     RECT  16.176 1.139 18.984 1.811 ;
     RECT  16.176 1.811 18.912 1.859 ;
     RECT  13.296 0.611 13.32 2.137 ;
     RECT  2.4 2.137 2.52 2.151 ;
     RECT  7.8 2.137 7.92 2.151 ;
     RECT  13.2 2.137 13.32 2.151 ;
     RECT  24 2.137 24.12 2.151 ;
     RECT  29.4 2.137 29.52 2.151 ;
     RECT  34.8 2.137 34.92 2.151 ;
     RECT  40.2 2.137 40.32 2.151 ;
     RECT  16.176 1.859 16.2 2.821 ;
     RECT  17.328 1.859 18.912 2.821 ;
     RECT  20.112 1.715 21.624 2.821 ;
     RECT  16.176 2.821 21.624 3.203 ;
     RECT  16.176 3.203 19.176 3.397 ;
     RECT  16.08 3.397 19.176 4.067 ;
     RECT  16.08 4.067 16.776 4.115 ;
     RECT  24 2.151 24.312 4.117 ;
     RECT  20.496 3.203 21.624 4.405 ;
     RECT  20.496 4.405 21.864 4.501 ;
     RECT  16.08 4.115 16.536 4.595 ;
     RECT  20.496 4.501 22.68 5.171 ;
     RECT  17.808 4.067 19.176 5.219 ;
     RECT  21.024 5.171 22.68 5.219 ;
     RECT  24 4.117 24.552 5.747 ;
     RECT  15.024 5.221 15.048 6.323 ;
     RECT  21.6 5.219 22.68 6.467 ;
     RECT  10.368 5.989 10.392 6.469 ;
     RECT  18.6 5.219 19.176 6.661 ;
     RECT  10.272 6.469 10.392 6.805 ;
     RECT  13.2 2.151 13.512 6.805 ;
     RECT  25.488 6.229 25.512 7.331 ;
     RECT  24 5.747 24.312 7.381 ;
     RECT  20.4 6.229 20.424 7.475 ;
     RECT  10.272 6.805 10.968 7.621 ;
     RECT  18.6 6.661 19.368 7.861 ;
     RECT  21.84 6.467 22.68 7.861 ;
     RECT  21.12 7.861 22.68 8.003 ;
     RECT  18.048 7.861 19.368 8.533 ;
     RECT  17.664 8.533 19.368 8.773 ;
     RECT  7.8 2.151 8.112 8.965 ;
     RECT  17.616 8.773 19.368 10.069 ;
     RECT  16.08 4.595 16.2 10.117 ;
     RECT  17.52 10.069 19.368 10.117 ;
     RECT  9.984 7.621 10.968 10.213 ;
     RECT  12.72 6.805 13.512 10.453 ;
     RECT  4.416 10.885 4.44 10.933 ;
     RECT  21.84 8.003 22.68 11.173 ;
     RECT  2.4 2.151 2.712 11.221 ;
     RECT  15.648 10.117 19.368 11.269 ;
     RECT  9.984 10.213 11.016 11.317 ;
     RECT  5.664 11.029 5.688 11.365 ;
     RECT  6.912 8.965 8.112 11.365 ;
     RECT  21.84 11.173 22.728 11.365 ;
     RECT  21.84 11.365 22.968 11.555 ;
     RECT  21.84 11.555 22.776 11.603 ;
     RECT  9.312 11.317 11.016 11.653 ;
     RECT  9.312 11.653 11.208 11.749 ;
     RECT  12.384 10.453 13.512 11.749 ;
     RECT  4.416 10.933 4.536 11.941 ;
     RECT  5.664 11.365 8.112 12.083 ;
     RECT  15.648 11.269 19.608 12.085 ;
     RECT  4.032 11.941 4.536 12.181 ;
     RECT  5.664 12.083 5.784 12.181 ;
     RECT  2.4 11.221 2.808 12.517 ;
     RECT  4.032 12.181 5.784 12.517 ;
     RECT  9.312 11.749 13.512 12.517 ;
     RECT  24 7.381 24.408 12.563 ;
     RECT  24 12.563 24.312 12.613 ;
     RECT  6.768 12.083 8.112 12.997 ;
     RECT  21.84 11.603 22.728 13.043 ;
     RECT  2.4 12.517 5.784 13.139 ;
     RECT  9.312 12.517 13.944 13.285 ;
     RECT  15.072 12.085 19.608 13.285 ;
     RECT  6.768 12.997 8.232 13.333 ;
     RECT  9.312 13.285 19.608 13.333 ;
     RECT  21.84 13.043 22.68 13.621 ;
     RECT  6.768 13.333 19.608 13.859 ;
     RECT  15.984 13.859 19.608 13.957 ;
     RECT  23.904 12.613 24.312 14.291 ;
     RECT  2.4 13.139 5.688 14.725 ;
     RECT  6.768 13.859 14.568 14.725 ;
     RECT  2.4 14.725 14.568 14.963 ;
     RECT  15.984 13.957 19.656 15.011 ;
     RECT  24 14.291 24.312 15.013 ;
     RECT  20.88 13.621 22.68 15.251 ;
     RECT  0.144 15.493 0.168 15.589 ;
     RECT  24 15.013 24.408 15.733 ;
     RECT  2.4 14.963 14.232 15.973 ;
     RECT  24 15.733 24.456 16.451 ;
     RECT  2.4 15.973 14.808 16.501 ;
     RECT  15.984 15.011 19.032 16.835 ;
     RECT  0.144 15.589 0.312 16.885 ;
     RECT  2.4 16.501 14.856 16.933 ;
     RECT  16.08 16.835 19.032 16.933 ;
     RECT  20.4 15.253 20.568 16.933 ;
     RECT  16.08 16.933 20.568 17.075 ;
     RECT  16.08 17.075 16.344 17.459 ;
     RECT  0.144 16.885 0.408 17.461 ;
     RECT  21.84 15.251 22.68 17.461 ;
     RECT  24 16.451 24.408 17.461 ;
     RECT  16.08 17.459 16.296 17.699 ;
     RECT  0.144 17.461 0.504 17.939 ;
     RECT  21.84 17.461 24.408 17.989 ;
     RECT  17.712 17.075 20.568 18.083 ;
     RECT  20.544 18.083 20.568 18.181 ;
     RECT  16.08 17.699 16.2 18.757 ;
     RECT  0.144 17.939 0.408 18.851 ;
     RECT  21.84 17.989 24.504 18.851 ;
     RECT  2.304 16.933 14.856 18.899 ;
     RECT  17.712 18.083 19.512 18.947 ;
     RECT  24 18.851 24.504 18.995 ;
     RECT  17.712 18.947 19.416 19.091 ;
     RECT  0.192 18.851 0.408 19.141 ;
     RECT  24 18.995 24.456 19.331 ;
     RECT  20.544 18.181 20.76 19.333 ;
     RECT  17.712 19.091 19.032 19.379 ;
     RECT  16.08 18.757 16.296 19.525 ;
     RECT  2.304 18.899 5.112 19.715 ;
     RECT  15.984 19.525 16.296 19.861 ;
     RECT  2.4 19.715 5.112 19.909 ;
     RECT  6.096 18.899 14.856 19.909 ;
     RECT  18.192 19.379 19.032 20.149 ;
     RECT  20.496 19.333 20.76 20.149 ;
     RECT  27.072 7.381 27.096 20.339 ;
     RECT  15.984 19.861 17.16 20.725 ;
     RECT  18.192 20.149 20.76 20.725 ;
     RECT  24 19.331 24.408 20.821 ;
     RECT  15.984 20.725 20.76 21.539 ;
     RECT  24 20.821 24.504 21.539 ;
     RECT  0.192 19.141 0.456 21.731 ;
     RECT  2.4 19.909 14.856 21.923 ;
     RECT  16.176 21.539 17.16 21.923 ;
     RECT  0.192 21.731 0.36 21.971 ;
     RECT  24 21.539 24.408 21.973 ;
     RECT  0.192 21.971 0.264 22.019 ;
     RECT  2.4 21.923 10.296 22.019 ;
     RECT  0.192 22.019 0.216 22.021 ;
     RECT  21.84 18.851 22.68 22.067 ;
     RECT  16.272 21.923 17.16 22.211 ;
     RECT  21.84 22.067 21.864 22.403 ;
     RECT  11.568 21.923 14.856 22.547 ;
     RECT  27.6 21.061 27.624 22.549 ;
     RECT  18.6 21.539 20.76 22.741 ;
     RECT  18.6 22.741 21 22.787 ;
     RECT  0.144 22.021 0.216 22.835 ;
     RECT  11.568 22.547 14.328 23.027 ;
     RECT  26.688 22.549 27.624 23.171 ;
     RECT  23.904 21.973 24.408 23.315 ;
     RECT  12 23.027 14.328 23.411 ;
     RECT  27.6 23.171 27.624 23.411 ;
     RECT  2.4 22.019 10.008 23.891 ;
     RECT  16.512 22.211 17.16 24.083 ;
     RECT  12.72 23.411 14.328 24.131 ;
     RECT  24 23.315 24.408 24.323 ;
     RECT  32.592 22.741 32.616 24.515 ;
     RECT  2.4 23.891 8.52 24.563 ;
     RECT  27.648 23.557 27.96 24.611 ;
     RECT  3.84 24.563 8.52 24.707 ;
     RECT  11.664 24.517 11.688 24.707 ;
     RECT  0.144 22.835 0.168 24.805 ;
     RECT  17.136 24.083 17.16 24.947 ;
     RECT  0.144 24.805 0.216 24.949 ;
     RECT  12.72 24.131 14.136 24.997 ;
     RECT  11.952 24.997 14.136 25.139 ;
     RECT  3.84 24.707 8.328 25.187 ;
     RECT  0.144 24.949 0.312 25.235 ;
     RECT  0.144 25.235 0.216 25.283 ;
     RECT  18.6 22.787 19.752 25.621 ;
     RECT  3.84 25.187 5.064 25.715 ;
     RECT  6.576 25.187 8.328 26.053 ;
     RECT  9.504 23.891 10.008 26.053 ;
     RECT  6.576 26.053 10.008 26.435 ;
     RECT  0.144 25.283 0.168 26.723 ;
     RECT  5.04 25.715 5.064 26.819 ;
     RECT  3.936 25.715 3.96 27.205 ;
     RECT  24 24.323 24.312 27.205 ;
     RECT  25.632 17.077 25.656 27.205 ;
     RECT  18.48 25.621 19.752 27.347 ;
     RECT  9.504 26.435 10.008 27.395 ;
     RECT  12.72 25.139 14.136 27.395 ;
     RECT  18.6 27.347 19.752 27.395 ;
     RECT  32.88 25.189 32.904 27.635 ;
     RECT  34.8 2.151 35.112 27.781 ;
     RECT  27.648 24.611 27.672 27.877 ;
     RECT  34.704 27.781 35.112 27.877 ;
     RECT  13.2 27.395 14.136 27.971 ;
     RECT  3.936 27.205 4.872 28.307 ;
     RECT  3.936 28.307 3.96 28.451 ;
     RECT  6.576 26.435 8.328 28.547 ;
     RECT  18.6 27.395 19.704 28.645 ;
     RECT  20.736 22.787 21 28.645 ;
     RECT  18.6 28.645 21 28.691 ;
     RECT  9.504 27.395 9.576 28.933 ;
     RECT  9.216 28.933 9.576 28.979 ;
     RECT  15.408 28.549 15.432 29.027 ;
     RECT  13.2 27.971 13.512 29.029 ;
     RECT  24 27.205 25.656 29.075 ;
     RECT  27.312 27.877 27.672 29.123 ;
     RECT  15.312 29.029 15.336 30.035 ;
     RECT  31.392 29.029 31.416 30.035 ;
     RECT  18.6 28.691 18.912 30.037 ;
     RECT  29.4 2.151 29.712 30.037 ;
     RECT  0.144 29.797 0.168 30.083 ;
     RECT  16.752 26.773 16.776 30.181 ;
     RECT  34.704 27.877 35.208 30.181 ;
     RECT  20.448 28.691 21 30.371 ;
     RECT  29.088 30.037 29.712 30.467 ;
     RECT  13.2 29.029 14.28 30.469 ;
     RECT  16.368 30.181 16.776 30.803 ;
     RECT  18.192 30.037 18.912 30.851 ;
     RECT  20.496 30.371 21 30.899 ;
     RECT  13.2 30.469 14.856 31.139 ;
     RECT  9.216 28.979 9.528 31.235 ;
     RECT  9.504 31.235 9.528 31.379 ;
     RECT  16.368 30.803 16.392 31.379 ;
     RECT  34.704 30.181 35.304 31.379 ;
     RECT  20.736 30.899 21 31.571 ;
     RECT  14.544 31.139 14.856 31.619 ;
     RECT  27.648 29.123 27.672 31.763 ;
     RECT  14.544 31.619 14.568 32.195 ;
     RECT  0.144 32.293 0.168 32.483 ;
     RECT  18.48 30.851 18.912 32.531 ;
     RECT  29.4 30.467 29.712 32.821 ;
     RECT  6.576 28.547 8.112 33.875 ;
     RECT  6.672 33.875 8.112 33.923 ;
     RECT  29.28 32.821 29.712 34.165 ;
     RECT  5.184 28.309 5.208 34.259 ;
     RECT  10.992 32.293 11.016 34.357 ;
     RECT  31.632 33.541 31.656 34.403 ;
     RECT  0.144 33.829 0.168 35.027 ;
     RECT  33.024 34.357 33.048 35.363 ;
     RECT  10.992 34.357 11.736 35.843 ;
     RECT  25.632 29.075 25.656 35.939 ;
     RECT  0.144 36.037 0.168 36.371 ;
     RECT  28.752 34.165 29.712 36.373 ;
     RECT  2.4 24.563 2.712 36.469 ;
     RECT  13.2 31.139 13.512 36.757 ;
     RECT  20.976 31.571 21 36.803 ;
     RECT  24 29.075 24.312 36.949 ;
     RECT  24 36.949 24.984 36.997 ;
     RECT  2.4 36.469 3.336 37.043 ;
     RECT  6.672 33.923 6.696 37.045 ;
     RECT  7.8 33.923 8.112 37.045 ;
     RECT  10.992 35.843 11.016 37.045 ;
     RECT  10.992 37.045 11.4 37.189 ;
     RECT  38.736 37.141 38.76 37.331 ;
     RECT  28.656 36.373 29.712 37.379 ;
     RECT  34.704 31.379 35.112 37.429 ;
     RECT  6.672 37.045 8.112 37.573 ;
     RECT  24 36.997 26.568 37.619 ;
     RECT  6.672 37.573 8.712 37.667 ;
     RECT  40.2 2.151 40.512 37.765 ;
     RECT  40.08 37.765 40.512 37.955 ;
     RECT  10.368 37.189 11.4 38.005 ;
     RECT  10.224 38.005 11.4 38.147 ;
     RECT  38.064 38.245 38.184 38.389 ;
     RECT  4.512 37.573 4.536 38.435 ;
     RECT  10.224 38.147 11.016 38.435 ;
     RECT  34.656 37.429 35.112 38.629 ;
     RECT  36.144 38.389 36.168 38.629 ;
     RECT  7.8 37.667 8.712 38.675 ;
     RECT  34.656 38.629 36.168 38.677 ;
     RECT  38.064 38.389 38.28 38.723 ;
     RECT  15.744 38.629 15.768 38.725 ;
     RECT  38.064 38.723 38.088 38.771 ;
     RECT  26.16 37.619 26.568 38.965 ;
     RECT  34.656 38.677 36.264 39.059 ;
     RECT  29.4 37.379 29.712 39.061 ;
     RECT  10.224 38.435 10.824 39.205 ;
     RECT  26.16 38.965 26.712 39.253 ;
     RECT  32.496 38.005 32.52 39.347 ;
     RECT  34.656 39.059 35.208 39.349 ;
     RECT  36.816 39.397 36.936 39.539 ;
     RECT  28.992 39.061 29.712 39.635 ;
     RECT  13.2 36.757 14.472 39.637 ;
     RECT  13.008 39.637 14.472 39.733 ;
     RECT  24 37.619 24.984 39.779 ;
     RECT  36.816 39.539 36.84 39.779 ;
     RECT  12.72 39.733 14.472 39.781 ;
     RECT  12.528 39.781 14.472 39.829 ;
     RECT  12.432 39.829 14.472 39.877 ;
     RECT  15.744 38.725 15.96 39.877 ;
     RECT  26.16 39.253 26.76 39.877 ;
     RECT  34.416 39.349 35.208 39.877 ;
     RECT  33.936 39.877 35.208 40.069 ;
     RECT  40.2 37.955 40.512 40.069 ;
     RECT  33.648 40.069 35.208 40.117 ;
     RECT  40.2 40.069 40.824 40.211 ;
     RECT  33.456 40.117 35.208 40.357 ;
     RECT  7.8 38.675 8.112 40.453 ;
     RECT  9.264 39.205 10.824 40.453 ;
     RECT  12.336 39.877 14.472 40.453 ;
     RECT  7.8 40.453 14.472 40.499 ;
     RECT  15.504 39.877 15.96 40.499 ;
     RECT  15.504 40.499 15.528 40.595 ;
     RECT  25.68 39.877 26.76 40.885 ;
     RECT  24 39.779 24.552 40.981 ;
     RECT  25.68 40.885 27.048 40.981 ;
     RECT  33.264 40.357 35.208 40.981 ;
     RECT  36.24 40.933 36.264 40.981 ;
     RECT  2.4 37.043 2.712 41.049 ;
     RECT  18.6 32.531 18.912 41.049 ;
     RECT  29.4 39.635 29.712 41.049 ;
     RECT  40.2 40.211 40.512 41.049 ;
     RECT  2.4 41.049 2.52 41.063 ;
     RECT  7.8 40.499 13.992 41.063 ;
     RECT  18.6 41.049 18.72 41.063 ;
     RECT  24 40.981 27.048 41.063 ;
     RECT  29.4 41.049 29.52 41.063 ;
     RECT  40.2 41.049 40.32 41.063 ;
     RECT  8.496 41.063 13.992 42.181 ;
     RECT  8.4 42.181 13.992 43.045 ;
     RECT  8.304 43.045 13.992 43.152 ;
     RECT  24.048 41.063 27.048 43.152 ;
     RECT  33.264 40.981 36.264 43.152 ;
  END
END ot_qwen_tp8_pv_wide_ctl_t
END LIBRARY
